VERSION 5.8 ;
BUSBITCHARS "[]" ;
DIVIDERCHAR "/" ;
UNITS
    DATABASE MICRONS 1000 ;
END UNITS

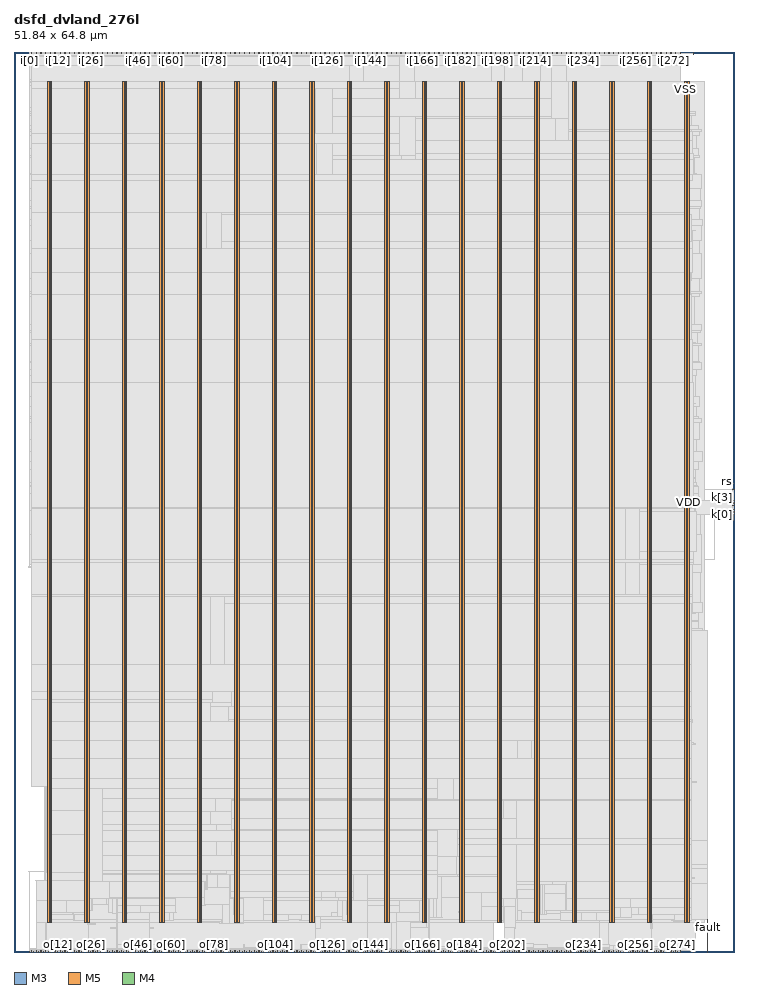
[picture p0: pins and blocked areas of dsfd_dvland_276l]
MACRO dsfd_dvland_276l
  FOREIGN dsfd_dvland_276l 0 0 ;
  CLASS BLOCK ;
  SIZE 51.84 BY 64.8 ;
  PIN ck
    DIRECTION INPUT ;
    USE SIGNAL ;
    PORT
      LAYER M3 ;
        RECT  48.924 0 48.942 0.038 ;
    END
    PORT
      LAYER M3 ;
        RECT  48.924 0.012 48.942 0.091 ;
    END
  END ck
  PIN ck_f
    DIRECTION INPUT ;
    USE SIGNAL ;
    PORT
      LAYER M3 ;
        RECT  48.924 64.762 48.942 64.8 ;
    END
    PORT
      LAYER M3 ;
        RECT  48.924 64.651 48.942 64.781 ;
    END
  END ck_f
  PIN fault
    DIRECTION OUTPUT ;
    USE SIGNAL ;
    PORT
      LAYER M3 ;
        RECT  49.932 0 49.95 0.038 ;
    END
    PORT
      LAYER M3 ;
        RECT  49.932 0.012 49.95 2.371 ;
    END
  END fault
  PIN i[0]
    DIRECTION INPUT ;
    USE SIGNAL ;
    PORT
      LAYER M3 ;
        RECT  1.08 64.762 1.098 64.8 ;
    END
  END i[0]
  PIN i[100]
    DIRECTION INPUT ;
    USE SIGNAL ;
    PORT
      LAYER M3 ;
        RECT  18.108 64.762 18.126 64.8 ;
    END
  END i[100]
  PIN i[101]
    DIRECTION INPUT ;
    USE SIGNAL ;
    PORT
      LAYER M5 ;
        RECT  18.288 64.716 18.312 64.8 ;
    END
  END i[101]
  PIN i[102]
    DIRECTION INPUT ;
    USE SIGNAL ;
    PORT
      LAYER M3 ;
        RECT  18.468 64.762 18.486 64.8 ;
    END
  END i[102]
  PIN i[103]
    DIRECTION INPUT ;
    USE SIGNAL ;
    PORT
      LAYER M5 ;
        RECT  18.624 64.716 18.648 64.8 ;
    END
  END i[103]
  PIN i[104]
    DIRECTION INPUT ;
    USE SIGNAL ;
    PORT
      LAYER M3 ;
        RECT  18.792 64.762 18.81 64.8 ;
    END
  END i[104]
  PIN i[105]
    DIRECTION INPUT ;
    USE SIGNAL ;
    PORT
      LAYER M5 ;
        RECT  18.96 64.716 18.984 64.8 ;
    END
  END i[105]
  PIN i[106]
    DIRECTION INPUT ;
    USE SIGNAL ;
    PORT
      LAYER M3 ;
        RECT  19.152 64.762 19.17 64.8 ;
    END
  END i[106]
  PIN i[107]
    DIRECTION INPUT ;
    USE SIGNAL ;
    PORT
      LAYER M5 ;
        RECT  19.296 64.716 19.32 64.8 ;
    END
  END i[107]
  PIN i[108]
    DIRECTION INPUT ;
    USE SIGNAL ;
    PORT
      LAYER M3 ;
        RECT  19.476 64.762 19.494 64.8 ;
    END
  END i[108]
  PIN i[109]
    DIRECTION INPUT ;
    USE SIGNAL ;
    PORT
      LAYER M5 ;
        RECT  19.632 64.716 19.656 64.8 ;
    END
  END i[109]
  PIN i[10]
    DIRECTION INPUT ;
    USE SIGNAL ;
    PORT
      LAYER M3 ;
        RECT  2.772 64.762 2.79 64.8 ;
    END
  END i[10]
  PIN i[110]
    DIRECTION INPUT ;
    USE SIGNAL ;
    PORT
      LAYER M3 ;
        RECT  19.836 64.762 19.854 64.8 ;
    END
  END i[110]
  PIN i[111]
    DIRECTION INPUT ;
    USE SIGNAL ;
    PORT
      LAYER M5 ;
        RECT  19.968 64.716 19.992 64.8 ;
    END
  END i[111]
  PIN i[112]
    DIRECTION INPUT ;
    USE SIGNAL ;
    PORT
      LAYER M3 ;
        RECT  20.16 64.762 20.178 64.8 ;
    END
  END i[112]
  PIN i[113]
    DIRECTION INPUT ;
    USE SIGNAL ;
    PORT
      LAYER M5 ;
        RECT  20.352 64.716 20.376 64.8 ;
    END
  END i[113]
  PIN i[114]
    DIRECTION INPUT ;
    USE SIGNAL ;
    PORT
      LAYER M3 ;
        RECT  20.52 64.762 20.538 64.8 ;
    END
  END i[114]
  PIN i[115]
    DIRECTION INPUT ;
    USE SIGNAL ;
    PORT
      LAYER M5 ;
        RECT  20.688 64.716 20.712 64.8 ;
    END
  END i[115]
  PIN i[116]
    DIRECTION INPUT ;
    USE SIGNAL ;
    PORT
      LAYER M3 ;
        RECT  20.844 64.762 20.862 64.8 ;
    END
  END i[116]
  PIN i[117]
    DIRECTION INPUT ;
    USE SIGNAL ;
    PORT
      LAYER M5 ;
        RECT  21.024 64.716 21.048 64.8 ;
    END
  END i[117]
  PIN i[118]
    DIRECTION INPUT ;
    USE SIGNAL ;
    PORT
      LAYER M3 ;
        RECT  21.204 64.762 21.222 64.8 ;
    END
  END i[118]
  PIN i[119]
    DIRECTION INPUT ;
    USE SIGNAL ;
    PORT
      LAYER M5 ;
        RECT  21.36 64.716 21.384 64.8 ;
    END
  END i[119]
  PIN i[11]
    DIRECTION INPUT ;
    USE SIGNAL ;
    PORT
      LAYER M5 ;
        RECT  2.928 64.716 2.952 64.8 ;
    END
  END i[11]
  PIN i[120]
    DIRECTION INPUT ;
    USE SIGNAL ;
    PORT
      LAYER M3 ;
        RECT  21.528 64.762 21.546 64.8 ;
    END
  END i[120]
  PIN i[121]
    DIRECTION INPUT ;
    USE SIGNAL ;
    PORT
      LAYER M5 ;
        RECT  21.696 64.716 21.72 64.8 ;
    END
  END i[121]
  PIN i[122]
    DIRECTION INPUT ;
    USE SIGNAL ;
    PORT
      LAYER M3 ;
        RECT  21.852 64.762 21.87 64.8 ;
    END
  END i[122]
  PIN i[123]
    DIRECTION INPUT ;
    USE SIGNAL ;
    PORT
      LAYER M5 ;
        RECT  22.032 64.716 22.056 64.8 ;
    END
  END i[123]
  PIN i[124]
    DIRECTION INPUT ;
    USE SIGNAL ;
    PORT
      LAYER M3 ;
        RECT  22.212 64.762 22.23 64.8 ;
    END
  END i[124]
  PIN i[125]
    DIRECTION INPUT ;
    USE SIGNAL ;
    PORT
      LAYER M5 ;
        RECT  22.368 64.716 22.392 64.8 ;
    END
  END i[125]
  PIN i[126]
    DIRECTION INPUT ;
    USE SIGNAL ;
    PORT
      LAYER M3 ;
        RECT  22.536 64.762 22.554 64.8 ;
    END
  END i[126]
  PIN i[127]
    DIRECTION INPUT ;
    USE SIGNAL ;
    PORT
      LAYER M5 ;
        RECT  22.704 64.716 22.728 64.8 ;
    END
  END i[127]
  PIN i[128]
    DIRECTION INPUT ;
    USE SIGNAL ;
    PORT
      LAYER M3 ;
        RECT  22.896 64.762 22.914 64.8 ;
    END
  END i[128]
  PIN i[129]
    DIRECTION INPUT ;
    USE SIGNAL ;
    PORT
      LAYER M5 ;
        RECT  23.04 64.716 23.064 64.8 ;
    END
  END i[129]
  PIN i[12]
    DIRECTION INPUT ;
    USE SIGNAL ;
    PORT
      LAYER M3 ;
        RECT  3.132 64.762 3.15 64.8 ;
    END
  END i[12]
  PIN i[130]
    DIRECTION INPUT ;
    USE SIGNAL ;
    PORT
      LAYER M3 ;
        RECT  23.22 64.762 23.238 64.8 ;
    END
  END i[130]
  PIN i[131]
    DIRECTION INPUT ;
    USE SIGNAL ;
    PORT
      LAYER M5 ;
        RECT  23.424 64.716 23.448 64.8 ;
    END
  END i[131]
  PIN i[132]
    DIRECTION INPUT ;
    USE SIGNAL ;
    PORT
      LAYER M3 ;
        RECT  23.58 64.762 23.598 64.8 ;
    END
  END i[132]
  PIN i[133]
    DIRECTION INPUT ;
    USE SIGNAL ;
    PORT
      LAYER M5 ;
        RECT  23.76 64.716 23.784 64.8 ;
    END
  END i[133]
  PIN i[134]
    DIRECTION INPUT ;
    USE SIGNAL ;
    PORT
      LAYER M3 ;
        RECT  23.904 64.762 23.922 64.8 ;
    END
  END i[134]
  PIN i[135]
    DIRECTION INPUT ;
    USE SIGNAL ;
    PORT
      LAYER M5 ;
        RECT  24.096 64.716 24.12 64.8 ;
    END
  END i[135]
  PIN i[136]
    DIRECTION INPUT ;
    USE SIGNAL ;
    PORT
      LAYER M3 ;
        RECT  24.264 64.762 24.282 64.8 ;
    END
  END i[136]
  PIN i[137]
    DIRECTION INPUT ;
    USE SIGNAL ;
    PORT
      LAYER M5 ;
        RECT  24.432 64.716 24.456 64.8 ;
    END
  END i[137]
  PIN i[138]
    DIRECTION INPUT ;
    USE SIGNAL ;
    PORT
      LAYER M3 ;
        RECT  24.588 64.762 24.606 64.8 ;
    END
  END i[138]
  PIN i[139]
    DIRECTION INPUT ;
    USE SIGNAL ;
    PORT
      LAYER M5 ;
        RECT  24.768 64.716 24.792 64.8 ;
    END
  END i[139]
  PIN i[13]
    DIRECTION INPUT ;
    USE SIGNAL ;
    PORT
      LAYER M5 ;
        RECT  3.312 64.716 3.336 64.8 ;
    END
  END i[13]
  PIN i[140]
    DIRECTION INPUT ;
    USE SIGNAL ;
    PORT
      LAYER M3 ;
        RECT  24.948 64.762 24.966 64.8 ;
    END
  END i[140]
  PIN i[141]
    DIRECTION INPUT ;
    USE SIGNAL ;
    PORT
      LAYER M5 ;
        RECT  25.104 64.716 25.128 64.8 ;
    END
  END i[141]
  PIN i[142]
    DIRECTION INPUT ;
    USE SIGNAL ;
    PORT
      LAYER M3 ;
        RECT  25.272 64.762 25.29 64.8 ;
    END
  END i[142]
  PIN i[143]
    DIRECTION INPUT ;
    USE SIGNAL ;
    PORT
      LAYER M5 ;
        RECT  25.44 64.716 25.464 64.8 ;
    END
  END i[143]
  PIN i[144]
    DIRECTION INPUT ;
    USE SIGNAL ;
    PORT
      LAYER M3 ;
        RECT  25.632 64.762 25.65 64.8 ;
    END
  END i[144]
  PIN i[145]
    DIRECTION INPUT ;
    USE SIGNAL ;
    PORT
      LAYER M5 ;
        RECT  25.776 64.716 25.8 64.8 ;
    END
  END i[145]
  PIN i[146]
    DIRECTION INPUT ;
    USE SIGNAL ;
    PORT
      LAYER M3 ;
        RECT  25.956 64.762 25.974 64.8 ;
    END
  END i[146]
  PIN i[147]
    DIRECTION INPUT ;
    USE SIGNAL ;
    PORT
      LAYER M5 ;
        RECT  26.112 64.716 26.136 64.8 ;
    END
  END i[147]
  PIN i[148]
    DIRECTION INPUT ;
    USE SIGNAL ;
    PORT
      LAYER M3 ;
        RECT  26.316 64.762 26.334 64.8 ;
    END
  END i[148]
  PIN i[149]
    DIRECTION INPUT ;
    USE SIGNAL ;
    PORT
      LAYER M5 ;
        RECT  26.448 64.716 26.472 64.8 ;
    END
  END i[149]
  PIN i[14]
    DIRECTION INPUT ;
    USE SIGNAL ;
    PORT
      LAYER M3 ;
        RECT  3.456 64.762 3.474 64.8 ;
    END
  END i[14]
  PIN i[150]
    DIRECTION INPUT ;
    USE SIGNAL ;
    PORT
      LAYER M3 ;
        RECT  26.64 64.762 26.658 64.8 ;
    END
  END i[150]
  PIN i[151]
    DIRECTION INPUT ;
    USE SIGNAL ;
    PORT
      LAYER M5 ;
        RECT  26.832 64.716 26.856 64.8 ;
    END
  END i[151]
  PIN i[152]
    DIRECTION INPUT ;
    USE SIGNAL ;
    PORT
      LAYER M3 ;
        RECT  27 64.762 27.018 64.8 ;
    END
  END i[152]
  PIN i[153]
    DIRECTION INPUT ;
    USE SIGNAL ;
    PORT
      LAYER M5 ;
        RECT  27.168 64.716 27.192 64.8 ;
    END
  END i[153]
  PIN i[154]
    DIRECTION INPUT ;
    USE SIGNAL ;
    PORT
      LAYER M3 ;
        RECT  27.324 64.762 27.342 64.8 ;
    END
  END i[154]
  PIN i[155]
    DIRECTION INPUT ;
    USE SIGNAL ;
    PORT
      LAYER M5 ;
        RECT  27.504 64.716 27.528 64.8 ;
    END
  END i[155]
  PIN i[156]
    DIRECTION INPUT ;
    USE SIGNAL ;
    PORT
      LAYER M3 ;
        RECT  27.648 64.762 27.666 64.8 ;
    END
  END i[156]
  PIN i[157]
    DIRECTION INPUT ;
    USE SIGNAL ;
    PORT
      LAYER M5 ;
        RECT  27.84 64.716 27.864 64.8 ;
    END
  END i[157]
  PIN i[158]
    DIRECTION INPUT ;
    USE SIGNAL ;
    PORT
      LAYER M3 ;
        RECT  28.008 64.762 28.026 64.8 ;
    END
  END i[158]
  PIN i[159]
    DIRECTION INPUT ;
    USE SIGNAL ;
    PORT
      LAYER M5 ;
        RECT  28.176 64.716 28.2 64.8 ;
    END
  END i[159]
  PIN i[15]
    DIRECTION INPUT ;
    USE SIGNAL ;
    PORT
      LAYER M5 ;
        RECT  3.648 64.716 3.672 64.8 ;
    END
  END i[15]
  PIN i[160]
    DIRECTION INPUT ;
    USE SIGNAL ;
    PORT
      LAYER M3 ;
        RECT  28.332 64.762 28.35 64.8 ;
    END
  END i[160]
  PIN i[161]
    DIRECTION INPUT ;
    USE SIGNAL ;
    PORT
      LAYER M5 ;
        RECT  28.512 64.716 28.536 64.8 ;
    END
  END i[161]
  PIN i[162]
    DIRECTION INPUT ;
    USE SIGNAL ;
    PORT
      LAYER M3 ;
        RECT  28.692 64.762 28.71 64.8 ;
    END
  END i[162]
  PIN i[163]
    DIRECTION INPUT ;
    USE SIGNAL ;
    PORT
      LAYER M5 ;
        RECT  28.848 64.716 28.872 64.8 ;
    END
  END i[163]
  PIN i[164]
    DIRECTION INPUT ;
    USE SIGNAL ;
    PORT
      LAYER M3 ;
        RECT  29.016 64.762 29.034 64.8 ;
    END
  END i[164]
  PIN i[165]
    DIRECTION INPUT ;
    USE SIGNAL ;
    PORT
      LAYER M5 ;
        RECT  29.184 64.716 29.208 64.8 ;
    END
  END i[165]
  PIN i[166]
    DIRECTION INPUT ;
    USE SIGNAL ;
    PORT
      LAYER M3 ;
        RECT  29.376 64.762 29.394 64.8 ;
    END
  END i[166]
  PIN i[167]
    DIRECTION INPUT ;
    USE SIGNAL ;
    PORT
      LAYER M5 ;
        RECT  29.52 64.716 29.544 64.8 ;
    END
  END i[167]
  PIN i[168]
    DIRECTION INPUT ;
    USE SIGNAL ;
    PORT
      LAYER M3 ;
        RECT  29.7 64.762 29.718 64.8 ;
    END
  END i[168]
  PIN i[169]
    DIRECTION INPUT ;
    USE SIGNAL ;
    PORT
      LAYER M5 ;
        RECT  29.856 64.716 29.88 64.8 ;
    END
  END i[169]
  PIN i[16]
    DIRECTION INPUT ;
    USE SIGNAL ;
    PORT
      LAYER M3 ;
        RECT  3.816 64.762 3.834 64.8 ;
    END
  END i[16]
  PIN i[170]
    DIRECTION INPUT ;
    USE SIGNAL ;
    PORT
      LAYER M3 ;
        RECT  30.06 64.762 30.078 64.8 ;
    END
  END i[170]
  PIN i[171]
    DIRECTION INPUT ;
    USE SIGNAL ;
    PORT
      LAYER M5 ;
        RECT  30.24 64.716 30.264 64.8 ;
    END
  END i[171]
  PIN i[172]
    DIRECTION INPUT ;
    USE SIGNAL ;
    PORT
      LAYER M3 ;
        RECT  30.384 64.762 30.402 64.8 ;
    END
  END i[172]
  PIN i[173]
    DIRECTION INPUT ;
    USE SIGNAL ;
    PORT
      LAYER M5 ;
        RECT  30.576 64.716 30.6 64.8 ;
    END
  END i[173]
  PIN i[174]
    DIRECTION INPUT ;
    USE SIGNAL ;
    PORT
      LAYER M3 ;
        RECT  30.744 64.762 30.762 64.8 ;
    END
  END i[174]
  PIN i[175]
    DIRECTION INPUT ;
    USE SIGNAL ;
    PORT
      LAYER M5 ;
        RECT  30.912 64.716 30.936 64.8 ;
    END
  END i[175]
  PIN i[176]
    DIRECTION INPUT ;
    USE SIGNAL ;
    PORT
      LAYER M3 ;
        RECT  31.068 64.762 31.086 64.8 ;
    END
  END i[176]
  PIN i[177]
    DIRECTION INPUT ;
    USE SIGNAL ;
    PORT
      LAYER M5 ;
        RECT  31.248 64.716 31.272 64.8 ;
    END
  END i[177]
  PIN i[178]
    DIRECTION INPUT ;
    USE SIGNAL ;
    PORT
      LAYER M3 ;
        RECT  31.428 64.762 31.446 64.8 ;
    END
  END i[178]
  PIN i[179]
    DIRECTION INPUT ;
    USE SIGNAL ;
    PORT
      LAYER M5 ;
        RECT  31.584 64.716 31.608 64.8 ;
    END
  END i[179]
  PIN i[17]
    DIRECTION INPUT ;
    USE SIGNAL ;
    PORT
      LAYER M5 ;
        RECT  3.984 64.716 4.008 64.8 ;
    END
  END i[17]
  PIN i[180]
    DIRECTION INPUT ;
    USE SIGNAL ;
    PORT
      LAYER M3 ;
        RECT  31.752 64.762 31.77 64.8 ;
    END
  END i[180]
  PIN i[181]
    DIRECTION INPUT ;
    USE SIGNAL ;
    PORT
      LAYER M5 ;
        RECT  31.92 64.716 31.944 64.8 ;
    END
  END i[181]
  PIN i[182]
    DIRECTION INPUT ;
    USE SIGNAL ;
    PORT
      LAYER M3 ;
        RECT  32.112 64.762 32.13 64.8 ;
    END
  END i[182]
  PIN i[183]
    DIRECTION INPUT ;
    USE SIGNAL ;
    PORT
      LAYER M5 ;
        RECT  32.256 64.716 32.28 64.8 ;
    END
  END i[183]
  PIN i[184]
    DIRECTION INPUT ;
    USE SIGNAL ;
    PORT
      LAYER M3 ;
        RECT  32.436 64.762 32.454 64.8 ;
    END
  END i[184]
  PIN i[185]
    DIRECTION INPUT ;
    USE SIGNAL ;
    PORT
      LAYER M5 ;
        RECT  32.592 64.716 32.616 64.8 ;
    END
  END i[185]
  PIN i[186]
    DIRECTION INPUT ;
    USE SIGNAL ;
    PORT
      LAYER M3 ;
        RECT  32.76 64.762 32.778 64.8 ;
    END
  END i[186]
  PIN i[187]
    DIRECTION INPUT ;
    USE SIGNAL ;
    PORT
      LAYER M5 ;
        RECT  32.928 64.716 32.952 64.8 ;
    END
  END i[187]
  PIN i[188]
    DIRECTION INPUT ;
    USE SIGNAL ;
    PORT
      LAYER M3 ;
        RECT  33.12 64.762 33.138 64.8 ;
    END
  END i[188]
  PIN i[189]
    DIRECTION INPUT ;
    USE SIGNAL ;
    PORT
      LAYER M5 ;
        RECT  33.264 64.716 33.288 64.8 ;
    END
  END i[189]
  PIN i[18]
    DIRECTION INPUT ;
    USE SIGNAL ;
    PORT
      LAYER M3 ;
        RECT  4.14 64.762 4.158 64.8 ;
    END
  END i[18]
  PIN i[190]
    DIRECTION INPUT ;
    USE SIGNAL ;
    PORT
      LAYER M3 ;
        RECT  33.444 64.762 33.462 64.8 ;
    END
  END i[190]
  PIN i[191]
    DIRECTION INPUT ;
    USE SIGNAL ;
    PORT
      LAYER M5 ;
        RECT  33.648 64.716 33.672 64.8 ;
    END
  END i[191]
  PIN i[192]
    DIRECTION INPUT ;
    USE SIGNAL ;
    PORT
      LAYER M3 ;
        RECT  33.804 64.762 33.822 64.8 ;
    END
  END i[192]
  PIN i[193]
    DIRECTION INPUT ;
    USE SIGNAL ;
    PORT
      LAYER M5 ;
        RECT  33.984 64.716 34.008 64.8 ;
    END
  END i[193]
  PIN i[194]
    DIRECTION INPUT ;
    USE SIGNAL ;
    PORT
      LAYER M3 ;
        RECT  34.128 64.762 34.146 64.8 ;
    END
  END i[194]
  PIN i[195]
    DIRECTION INPUT ;
    USE SIGNAL ;
    PORT
      LAYER M5 ;
        RECT  34.32 64.716 34.344 64.8 ;
    END
  END i[195]
  PIN i[196]
    DIRECTION INPUT ;
    USE SIGNAL ;
    PORT
      LAYER M3 ;
        RECT  34.488 64.762 34.506 64.8 ;
    END
  END i[196]
  PIN i[197]
    DIRECTION INPUT ;
    USE SIGNAL ;
    PORT
      LAYER M5 ;
        RECT  34.656 64.716 34.68 64.8 ;
    END
  END i[197]
  PIN i[198]
    DIRECTION INPUT ;
    USE SIGNAL ;
    PORT
      LAYER M3 ;
        RECT  34.812 64.762 34.83 64.8 ;
    END
  END i[198]
  PIN i[199]
    DIRECTION INPUT ;
    USE SIGNAL ;
    PORT
      LAYER M5 ;
        RECT  34.992 64.716 35.016 64.8 ;
    END
  END i[199]
  PIN i[19]
    DIRECTION INPUT ;
    USE SIGNAL ;
    PORT
      LAYER M5 ;
        RECT  4.32 64.716 4.344 64.8 ;
    END
  END i[19]
  PIN i[1]
    DIRECTION INPUT ;
    USE SIGNAL ;
    PORT
      LAYER M5 ;
        RECT  1.248 64.716 1.272 64.8 ;
    END
  END i[1]
  PIN i[200]
    DIRECTION INPUT ;
    USE SIGNAL ;
    PORT
      LAYER M3 ;
        RECT  35.172 64.762 35.19 64.8 ;
    END
  END i[200]
  PIN i[201]
    DIRECTION INPUT ;
    USE SIGNAL ;
    PORT
      LAYER M5 ;
        RECT  35.328 64.716 35.352 64.8 ;
    END
  END i[201]
  PIN i[202]
    DIRECTION INPUT ;
    USE SIGNAL ;
    PORT
      LAYER M3 ;
        RECT  35.496 64.762 35.514 64.8 ;
    END
  END i[202]
  PIN i[203]
    DIRECTION INPUT ;
    USE SIGNAL ;
    PORT
      LAYER M5 ;
        RECT  35.664 64.716 35.688 64.8 ;
    END
  END i[203]
  PIN i[204]
    DIRECTION INPUT ;
    USE SIGNAL ;
    PORT
      LAYER M3 ;
        RECT  35.856 64.762 35.874 64.8 ;
    END
  END i[204]
  PIN i[205]
    DIRECTION INPUT ;
    USE SIGNAL ;
    PORT
      LAYER M5 ;
        RECT  36 64.716 36.024 64.8 ;
    END
  END i[205]
  PIN i[206]
    DIRECTION INPUT ;
    USE SIGNAL ;
    PORT
      LAYER M3 ;
        RECT  36.18 64.762 36.198 64.8 ;
    END
  END i[206]
  PIN i[207]
    DIRECTION INPUT ;
    USE SIGNAL ;
    PORT
      LAYER M5 ;
        RECT  36.336 64.716 36.36 64.8 ;
    END
  END i[207]
  PIN i[208]
    DIRECTION INPUT ;
    USE SIGNAL ;
    PORT
      LAYER M3 ;
        RECT  36.54 64.762 36.558 64.8 ;
    END
  END i[208]
  PIN i[209]
    DIRECTION INPUT ;
    USE SIGNAL ;
    PORT
      LAYER M5 ;
        RECT  36.672 64.716 36.696 64.8 ;
    END
  END i[209]
  PIN i[20]
    DIRECTION INPUT ;
    USE SIGNAL ;
    PORT
      LAYER M3 ;
        RECT  4.5 64.762 4.518 64.8 ;
    END
  END i[20]
  PIN i[210]
    DIRECTION INPUT ;
    USE SIGNAL ;
    PORT
      LAYER M3 ;
        RECT  36.864 64.762 36.882 64.8 ;
    END
  END i[210]
  PIN i[211]
    DIRECTION INPUT ;
    USE SIGNAL ;
    PORT
      LAYER M5 ;
        RECT  37.056 64.716 37.08 64.8 ;
    END
  END i[211]
  PIN i[212]
    DIRECTION INPUT ;
    USE SIGNAL ;
    PORT
      LAYER M3 ;
        RECT  37.224 64.762 37.242 64.8 ;
    END
  END i[212]
  PIN i[213]
    DIRECTION INPUT ;
    USE SIGNAL ;
    PORT
      LAYER M5 ;
        RECT  37.392 64.716 37.416 64.8 ;
    END
  END i[213]
  PIN i[214]
    DIRECTION INPUT ;
    USE SIGNAL ;
    PORT
      LAYER M3 ;
        RECT  37.548 64.762 37.566 64.8 ;
    END
  END i[214]
  PIN i[215]
    DIRECTION INPUT ;
    USE SIGNAL ;
    PORT
      LAYER M5 ;
        RECT  37.728 64.716 37.752 64.8 ;
    END
  END i[215]
  PIN i[216]
    DIRECTION INPUT ;
    USE SIGNAL ;
    PORT
      LAYER M3 ;
        RECT  37.908 64.762 37.926 64.8 ;
    END
  END i[216]
  PIN i[217]
    DIRECTION INPUT ;
    USE SIGNAL ;
    PORT
      LAYER M5 ;
        RECT  38.064 64.716 38.088 64.8 ;
    END
  END i[217]
  PIN i[218]
    DIRECTION INPUT ;
    USE SIGNAL ;
    PORT
      LAYER M3 ;
        RECT  38.232 64.762 38.25 64.8 ;
    END
  END i[218]
  PIN i[219]
    DIRECTION INPUT ;
    USE SIGNAL ;
    PORT
      LAYER M5 ;
        RECT  38.4 64.716 38.424 64.8 ;
    END
  END i[219]
  PIN i[21]
    DIRECTION INPUT ;
    USE SIGNAL ;
    PORT
      LAYER M5 ;
        RECT  4.656 64.716 4.68 64.8 ;
    END
  END i[21]
  PIN i[220]
    DIRECTION INPUT ;
    USE SIGNAL ;
    PORT
      LAYER M3 ;
        RECT  38.556 64.762 38.574 64.8 ;
    END
  END i[220]
  PIN i[221]
    DIRECTION INPUT ;
    USE SIGNAL ;
    PORT
      LAYER M5 ;
        RECT  38.736 64.716 38.76 64.8 ;
    END
  END i[221]
  PIN i[222]
    DIRECTION INPUT ;
    USE SIGNAL ;
    PORT
      LAYER M3 ;
        RECT  38.916 64.762 38.934 64.8 ;
    END
  END i[222]
  PIN i[223]
    DIRECTION INPUT ;
    USE SIGNAL ;
    PORT
      LAYER M5 ;
        RECT  39.072 64.716 39.096 64.8 ;
    END
  END i[223]
  PIN i[224]
    DIRECTION INPUT ;
    USE SIGNAL ;
    PORT
      LAYER M3 ;
        RECT  39.24 64.762 39.258 64.8 ;
    END
  END i[224]
  PIN i[225]
    DIRECTION INPUT ;
    USE SIGNAL ;
    PORT
      LAYER M5 ;
        RECT  39.408 64.716 39.432 64.8 ;
    END
  END i[225]
  PIN i[226]
    DIRECTION INPUT ;
    USE SIGNAL ;
    PORT
      LAYER M3 ;
        RECT  39.6 64.762 39.618 64.8 ;
    END
  END i[226]
  PIN i[227]
    DIRECTION INPUT ;
    USE SIGNAL ;
    PORT
      LAYER M5 ;
        RECT  39.744 64.716 39.768 64.8 ;
    END
  END i[227]
  PIN i[228]
    DIRECTION INPUT ;
    USE SIGNAL ;
    PORT
      LAYER M3 ;
        RECT  39.924 64.762 39.942 64.8 ;
    END
  END i[228]
  PIN i[229]
    DIRECTION INPUT ;
    USE SIGNAL ;
    PORT
      LAYER M5 ;
        RECT  40.08 64.716 40.104 64.8 ;
    END
  END i[229]
  PIN i[22]
    DIRECTION INPUT ;
    USE SIGNAL ;
    PORT
      LAYER M3 ;
        RECT  4.824 64.762 4.842 64.8 ;
    END
  END i[22]
  PIN i[230]
    DIRECTION INPUT ;
    USE SIGNAL ;
    PORT
      LAYER M3 ;
        RECT  40.284 64.762 40.302 64.8 ;
    END
  END i[230]
  PIN i[231]
    DIRECTION INPUT ;
    USE SIGNAL ;
    PORT
      LAYER M5 ;
        RECT  40.464 64.716 40.488 64.8 ;
    END
  END i[231]
  PIN i[232]
    DIRECTION INPUT ;
    USE SIGNAL ;
    PORT
      LAYER M3 ;
        RECT  40.608 64.762 40.626 64.8 ;
    END
  END i[232]
  PIN i[233]
    DIRECTION INPUT ;
    USE SIGNAL ;
    PORT
      LAYER M5 ;
        RECT  40.8 64.716 40.824 64.8 ;
    END
  END i[233]
  PIN i[234]
    DIRECTION INPUT ;
    USE SIGNAL ;
    PORT
      LAYER M3 ;
        RECT  40.968 64.762 40.986 64.8 ;
    END
  END i[234]
  PIN i[235]
    DIRECTION INPUT ;
    USE SIGNAL ;
    PORT
      LAYER M5 ;
        RECT  41.136 64.716 41.16 64.8 ;
    END
  END i[235]
  PIN i[236]
    DIRECTION INPUT ;
    USE SIGNAL ;
    PORT
      LAYER M3 ;
        RECT  41.292 64.762 41.31 64.8 ;
    END
  END i[236]
  PIN i[237]
    DIRECTION INPUT ;
    USE SIGNAL ;
    PORT
      LAYER M5 ;
        RECT  41.472 64.716 41.496 64.8 ;
    END
  END i[237]
  PIN i[238]
    DIRECTION INPUT ;
    USE SIGNAL ;
    PORT
      LAYER M3 ;
        RECT  41.652 64.762 41.67 64.8 ;
    END
  END i[238]
  PIN i[239]
    DIRECTION INPUT ;
    USE SIGNAL ;
    PORT
      LAYER M5 ;
        RECT  41.808 64.716 41.832 64.8 ;
    END
  END i[239]
  PIN i[23]
    DIRECTION INPUT ;
    USE SIGNAL ;
    PORT
      LAYER M5 ;
        RECT  4.992 64.716 5.016 64.8 ;
    END
  END i[23]
  PIN i[240]
    DIRECTION INPUT ;
    USE SIGNAL ;
    PORT
      LAYER M3 ;
        RECT  41.976 64.762 41.994 64.8 ;
    END
  END i[240]
  PIN i[241]
    DIRECTION INPUT ;
    USE SIGNAL ;
    PORT
      LAYER M5 ;
        RECT  42.144 64.716 42.168 64.8 ;
    END
  END i[241]
  PIN i[242]
    DIRECTION INPUT ;
    USE SIGNAL ;
    PORT
      LAYER M3 ;
        RECT  42.336 64.762 42.354 64.8 ;
    END
  END i[242]
  PIN i[243]
    DIRECTION INPUT ;
    USE SIGNAL ;
    PORT
      LAYER M5 ;
        RECT  42.48 64.716 42.504 64.8 ;
    END
  END i[243]
  PIN i[244]
    DIRECTION INPUT ;
    USE SIGNAL ;
    PORT
      LAYER M3 ;
        RECT  42.66 64.762 42.678 64.8 ;
    END
  END i[244]
  PIN i[245]
    DIRECTION INPUT ;
    USE SIGNAL ;
    PORT
      LAYER M5 ;
        RECT  42.816 64.716 42.84 64.8 ;
    END
  END i[245]
  PIN i[246]
    DIRECTION INPUT ;
    USE SIGNAL ;
    PORT
      LAYER M3 ;
        RECT  43.02 64.762 43.038 64.8 ;
    END
  END i[246]
  PIN i[247]
    DIRECTION INPUT ;
    USE SIGNAL ;
    PORT
      LAYER M5 ;
        RECT  43.152 64.716 43.176 64.8 ;
    END
  END i[247]
  PIN i[248]
    DIRECTION INPUT ;
    USE SIGNAL ;
    PORT
      LAYER M3 ;
        RECT  43.344 64.762 43.362 64.8 ;
    END
  END i[248]
  PIN i[249]
    DIRECTION INPUT ;
    USE SIGNAL ;
    PORT
      LAYER M5 ;
        RECT  43.488 64.716 43.512 64.8 ;
    END
  END i[249]
  PIN i[24]
    DIRECTION INPUT ;
    USE SIGNAL ;
    PORT
      LAYER M3 ;
        RECT  5.184 64.762 5.202 64.8 ;
    END
  END i[24]
  PIN i[250]
    DIRECTION INPUT ;
    USE SIGNAL ;
    PORT
      LAYER M3 ;
        RECT  43.668 64.762 43.686 64.8 ;
    END
  END i[250]
  PIN i[251]
    DIRECTION INPUT ;
    USE SIGNAL ;
    PORT
      LAYER M5 ;
        RECT  43.872 64.716 43.896 64.8 ;
    END
  END i[251]
  PIN i[252]
    DIRECTION INPUT ;
    USE SIGNAL ;
    PORT
      LAYER M3 ;
        RECT  44.028 64.762 44.046 64.8 ;
    END
  END i[252]
  PIN i[253]
    DIRECTION INPUT ;
    USE SIGNAL ;
    PORT
      LAYER M5 ;
        RECT  44.208 64.716 44.232 64.8 ;
    END
  END i[253]
  PIN i[254]
    DIRECTION INPUT ;
    USE SIGNAL ;
    PORT
      LAYER M3 ;
        RECT  44.352 64.762 44.37 64.8 ;
    END
  END i[254]
  PIN i[255]
    DIRECTION INPUT ;
    USE SIGNAL ;
    PORT
      LAYER M5 ;
        RECT  44.544 64.716 44.568 64.8 ;
    END
  END i[255]
  PIN i[256]
    DIRECTION INPUT ;
    USE SIGNAL ;
    PORT
      LAYER M3 ;
        RECT  44.712 64.762 44.73 64.8 ;
    END
  END i[256]
  PIN i[257]
    DIRECTION INPUT ;
    USE SIGNAL ;
    PORT
      LAYER M5 ;
        RECT  44.88 64.716 44.904 64.8 ;
    END
  END i[257]
  PIN i[258]
    DIRECTION INPUT ;
    USE SIGNAL ;
    PORT
      LAYER M3 ;
        RECT  45.036 64.762 45.054 64.8 ;
    END
  END i[258]
  PIN i[259]
    DIRECTION INPUT ;
    USE SIGNAL ;
    PORT
      LAYER M5 ;
        RECT  45.216 64.716 45.24 64.8 ;
    END
  END i[259]
  PIN i[25]
    DIRECTION INPUT ;
    USE SIGNAL ;
    PORT
      LAYER M5 ;
        RECT  5.328 64.716 5.352 64.8 ;
    END
  END i[25]
  PIN i[260]
    DIRECTION INPUT ;
    USE SIGNAL ;
    PORT
      LAYER M3 ;
        RECT  45.396 64.762 45.414 64.8 ;
    END
  END i[260]
  PIN i[261]
    DIRECTION INPUT ;
    USE SIGNAL ;
    PORT
      LAYER M5 ;
        RECT  45.552 64.716 45.576 64.8 ;
    END
  END i[261]
  PIN i[262]
    DIRECTION INPUT ;
    USE SIGNAL ;
    PORT
      LAYER M3 ;
        RECT  45.72 64.762 45.738 64.8 ;
    END
  END i[262]
  PIN i[263]
    DIRECTION INPUT ;
    USE SIGNAL ;
    PORT
      LAYER M5 ;
        RECT  45.888 64.716 45.912 64.8 ;
    END
  END i[263]
  PIN i[264]
    DIRECTION INPUT ;
    USE SIGNAL ;
    PORT
      LAYER M3 ;
        RECT  46.08 64.762 46.098 64.8 ;
    END
  END i[264]
  PIN i[265]
    DIRECTION INPUT ;
    USE SIGNAL ;
    PORT
      LAYER M5 ;
        RECT  46.224 64.716 46.248 64.8 ;
    END
  END i[265]
  PIN i[266]
    DIRECTION INPUT ;
    USE SIGNAL ;
    PORT
      LAYER M3 ;
        RECT  46.404 64.762 46.422 64.8 ;
    END
  END i[266]
  PIN i[267]
    DIRECTION INPUT ;
    USE SIGNAL ;
    PORT
      LAYER M5 ;
        RECT  46.56 64.716 46.584 64.8 ;
    END
  END i[267]
  PIN i[268]
    DIRECTION INPUT ;
    USE SIGNAL ;
    PORT
      LAYER M3 ;
        RECT  46.764 64.762 46.782 64.8 ;
    END
  END i[268]
  PIN i[269]
    DIRECTION INPUT ;
    USE SIGNAL ;
    PORT
      LAYER M5 ;
        RECT  46.944 64.716 46.968 64.8 ;
    END
  END i[269]
  PIN i[26]
    DIRECTION INPUT ;
    USE SIGNAL ;
    PORT
      LAYER M3 ;
        RECT  5.508 64.762 5.526 64.8 ;
    END
  END i[26]
  PIN i[270]
    DIRECTION INPUT ;
    USE SIGNAL ;
    PORT
      LAYER M3 ;
        RECT  47.088 64.762 47.106 64.8 ;
    END
  END i[270]
  PIN i[271]
    DIRECTION INPUT ;
    USE SIGNAL ;
    PORT
      LAYER M5 ;
        RECT  47.28 64.716 47.304 64.8 ;
    END
  END i[271]
  PIN i[272]
    DIRECTION INPUT ;
    USE SIGNAL ;
    PORT
      LAYER M3 ;
        RECT  47.448 64.762 47.466 64.8 ;
    END
  END i[272]
  PIN i[273]
    DIRECTION INPUT ;
    USE SIGNAL ;
    PORT
      LAYER M5 ;
        RECT  47.616 64.716 47.64 64.8 ;
    END
  END i[273]
  PIN i[274]
    DIRECTION INPUT ;
    USE SIGNAL ;
    PORT
      LAYER M3 ;
        RECT  47.772 64.762 47.79 64.8 ;
    END
  END i[274]
  PIN i[275]
    DIRECTION INPUT ;
    USE SIGNAL ;
    PORT
      LAYER M5 ;
        RECT  47.952 64.716 47.976 64.8 ;
    END
  END i[275]
  PIN i[27]
    DIRECTION INPUT ;
    USE SIGNAL ;
    PORT
      LAYER M5 ;
        RECT  5.664 64.716 5.688 64.8 ;
    END
  END i[27]
  PIN i[28]
    DIRECTION INPUT ;
    USE SIGNAL ;
    PORT
      LAYER M3 ;
        RECT  5.832 64.762 5.85 64.8 ;
    END
  END i[28]
  PIN i[29]
    DIRECTION INPUT ;
    USE SIGNAL ;
    PORT
      LAYER M5 ;
        RECT  6 64.716 6.024 64.8 ;
    END
  END i[29]
  PIN i[2]
    DIRECTION INPUT ;
    USE SIGNAL ;
    PORT
      LAYER M3 ;
        RECT  1.404 64.762 1.422 64.8 ;
    END
  END i[2]
  PIN i[30]
    DIRECTION INPUT ;
    USE SIGNAL ;
    PORT
      LAYER M3 ;
        RECT  6.192 64.762 6.21 64.8 ;
    END
  END i[30]
  PIN i[31]
    DIRECTION INPUT ;
    USE SIGNAL ;
    PORT
      LAYER M5 ;
        RECT  6.336 64.716 6.36 64.8 ;
    END
  END i[31]
  PIN i[32]
    DIRECTION INPUT ;
    USE SIGNAL ;
    PORT
      LAYER M3 ;
        RECT  6.516 64.762 6.534 64.8 ;
    END
  END i[32]
  PIN i[33]
    DIRECTION INPUT ;
    USE SIGNAL ;
    PORT
      LAYER M5 ;
        RECT  6.72 64.716 6.744 64.8 ;
    END
  END i[33]
  PIN i[34]
    DIRECTION INPUT ;
    USE SIGNAL ;
    PORT
      LAYER M3 ;
        RECT  6.876 64.762 6.894 64.8 ;
    END
  END i[34]
  PIN i[35]
    DIRECTION INPUT ;
    USE SIGNAL ;
    PORT
      LAYER M5 ;
        RECT  7.056 64.716 7.08 64.8 ;
    END
  END i[35]
  PIN i[36]
    DIRECTION INPUT ;
    USE SIGNAL ;
    PORT
      LAYER M3 ;
        RECT  7.2 64.762 7.218 64.8 ;
    END
  END i[36]
  PIN i[37]
    DIRECTION INPUT ;
    USE SIGNAL ;
    PORT
      LAYER M5 ;
        RECT  7.392 64.716 7.416 64.8 ;
    END
  END i[37]
  PIN i[38]
    DIRECTION INPUT ;
    USE SIGNAL ;
    PORT
      LAYER M3 ;
        RECT  7.56 64.762 7.578 64.8 ;
    END
  END i[38]
  PIN i[39]
    DIRECTION INPUT ;
    USE SIGNAL ;
    PORT
      LAYER M5 ;
        RECT  7.728 64.716 7.752 64.8 ;
    END
  END i[39]
  PIN i[3]
    DIRECTION INPUT ;
    USE SIGNAL ;
    PORT
      LAYER M5 ;
        RECT  1.584 64.716 1.608 64.8 ;
    END
  END i[3]
  PIN i[40]
    DIRECTION INPUT ;
    USE SIGNAL ;
    PORT
      LAYER M3 ;
        RECT  7.884 64.762 7.902 64.8 ;
    END
  END i[40]
  PIN i[41]
    DIRECTION INPUT ;
    USE SIGNAL ;
    PORT
      LAYER M5 ;
        RECT  8.064 64.716 8.088 64.8 ;
    END
  END i[41]
  PIN i[42]
    DIRECTION INPUT ;
    USE SIGNAL ;
    PORT
      LAYER M3 ;
        RECT  8.244 64.762 8.262 64.8 ;
    END
  END i[42]
  PIN i[43]
    DIRECTION INPUT ;
    USE SIGNAL ;
    PORT
      LAYER M5 ;
        RECT  8.4 64.716 8.424 64.8 ;
    END
  END i[43]
  PIN i[44]
    DIRECTION INPUT ;
    USE SIGNAL ;
    PORT
      LAYER M3 ;
        RECT  8.568 64.762 8.586 64.8 ;
    END
  END i[44]
  PIN i[45]
    DIRECTION INPUT ;
    USE SIGNAL ;
    PORT
      LAYER M5 ;
        RECT  8.736 64.716 8.76 64.8 ;
    END
  END i[45]
  PIN i[46]
    DIRECTION INPUT ;
    USE SIGNAL ;
    PORT
      LAYER M3 ;
        RECT  8.928 64.762 8.946 64.8 ;
    END
  END i[46]
  PIN i[47]
    DIRECTION INPUT ;
    USE SIGNAL ;
    PORT
      LAYER M5 ;
        RECT  9.072 64.716 9.096 64.8 ;
    END
  END i[47]
  PIN i[48]
    DIRECTION INPUT ;
    USE SIGNAL ;
    PORT
      LAYER M3 ;
        RECT  9.252 64.762 9.27 64.8 ;
    END
  END i[48]
  PIN i[49]
    DIRECTION INPUT ;
    USE SIGNAL ;
    PORT
      LAYER M5 ;
        RECT  9.408 64.716 9.432 64.8 ;
    END
  END i[49]
  PIN i[4]
    DIRECTION INPUT ;
    USE SIGNAL ;
    PORT
      LAYER M3 ;
        RECT  1.764 64.762 1.782 64.8 ;
    END
  END i[4]
  PIN i[50]
    DIRECTION INPUT ;
    USE SIGNAL ;
    PORT
      LAYER M3 ;
        RECT  9.612 64.762 9.63 64.8 ;
    END
  END i[50]
  PIN i[51]
    DIRECTION INPUT ;
    USE SIGNAL ;
    PORT
      LAYER M5 ;
        RECT  9.744 64.716 9.768 64.8 ;
    END
  END i[51]
  PIN i[52]
    DIRECTION INPUT ;
    USE SIGNAL ;
    PORT
      LAYER M3 ;
        RECT  9.936 64.762 9.954 64.8 ;
    END
  END i[52]
  PIN i[53]
    DIRECTION INPUT ;
    USE SIGNAL ;
    PORT
      LAYER M5 ;
        RECT  10.128 64.716 10.152 64.8 ;
    END
  END i[53]
  PIN i[54]
    DIRECTION INPUT ;
    USE SIGNAL ;
    PORT
      LAYER M3 ;
        RECT  10.296 64.762 10.314 64.8 ;
    END
  END i[54]
  PIN i[55]
    DIRECTION INPUT ;
    USE SIGNAL ;
    PORT
      LAYER M5 ;
        RECT  10.464 64.716 10.488 64.8 ;
    END
  END i[55]
  PIN i[56]
    DIRECTION INPUT ;
    USE SIGNAL ;
    PORT
      LAYER M3 ;
        RECT  10.62 64.762 10.638 64.8 ;
    END
  END i[56]
  PIN i[57]
    DIRECTION INPUT ;
    USE SIGNAL ;
    PORT
      LAYER M5 ;
        RECT  10.8 64.716 10.824 64.8 ;
    END
  END i[57]
  PIN i[58]
    DIRECTION INPUT ;
    USE SIGNAL ;
    PORT
      LAYER M3 ;
        RECT  10.944 64.762 10.962 64.8 ;
    END
  END i[58]
  PIN i[59]
    DIRECTION INPUT ;
    USE SIGNAL ;
    PORT
      LAYER M5 ;
        RECT  11.136 64.716 11.16 64.8 ;
    END
  END i[59]
  PIN i[5]
    DIRECTION INPUT ;
    USE SIGNAL ;
    PORT
      LAYER M5 ;
        RECT  1.92 64.716 1.944 64.8 ;
    END
  END i[5]
  PIN i[60]
    DIRECTION INPUT ;
    USE SIGNAL ;
    PORT
      LAYER M3 ;
        RECT  11.304 64.762 11.322 64.8 ;
    END
  END i[60]
  PIN i[61]
    DIRECTION INPUT ;
    USE SIGNAL ;
    PORT
      LAYER M5 ;
        RECT  11.472 64.716 11.496 64.8 ;
    END
  END i[61]
  PIN i[62]
    DIRECTION INPUT ;
    USE SIGNAL ;
    PORT
      LAYER M3 ;
        RECT  11.628 64.762 11.646 64.8 ;
    END
  END i[62]
  PIN i[63]
    DIRECTION INPUT ;
    USE SIGNAL ;
    PORT
      LAYER M5 ;
        RECT  11.808 64.716 11.832 64.8 ;
    END
  END i[63]
  PIN i[64]
    DIRECTION INPUT ;
    USE SIGNAL ;
    PORT
      LAYER M3 ;
        RECT  11.988 64.762 12.006 64.8 ;
    END
  END i[64]
  PIN i[65]
    DIRECTION INPUT ;
    USE SIGNAL ;
    PORT
      LAYER M5 ;
        RECT  12.144 64.716 12.168 64.8 ;
    END
  END i[65]
  PIN i[66]
    DIRECTION INPUT ;
    USE SIGNAL ;
    PORT
      LAYER M3 ;
        RECT  12.312 64.762 12.33 64.8 ;
    END
  END i[66]
  PIN i[67]
    DIRECTION INPUT ;
    USE SIGNAL ;
    PORT
      LAYER M5 ;
        RECT  12.48 64.716 12.504 64.8 ;
    END
  END i[67]
  PIN i[68]
    DIRECTION INPUT ;
    USE SIGNAL ;
    PORT
      LAYER M3 ;
        RECT  12.672 64.762 12.69 64.8 ;
    END
  END i[68]
  PIN i[69]
    DIRECTION INPUT ;
    USE SIGNAL ;
    PORT
      LAYER M5 ;
        RECT  12.816 64.716 12.84 64.8 ;
    END
  END i[69]
  PIN i[6]
    DIRECTION INPUT ;
    USE SIGNAL ;
    PORT
      LAYER M3 ;
        RECT  2.088 64.762 2.106 64.8 ;
    END
  END i[6]
  PIN i[70]
    DIRECTION INPUT ;
    USE SIGNAL ;
    PORT
      LAYER M3 ;
        RECT  12.996 64.762 13.014 64.8 ;
    END
  END i[70]
  PIN i[71]
    DIRECTION INPUT ;
    USE SIGNAL ;
    PORT
      LAYER M5 ;
        RECT  13.152 64.716 13.176 64.8 ;
    END
  END i[71]
  PIN i[72]
    DIRECTION INPUT ;
    USE SIGNAL ;
    PORT
      LAYER M3 ;
        RECT  13.356 64.762 13.374 64.8 ;
    END
  END i[72]
  PIN i[73]
    DIRECTION INPUT ;
    USE SIGNAL ;
    PORT
      LAYER M5 ;
        RECT  13.536 64.716 13.56 64.8 ;
    END
  END i[73]
  PIN i[74]
    DIRECTION INPUT ;
    USE SIGNAL ;
    PORT
      LAYER M3 ;
        RECT  13.68 64.762 13.698 64.8 ;
    END
  END i[74]
  PIN i[75]
    DIRECTION INPUT ;
    USE SIGNAL ;
    PORT
      LAYER M5 ;
        RECT  13.872 64.716 13.896 64.8 ;
    END
  END i[75]
  PIN i[76]
    DIRECTION INPUT ;
    USE SIGNAL ;
    PORT
      LAYER M3 ;
        RECT  14.04 64.762 14.058 64.8 ;
    END
  END i[76]
  PIN i[77]
    DIRECTION INPUT ;
    USE SIGNAL ;
    PORT
      LAYER M5 ;
        RECT  14.208 64.716 14.232 64.8 ;
    END
  END i[77]
  PIN i[78]
    DIRECTION INPUT ;
    USE SIGNAL ;
    PORT
      LAYER M3 ;
        RECT  14.364 64.762 14.382 64.8 ;
    END
  END i[78]
  PIN i[79]
    DIRECTION INPUT ;
    USE SIGNAL ;
    PORT
      LAYER M5 ;
        RECT  14.544 64.716 14.568 64.8 ;
    END
  END i[79]
  PIN i[7]
    DIRECTION INPUT ;
    USE SIGNAL ;
    PORT
      LAYER M5 ;
        RECT  2.256 64.716 2.28 64.8 ;
    END
  END i[7]
  PIN i[80]
    DIRECTION INPUT ;
    USE SIGNAL ;
    PORT
      LAYER M3 ;
        RECT  14.724 64.762 14.742 64.8 ;
    END
  END i[80]
  PIN i[81]
    DIRECTION INPUT ;
    USE SIGNAL ;
    PORT
      LAYER M5 ;
        RECT  14.88 64.716 14.904 64.8 ;
    END
  END i[81]
  PIN i[82]
    DIRECTION INPUT ;
    USE SIGNAL ;
    PORT
      LAYER M3 ;
        RECT  15.048 64.762 15.066 64.8 ;
    END
  END i[82]
  PIN i[83]
    DIRECTION INPUT ;
    USE SIGNAL ;
    PORT
      LAYER M5 ;
        RECT  15.216 64.716 15.24 64.8 ;
    END
  END i[83]
  PIN i[84]
    DIRECTION INPUT ;
    USE SIGNAL ;
    PORT
      LAYER M3 ;
        RECT  15.408 64.762 15.426 64.8 ;
    END
  END i[84]
  PIN i[85]
    DIRECTION INPUT ;
    USE SIGNAL ;
    PORT
      LAYER M5 ;
        RECT  15.552 64.716 15.576 64.8 ;
    END
  END i[85]
  PIN i[86]
    DIRECTION INPUT ;
    USE SIGNAL ;
    PORT
      LAYER M3 ;
        RECT  15.732 64.762 15.75 64.8 ;
    END
  END i[86]
  PIN i[87]
    DIRECTION INPUT ;
    USE SIGNAL ;
    PORT
      LAYER M5 ;
        RECT  15.888 64.716 15.912 64.8 ;
    END
  END i[87]
  PIN i[88]
    DIRECTION INPUT ;
    USE SIGNAL ;
    PORT
      LAYER M3 ;
        RECT  16.092 64.762 16.11 64.8 ;
    END
  END i[88]
  PIN i[89]
    DIRECTION INPUT ;
    USE SIGNAL ;
    PORT
      LAYER M5 ;
        RECT  16.224 64.716 16.248 64.8 ;
    END
  END i[89]
  PIN i[8]
    DIRECTION INPUT ;
    USE SIGNAL ;
    PORT
      LAYER M3 ;
        RECT  2.448 64.762 2.466 64.8 ;
    END
  END i[8]
  PIN i[90]
    DIRECTION INPUT ;
    USE SIGNAL ;
    PORT
      LAYER M3 ;
        RECT  16.416 64.762 16.434 64.8 ;
    END
  END i[90]
  PIN i[91]
    DIRECTION INPUT ;
    USE SIGNAL ;
    PORT
      LAYER M5 ;
        RECT  16.56 64.716 16.584 64.8 ;
    END
  END i[91]
  PIN i[92]
    DIRECTION INPUT ;
    USE SIGNAL ;
    PORT
      LAYER M3 ;
        RECT  16.74 64.762 16.758 64.8 ;
    END
  END i[92]
  PIN i[93]
    DIRECTION INPUT ;
    USE SIGNAL ;
    PORT
      LAYER M5 ;
        RECT  16.944 64.716 16.968 64.8 ;
    END
  END i[93]
  PIN i[94]
    DIRECTION INPUT ;
    USE SIGNAL ;
    PORT
      LAYER M3 ;
        RECT  17.1 64.762 17.118 64.8 ;
    END
  END i[94]
  PIN i[95]
    DIRECTION INPUT ;
    USE SIGNAL ;
    PORT
      LAYER M5 ;
        RECT  17.28 64.716 17.304 64.8 ;
    END
  END i[95]
  PIN i[96]
    DIRECTION INPUT ;
    USE SIGNAL ;
    PORT
      LAYER M3 ;
        RECT  17.424 64.762 17.442 64.8 ;
    END
  END i[96]
  PIN i[97]
    DIRECTION INPUT ;
    USE SIGNAL ;
    PORT
      LAYER M5 ;
        RECT  17.616 64.716 17.64 64.8 ;
    END
  END i[97]
  PIN i[98]
    DIRECTION INPUT ;
    USE SIGNAL ;
    PORT
      LAYER M3 ;
        RECT  17.784 64.762 17.802 64.8 ;
    END
  END i[98]
  PIN i[99]
    DIRECTION INPUT ;
    USE SIGNAL ;
    PORT
      LAYER M5 ;
        RECT  17.952 64.716 17.976 64.8 ;
    END
  END i[99]
  PIN i[9]
    DIRECTION INPUT ;
    USE SIGNAL ;
    PORT
      LAYER M5 ;
        RECT  2.592 64.716 2.616 64.8 ;
    END
  END i[9]
  PIN k[0]
    DIRECTION INPUT ;
    USE SIGNAL ;
    PORT
      LAYER M4 ;
        RECT  51.756 31.488 51.84 31.512 ;
    END
  END k[0]
  PIN k[1]
    DIRECTION INPUT ;
    USE SIGNAL ;
    PORT
      LAYER M4 ;
        RECT  51.756 31.68 51.84 31.704 ;
    END
  END k[1]
  PIN k[2]
    DIRECTION INPUT ;
    USE SIGNAL ;
    PORT
      LAYER M4 ;
        RECT  51.756 31.872 51.84 31.896 ;
    END
  END k[2]
  PIN k[3]
    DIRECTION INPUT ;
    USE SIGNAL ;
    PORT
      LAYER M4 ;
        RECT  51.756 32.112 51.84 32.136 ;
    END
  END k[3]
  PIN k[4]
    DIRECTION INPUT ;
    USE SIGNAL ;
    PORT
      LAYER M4 ;
        RECT  51.756 32.304 51.84 32.328 ;
    END
  END k[4]
  PIN k[5]
    DIRECTION INPUT ;
    USE SIGNAL ;
    PORT
      LAYER M4 ;
        RECT  51.756 32.496 51.84 32.52 ;
    END
  END k[5]
  PIN o[0]
    DIRECTION OUTPUT ;
    USE SIGNAL ;
    PORT
      LAYER M3 ;
        RECT  1.08 0 1.098 0.038 ;
    END
  END o[0]
  PIN o[100]
    DIRECTION OUTPUT ;
    USE SIGNAL ;
    PORT
      LAYER M3 ;
        RECT  18.108 0 18.126 0.038 ;
    END
  END o[100]
  PIN o[101]
    DIRECTION OUTPUT ;
    USE SIGNAL ;
    PORT
      LAYER M5 ;
        RECT  18.288 0 18.312 0.084 ;
    END
  END o[101]
  PIN o[102]
    DIRECTION OUTPUT ;
    USE SIGNAL ;
    PORT
      LAYER M3 ;
        RECT  18.468 0 18.486 0.038 ;
    END
  END o[102]
  PIN o[103]
    DIRECTION OUTPUT ;
    USE SIGNAL ;
    PORT
      LAYER M5 ;
        RECT  18.624 0 18.648 0.084 ;
    END
  END o[103]
  PIN o[104]
    DIRECTION OUTPUT ;
    USE SIGNAL ;
    PORT
      LAYER M3 ;
        RECT  18.792 0 18.81 0.038 ;
    END
  END o[104]
  PIN o[105]
    DIRECTION OUTPUT ;
    USE SIGNAL ;
    PORT
      LAYER M5 ;
        RECT  18.96 0 18.984 0.084 ;
    END
  END o[105]
  PIN o[106]
    DIRECTION OUTPUT ;
    USE SIGNAL ;
    PORT
      LAYER M3 ;
        RECT  19.152 0 19.17 0.038 ;
    END
  END o[106]
  PIN o[107]
    DIRECTION OUTPUT ;
    USE SIGNAL ;
    PORT
      LAYER M5 ;
        RECT  19.296 0 19.32 0.084 ;
    END
  END o[107]
  PIN o[108]
    DIRECTION OUTPUT ;
    USE SIGNAL ;
    PORT
      LAYER M3 ;
        RECT  19.476 0 19.494 0.038 ;
    END
  END o[108]
  PIN o[109]
    DIRECTION OUTPUT ;
    USE SIGNAL ;
    PORT
      LAYER M5 ;
        RECT  19.632 0 19.656 0.084 ;
    END
  END o[109]
  PIN o[10]
    DIRECTION OUTPUT ;
    USE SIGNAL ;
    PORT
      LAYER M3 ;
        RECT  2.772 0 2.79 0.038 ;
    END
  END o[10]
  PIN o[110]
    DIRECTION OUTPUT ;
    USE SIGNAL ;
    PORT
      LAYER M3 ;
        RECT  19.836 0 19.854 0.038 ;
    END
  END o[110]
  PIN o[111]
    DIRECTION OUTPUT ;
    USE SIGNAL ;
    PORT
      LAYER M5 ;
        RECT  19.968 0 19.992 0.084 ;
    END
  END o[111]
  PIN o[112]
    DIRECTION OUTPUT ;
    USE SIGNAL ;
    PORT
      LAYER M3 ;
        RECT  20.16 0 20.178 0.038 ;
    END
  END o[112]
  PIN o[113]
    DIRECTION OUTPUT ;
    USE SIGNAL ;
    PORT
      LAYER M5 ;
        RECT  20.352 0 20.376 0.084 ;
    END
  END o[113]
  PIN o[114]
    DIRECTION OUTPUT ;
    USE SIGNAL ;
    PORT
      LAYER M3 ;
        RECT  20.52 0 20.538 0.038 ;
    END
  END o[114]
  PIN o[115]
    DIRECTION OUTPUT ;
    USE SIGNAL ;
    PORT
      LAYER M5 ;
        RECT  20.688 0 20.712 0.084 ;
    END
  END o[115]
  PIN o[116]
    DIRECTION OUTPUT ;
    USE SIGNAL ;
    PORT
      LAYER M3 ;
        RECT  20.844 0 20.862 0.038 ;
    END
  END o[116]
  PIN o[117]
    DIRECTION OUTPUT ;
    USE SIGNAL ;
    PORT
      LAYER M5 ;
        RECT  21.024 0 21.048 0.084 ;
    END
  END o[117]
  PIN o[118]
    DIRECTION OUTPUT ;
    USE SIGNAL ;
    PORT
      LAYER M3 ;
        RECT  21.204 0 21.222 0.038 ;
    END
  END o[118]
  PIN o[119]
    DIRECTION OUTPUT ;
    USE SIGNAL ;
    PORT
      LAYER M5 ;
        RECT  21.36 0 21.384 0.084 ;
    END
  END o[119]
  PIN o[11]
    DIRECTION OUTPUT ;
    USE SIGNAL ;
    PORT
      LAYER M5 ;
        RECT  2.928 0 2.952 0.084 ;
    END
  END o[11]
  PIN o[120]
    DIRECTION OUTPUT ;
    USE SIGNAL ;
    PORT
      LAYER M3 ;
        RECT  21.528 0 21.546 0.038 ;
    END
  END o[120]
  PIN o[121]
    DIRECTION OUTPUT ;
    USE SIGNAL ;
    PORT
      LAYER M5 ;
        RECT  21.696 0 21.72 0.084 ;
    END
  END o[121]
  PIN o[122]
    DIRECTION OUTPUT ;
    USE SIGNAL ;
    PORT
      LAYER M3 ;
        RECT  21.852 0 21.87 0.038 ;
    END
  END o[122]
  PIN o[123]
    DIRECTION OUTPUT ;
    USE SIGNAL ;
    PORT
      LAYER M5 ;
        RECT  22.032 0 22.056 0.084 ;
    END
  END o[123]
  PIN o[124]
    DIRECTION OUTPUT ;
    USE SIGNAL ;
    PORT
      LAYER M3 ;
        RECT  22.212 0 22.23 0.038 ;
    END
  END o[124]
  PIN o[125]
    DIRECTION OUTPUT ;
    USE SIGNAL ;
    PORT
      LAYER M5 ;
        RECT  22.368 0 22.392 0.084 ;
    END
  END o[125]
  PIN o[126]
    DIRECTION OUTPUT ;
    USE SIGNAL ;
    PORT
      LAYER M3 ;
        RECT  22.536 0 22.554 0.038 ;
    END
  END o[126]
  PIN o[127]
    DIRECTION OUTPUT ;
    USE SIGNAL ;
    PORT
      LAYER M5 ;
        RECT  22.704 0 22.728 0.084 ;
    END
  END o[127]
  PIN o[128]
    DIRECTION OUTPUT ;
    USE SIGNAL ;
    PORT
      LAYER M3 ;
        RECT  22.896 0 22.914 0.038 ;
    END
  END o[128]
  PIN o[129]
    DIRECTION OUTPUT ;
    USE SIGNAL ;
    PORT
      LAYER M5 ;
        RECT  23.04 0 23.064 0.084 ;
    END
  END o[129]
  PIN o[12]
    DIRECTION OUTPUT ;
    USE SIGNAL ;
    PORT
      LAYER M3 ;
        RECT  3.132 0 3.15 0.038 ;
    END
  END o[12]
  PIN o[130]
    DIRECTION OUTPUT ;
    USE SIGNAL ;
    PORT
      LAYER M3 ;
        RECT  23.22 0 23.238 0.038 ;
    END
  END o[130]
  PIN o[131]
    DIRECTION OUTPUT ;
    USE SIGNAL ;
    PORT
      LAYER M5 ;
        RECT  23.424 0 23.448 0.084 ;
    END
  END o[131]
  PIN o[132]
    DIRECTION OUTPUT ;
    USE SIGNAL ;
    PORT
      LAYER M3 ;
        RECT  23.58 0 23.598 0.038 ;
    END
  END o[132]
  PIN o[133]
    DIRECTION OUTPUT ;
    USE SIGNAL ;
    PORT
      LAYER M5 ;
        RECT  23.76 0 23.784 0.084 ;
    END
  END o[133]
  PIN o[134]
    DIRECTION OUTPUT ;
    USE SIGNAL ;
    PORT
      LAYER M3 ;
        RECT  23.904 0 23.922 0.038 ;
    END
  END o[134]
  PIN o[135]
    DIRECTION OUTPUT ;
    USE SIGNAL ;
    PORT
      LAYER M5 ;
        RECT  24.096 0 24.12 0.084 ;
    END
  END o[135]
  PIN o[136]
    DIRECTION OUTPUT ;
    USE SIGNAL ;
    PORT
      LAYER M3 ;
        RECT  24.264 0 24.282 0.038 ;
    END
  END o[136]
  PIN o[137]
    DIRECTION OUTPUT ;
    USE SIGNAL ;
    PORT
      LAYER M5 ;
        RECT  24.432 0 24.456 0.084 ;
    END
  END o[137]
  PIN o[138]
    DIRECTION OUTPUT ;
    USE SIGNAL ;
    PORT
      LAYER M3 ;
        RECT  24.588 0 24.606 0.038 ;
    END
  END o[138]
  PIN o[139]
    DIRECTION OUTPUT ;
    USE SIGNAL ;
    PORT
      LAYER M5 ;
        RECT  24.768 0 24.792 0.084 ;
    END
  END o[139]
  PIN o[13]
    DIRECTION OUTPUT ;
    USE SIGNAL ;
    PORT
      LAYER M5 ;
        RECT  3.312 0 3.336 0.084 ;
    END
  END o[13]
  PIN o[140]
    DIRECTION OUTPUT ;
    USE SIGNAL ;
    PORT
      LAYER M3 ;
        RECT  24.948 0 24.966 0.038 ;
    END
  END o[140]
  PIN o[141]
    DIRECTION OUTPUT ;
    USE SIGNAL ;
    PORT
      LAYER M5 ;
        RECT  25.104 0 25.128 0.084 ;
    END
  END o[141]
  PIN o[142]
    DIRECTION OUTPUT ;
    USE SIGNAL ;
    PORT
      LAYER M3 ;
        RECT  25.272 0 25.29 0.038 ;
    END
  END o[142]
  PIN o[143]
    DIRECTION OUTPUT ;
    USE SIGNAL ;
    PORT
      LAYER M5 ;
        RECT  25.44 0 25.464 0.084 ;
    END
  END o[143]
  PIN o[144]
    DIRECTION OUTPUT ;
    USE SIGNAL ;
    PORT
      LAYER M3 ;
        RECT  25.632 0 25.65 0.038 ;
    END
  END o[144]
  PIN o[145]
    DIRECTION OUTPUT ;
    USE SIGNAL ;
    PORT
      LAYER M5 ;
        RECT  25.776 0 25.8 0.084 ;
    END
  END o[145]
  PIN o[146]
    DIRECTION OUTPUT ;
    USE SIGNAL ;
    PORT
      LAYER M3 ;
        RECT  25.956 0 25.974 0.038 ;
    END
  END o[146]
  PIN o[147]
    DIRECTION OUTPUT ;
    USE SIGNAL ;
    PORT
      LAYER M5 ;
        RECT  26.112 0 26.136 0.084 ;
    END
  END o[147]
  PIN o[148]
    DIRECTION OUTPUT ;
    USE SIGNAL ;
    PORT
      LAYER M3 ;
        RECT  26.316 0 26.334 0.038 ;
    END
  END o[148]
  PIN o[149]
    DIRECTION OUTPUT ;
    USE SIGNAL ;
    PORT
      LAYER M5 ;
        RECT  26.448 0 26.472 0.084 ;
    END
  END o[149]
  PIN o[14]
    DIRECTION OUTPUT ;
    USE SIGNAL ;
    PORT
      LAYER M3 ;
        RECT  3.456 0 3.474 0.038 ;
    END
  END o[14]
  PIN o[150]
    DIRECTION OUTPUT ;
    USE SIGNAL ;
    PORT
      LAYER M3 ;
        RECT  26.64 0 26.658 0.038 ;
    END
  END o[150]
  PIN o[151]
    DIRECTION OUTPUT ;
    USE SIGNAL ;
    PORT
      LAYER M5 ;
        RECT  26.832 0 26.856 0.084 ;
    END
  END o[151]
  PIN o[152]
    DIRECTION OUTPUT ;
    USE SIGNAL ;
    PORT
      LAYER M3 ;
        RECT  27 0 27.018 0.038 ;
    END
  END o[152]
  PIN o[153]
    DIRECTION OUTPUT ;
    USE SIGNAL ;
    PORT
      LAYER M5 ;
        RECT  27.168 0 27.192 0.084 ;
    END
  END o[153]
  PIN o[154]
    DIRECTION OUTPUT ;
    USE SIGNAL ;
    PORT
      LAYER M3 ;
        RECT  27.324 0 27.342 0.038 ;
    END
  END o[154]
  PIN o[155]
    DIRECTION OUTPUT ;
    USE SIGNAL ;
    PORT
      LAYER M5 ;
        RECT  27.504 0 27.528 0.084 ;
    END
  END o[155]
  PIN o[156]
    DIRECTION OUTPUT ;
    USE SIGNAL ;
    PORT
      LAYER M3 ;
        RECT  27.648 0 27.666 0.038 ;
    END
  END o[156]
  PIN o[157]
    DIRECTION OUTPUT ;
    USE SIGNAL ;
    PORT
      LAYER M5 ;
        RECT  27.84 0 27.864 0.084 ;
    END
  END o[157]
  PIN o[158]
    DIRECTION OUTPUT ;
    USE SIGNAL ;
    PORT
      LAYER M3 ;
        RECT  28.008 0 28.026 0.038 ;
    END
  END o[158]
  PIN o[159]
    DIRECTION OUTPUT ;
    USE SIGNAL ;
    PORT
      LAYER M5 ;
        RECT  28.176 0 28.2 0.084 ;
    END
  END o[159]
  PIN o[15]
    DIRECTION OUTPUT ;
    USE SIGNAL ;
    PORT
      LAYER M5 ;
        RECT  3.648 0 3.672 0.084 ;
    END
  END o[15]
  PIN o[160]
    DIRECTION OUTPUT ;
    USE SIGNAL ;
    PORT
      LAYER M3 ;
        RECT  28.332 0 28.35 0.038 ;
    END
  END o[160]
  PIN o[161]
    DIRECTION OUTPUT ;
    USE SIGNAL ;
    PORT
      LAYER M5 ;
        RECT  28.512 0 28.536 0.084 ;
    END
  END o[161]
  PIN o[162]
    DIRECTION OUTPUT ;
    USE SIGNAL ;
    PORT
      LAYER M3 ;
        RECT  28.692 0 28.71 0.038 ;
    END
  END o[162]
  PIN o[163]
    DIRECTION OUTPUT ;
    USE SIGNAL ;
    PORT
      LAYER M5 ;
        RECT  28.848 0 28.872 0.084 ;
    END
  END o[163]
  PIN o[164]
    DIRECTION OUTPUT ;
    USE SIGNAL ;
    PORT
      LAYER M3 ;
        RECT  29.016 0 29.034 0.038 ;
    END
  END o[164]
  PIN o[165]
    DIRECTION OUTPUT ;
    USE SIGNAL ;
    PORT
      LAYER M5 ;
        RECT  29.184 0 29.208 0.084 ;
    END
  END o[165]
  PIN o[166]
    DIRECTION OUTPUT ;
    USE SIGNAL ;
    PORT
      LAYER M3 ;
        RECT  29.376 0 29.394 0.038 ;
    END
  END o[166]
  PIN o[167]
    DIRECTION OUTPUT ;
    USE SIGNAL ;
    PORT
      LAYER M5 ;
        RECT  29.52 0 29.544 0.084 ;
    END
  END o[167]
  PIN o[168]
    DIRECTION OUTPUT ;
    USE SIGNAL ;
    PORT
      LAYER M3 ;
        RECT  29.7 0 29.718 0.038 ;
    END
  END o[168]
  PIN o[169]
    DIRECTION OUTPUT ;
    USE SIGNAL ;
    PORT
      LAYER M5 ;
        RECT  29.856 0 29.88 0.084 ;
    END
  END o[169]
  PIN o[16]
    DIRECTION OUTPUT ;
    USE SIGNAL ;
    PORT
      LAYER M3 ;
        RECT  3.816 0 3.834 0.038 ;
    END
  END o[16]
  PIN o[170]
    DIRECTION OUTPUT ;
    USE SIGNAL ;
    PORT
      LAYER M3 ;
        RECT  30.06 0 30.078 0.038 ;
    END
  END o[170]
  PIN o[171]
    DIRECTION OUTPUT ;
    USE SIGNAL ;
    PORT
      LAYER M5 ;
        RECT  30.24 0 30.264 0.084 ;
    END
  END o[171]
  PIN o[172]
    DIRECTION OUTPUT ;
    USE SIGNAL ;
    PORT
      LAYER M3 ;
        RECT  30.384 0 30.402 0.038 ;
    END
  END o[172]
  PIN o[173]
    DIRECTION OUTPUT ;
    USE SIGNAL ;
    PORT
      LAYER M5 ;
        RECT  30.576 0 30.6 0.084 ;
    END
  END o[173]
  PIN o[174]
    DIRECTION OUTPUT ;
    USE SIGNAL ;
    PORT
      LAYER M3 ;
        RECT  30.744 0 30.762 0.038 ;
    END
  END o[174]
  PIN o[175]
    DIRECTION OUTPUT ;
    USE SIGNAL ;
    PORT
      LAYER M5 ;
        RECT  30.912 0 30.936 0.084 ;
    END
  END o[175]
  PIN o[176]
    DIRECTION OUTPUT ;
    USE SIGNAL ;
    PORT
      LAYER M3 ;
        RECT  31.068 0 31.086 0.038 ;
    END
  END o[176]
  PIN o[177]
    DIRECTION OUTPUT ;
    USE SIGNAL ;
    PORT
      LAYER M5 ;
        RECT  31.248 0 31.272 0.084 ;
    END
  END o[177]
  PIN o[178]
    DIRECTION OUTPUT ;
    USE SIGNAL ;
    PORT
      LAYER M3 ;
        RECT  31.428 0 31.446 0.038 ;
    END
  END o[178]
  PIN o[179]
    DIRECTION OUTPUT ;
    USE SIGNAL ;
    PORT
      LAYER M5 ;
        RECT  31.584 0 31.608 0.084 ;
    END
  END o[179]
  PIN o[17]
    DIRECTION OUTPUT ;
    USE SIGNAL ;
    PORT
      LAYER M5 ;
        RECT  3.984 0 4.008 0.084 ;
    END
  END o[17]
  PIN o[180]
    DIRECTION OUTPUT ;
    USE SIGNAL ;
    PORT
      LAYER M3 ;
        RECT  31.752 0 31.77 0.038 ;
    END
  END o[180]
  PIN o[181]
    DIRECTION OUTPUT ;
    USE SIGNAL ;
    PORT
      LAYER M5 ;
        RECT  31.92 0 31.944 0.084 ;
    END
  END o[181]
  PIN o[182]
    DIRECTION OUTPUT ;
    USE SIGNAL ;
    PORT
      LAYER M3 ;
        RECT  32.112 0 32.13 0.038 ;
    END
  END o[182]
  PIN o[183]
    DIRECTION OUTPUT ;
    USE SIGNAL ;
    PORT
      LAYER M5 ;
        RECT  32.256 0 32.28 0.084 ;
    END
  END o[183]
  PIN o[184]
    DIRECTION OUTPUT ;
    USE SIGNAL ;
    PORT
      LAYER M3 ;
        RECT  32.436 0 32.454 0.038 ;
    END
  END o[184]
  PIN o[185]
    DIRECTION OUTPUT ;
    USE SIGNAL ;
    PORT
      LAYER M5 ;
        RECT  32.592 0 32.616 0.084 ;
    END
  END o[185]
  PIN o[186]
    DIRECTION OUTPUT ;
    USE SIGNAL ;
    PORT
      LAYER M3 ;
        RECT  32.76 0 32.778 0.038 ;
    END
  END o[186]
  PIN o[187]
    DIRECTION OUTPUT ;
    USE SIGNAL ;
    PORT
      LAYER M5 ;
        RECT  32.928 0 32.952 0.084 ;
    END
  END o[187]
  PIN o[188]
    DIRECTION OUTPUT ;
    USE SIGNAL ;
    PORT
      LAYER M3 ;
        RECT  33.12 0 33.138 0.038 ;
    END
  END o[188]
  PIN o[189]
    DIRECTION OUTPUT ;
    USE SIGNAL ;
    PORT
      LAYER M5 ;
        RECT  33.264 0 33.288 0.084 ;
    END
  END o[189]
  PIN o[18]
    DIRECTION OUTPUT ;
    USE SIGNAL ;
    PORT
      LAYER M3 ;
        RECT  4.14 0 4.158 0.038 ;
    END
  END o[18]
  PIN o[190]
    DIRECTION OUTPUT ;
    USE SIGNAL ;
    PORT
      LAYER M3 ;
        RECT  33.444 0 33.462 0.038 ;
    END
  END o[190]
  PIN o[191]
    DIRECTION OUTPUT ;
    USE SIGNAL ;
    PORT
      LAYER M5 ;
        RECT  33.648 0 33.672 0.084 ;
    END
  END o[191]
  PIN o[192]
    DIRECTION OUTPUT ;
    USE SIGNAL ;
    PORT
      LAYER M3 ;
        RECT  33.804 0 33.822 0.038 ;
    END
  END o[192]
  PIN o[193]
    DIRECTION OUTPUT ;
    USE SIGNAL ;
    PORT
      LAYER M5 ;
        RECT  33.984 0 34.008 0.084 ;
    END
  END o[193]
  PIN o[194]
    DIRECTION OUTPUT ;
    USE SIGNAL ;
    PORT
      LAYER M3 ;
        RECT  34.128 0 34.146 0.038 ;
    END
  END o[194]
  PIN o[195]
    DIRECTION OUTPUT ;
    USE SIGNAL ;
    PORT
      LAYER M5 ;
        RECT  34.32 0 34.344 0.084 ;
    END
  END o[195]
  PIN o[196]
    DIRECTION OUTPUT ;
    USE SIGNAL ;
    PORT
      LAYER M3 ;
        RECT  34.488 0 34.506 0.038 ;
    END
  END o[196]
  PIN o[197]
    DIRECTION OUTPUT ;
    USE SIGNAL ;
    PORT
      LAYER M5 ;
        RECT  34.656 0 34.68 0.084 ;
    END
  END o[197]
  PIN o[198]
    DIRECTION OUTPUT ;
    USE SIGNAL ;
    PORT
      LAYER M3 ;
        RECT  34.812 0 34.83 0.038 ;
    END
  END o[198]
  PIN o[199]
    DIRECTION OUTPUT ;
    USE SIGNAL ;
    PORT
      LAYER M5 ;
        RECT  34.992 0 35.016 0.084 ;
    END
  END o[199]
  PIN o[19]
    DIRECTION OUTPUT ;
    USE SIGNAL ;
    PORT
      LAYER M5 ;
        RECT  4.32 0 4.344 0.084 ;
    END
  END o[19]
  PIN o[1]
    DIRECTION OUTPUT ;
    USE SIGNAL ;
    PORT
      LAYER M5 ;
        RECT  1.248 0 1.272 0.084 ;
    END
  END o[1]
  PIN o[200]
    DIRECTION OUTPUT ;
    USE SIGNAL ;
    PORT
      LAYER M3 ;
        RECT  35.172 0 35.19 0.038 ;
    END
  END o[200]
  PIN o[201]
    DIRECTION OUTPUT ;
    USE SIGNAL ;
    PORT
      LAYER M5 ;
        RECT  35.328 0 35.352 0.084 ;
    END
  END o[201]
  PIN o[202]
    DIRECTION OUTPUT ;
    USE SIGNAL ;
    PORT
      LAYER M3 ;
        RECT  35.496 0 35.514 0.038 ;
    END
  END o[202]
  PIN o[203]
    DIRECTION OUTPUT ;
    USE SIGNAL ;
    PORT
      LAYER M5 ;
        RECT  35.664 0 35.688 0.084 ;
    END
  END o[203]
  PIN o[204]
    DIRECTION OUTPUT ;
    USE SIGNAL ;
    PORT
      LAYER M3 ;
        RECT  35.856 0 35.874 0.038 ;
    END
  END o[204]
  PIN o[205]
    DIRECTION OUTPUT ;
    USE SIGNAL ;
    PORT
      LAYER M5 ;
        RECT  36 0 36.024 0.084 ;
    END
  END o[205]
  PIN o[206]
    DIRECTION OUTPUT ;
    USE SIGNAL ;
    PORT
      LAYER M3 ;
        RECT  36.18 0 36.198 0.038 ;
    END
  END o[206]
  PIN o[207]
    DIRECTION OUTPUT ;
    USE SIGNAL ;
    PORT
      LAYER M5 ;
        RECT  36.336 0 36.36 0.084 ;
    END
  END o[207]
  PIN o[208]
    DIRECTION OUTPUT ;
    USE SIGNAL ;
    PORT
      LAYER M3 ;
        RECT  36.54 0 36.558 0.038 ;
    END
  END o[208]
  PIN o[209]
    DIRECTION OUTPUT ;
    USE SIGNAL ;
    PORT
      LAYER M5 ;
        RECT  36.672 0 36.696 0.084 ;
    END
  END o[209]
  PIN o[20]
    DIRECTION OUTPUT ;
    USE SIGNAL ;
    PORT
      LAYER M3 ;
        RECT  4.5 0 4.518 0.038 ;
    END
  END o[20]
  PIN o[210]
    DIRECTION OUTPUT ;
    USE SIGNAL ;
    PORT
      LAYER M3 ;
        RECT  36.864 0 36.882 0.038 ;
    END
  END o[210]
  PIN o[211]
    DIRECTION OUTPUT ;
    USE SIGNAL ;
    PORT
      LAYER M5 ;
        RECT  37.056 0 37.08 0.084 ;
    END
  END o[211]
  PIN o[212]
    DIRECTION OUTPUT ;
    USE SIGNAL ;
    PORT
      LAYER M3 ;
        RECT  37.224 0 37.242 0.038 ;
    END
  END o[212]
  PIN o[213]
    DIRECTION OUTPUT ;
    USE SIGNAL ;
    PORT
      LAYER M5 ;
        RECT  37.392 0 37.416 0.084 ;
    END
  END o[213]
  PIN o[214]
    DIRECTION OUTPUT ;
    USE SIGNAL ;
    PORT
      LAYER M3 ;
        RECT  37.548 0 37.566 0.038 ;
    END
  END o[214]
  PIN o[215]
    DIRECTION OUTPUT ;
    USE SIGNAL ;
    PORT
      LAYER M5 ;
        RECT  37.728 0 37.752 0.084 ;
    END
  END o[215]
  PIN o[216]
    DIRECTION OUTPUT ;
    USE SIGNAL ;
    PORT
      LAYER M3 ;
        RECT  37.908 0 37.926 0.038 ;
    END
  END o[216]
  PIN o[217]
    DIRECTION OUTPUT ;
    USE SIGNAL ;
    PORT
      LAYER M5 ;
        RECT  38.064 0 38.088 0.084 ;
    END
  END o[217]
  PIN o[218]
    DIRECTION OUTPUT ;
    USE SIGNAL ;
    PORT
      LAYER M3 ;
        RECT  38.232 0 38.25 0.038 ;
    END
  END o[218]
  PIN o[219]
    DIRECTION OUTPUT ;
    USE SIGNAL ;
    PORT
      LAYER M5 ;
        RECT  38.4 0 38.424 0.084 ;
    END
  END o[219]
  PIN o[21]
    DIRECTION OUTPUT ;
    USE SIGNAL ;
    PORT
      LAYER M5 ;
        RECT  4.656 0 4.68 0.084 ;
    END
  END o[21]
  PIN o[220]
    DIRECTION OUTPUT ;
    USE SIGNAL ;
    PORT
      LAYER M3 ;
        RECT  38.556 0 38.574 0.038 ;
    END
  END o[220]
  PIN o[221]
    DIRECTION OUTPUT ;
    USE SIGNAL ;
    PORT
      LAYER M5 ;
        RECT  38.736 0 38.76 0.084 ;
    END
  END o[221]
  PIN o[222]
    DIRECTION OUTPUT ;
    USE SIGNAL ;
    PORT
      LAYER M3 ;
        RECT  38.916 0 38.934 0.038 ;
    END
  END o[222]
  PIN o[223]
    DIRECTION OUTPUT ;
    USE SIGNAL ;
    PORT
      LAYER M5 ;
        RECT  39.072 0 39.096 0.084 ;
    END
  END o[223]
  PIN o[224]
    DIRECTION OUTPUT ;
    USE SIGNAL ;
    PORT
      LAYER M3 ;
        RECT  39.24 0 39.258 0.038 ;
    END
  END o[224]
  PIN o[225]
    DIRECTION OUTPUT ;
    USE SIGNAL ;
    PORT
      LAYER M5 ;
        RECT  39.408 0 39.432 0.084 ;
    END
  END o[225]
  PIN o[226]
    DIRECTION OUTPUT ;
    USE SIGNAL ;
    PORT
      LAYER M3 ;
        RECT  39.6 0 39.618 0.038 ;
    END
  END o[226]
  PIN o[227]
    DIRECTION OUTPUT ;
    USE SIGNAL ;
    PORT
      LAYER M5 ;
        RECT  39.744 0 39.768 0.084 ;
    END
  END o[227]
  PIN o[228]
    DIRECTION OUTPUT ;
    USE SIGNAL ;
    PORT
      LAYER M3 ;
        RECT  39.924 0 39.942 0.038 ;
    END
  END o[228]
  PIN o[229]
    DIRECTION OUTPUT ;
    USE SIGNAL ;
    PORT
      LAYER M5 ;
        RECT  40.08 0 40.104 0.084 ;
    END
  END o[229]
  PIN o[22]
    DIRECTION OUTPUT ;
    USE SIGNAL ;
    PORT
      LAYER M3 ;
        RECT  4.824 0 4.842 0.038 ;
    END
  END o[22]
  PIN o[230]
    DIRECTION OUTPUT ;
    USE SIGNAL ;
    PORT
      LAYER M3 ;
        RECT  40.284 0 40.302 0.038 ;
    END
  END o[230]
  PIN o[231]
    DIRECTION OUTPUT ;
    USE SIGNAL ;
    PORT
      LAYER M5 ;
        RECT  40.464 0 40.488 0.084 ;
    END
  END o[231]
  PIN o[232]
    DIRECTION OUTPUT ;
    USE SIGNAL ;
    PORT
      LAYER M3 ;
        RECT  40.608 0 40.626 0.038 ;
    END
  END o[232]
  PIN o[233]
    DIRECTION OUTPUT ;
    USE SIGNAL ;
    PORT
      LAYER M5 ;
        RECT  40.8 0 40.824 0.084 ;
    END
  END o[233]
  PIN o[234]
    DIRECTION OUTPUT ;
    USE SIGNAL ;
    PORT
      LAYER M3 ;
        RECT  40.968 0 40.986 0.038 ;
    END
  END o[234]
  PIN o[235]
    DIRECTION OUTPUT ;
    USE SIGNAL ;
    PORT
      LAYER M5 ;
        RECT  41.136 0 41.16 0.084 ;
    END
  END o[235]
  PIN o[236]
    DIRECTION OUTPUT ;
    USE SIGNAL ;
    PORT
      LAYER M3 ;
        RECT  41.292 0 41.31 0.038 ;
    END
  END o[236]
  PIN o[237]
    DIRECTION OUTPUT ;
    USE SIGNAL ;
    PORT
      LAYER M5 ;
        RECT  41.472 0 41.496 0.084 ;
    END
  END o[237]
  PIN o[238]
    DIRECTION OUTPUT ;
    USE SIGNAL ;
    PORT
      LAYER M3 ;
        RECT  41.652 0 41.67 0.038 ;
    END
  END o[238]
  PIN o[239]
    DIRECTION OUTPUT ;
    USE SIGNAL ;
    PORT
      LAYER M5 ;
        RECT  41.808 0 41.832 0.084 ;
    END
  END o[239]
  PIN o[23]
    DIRECTION OUTPUT ;
    USE SIGNAL ;
    PORT
      LAYER M5 ;
        RECT  4.992 0 5.016 0.084 ;
    END
  END o[23]
  PIN o[240]
    DIRECTION OUTPUT ;
    USE SIGNAL ;
    PORT
      LAYER M3 ;
        RECT  41.976 0 41.994 0.038 ;
    END
  END o[240]
  PIN o[241]
    DIRECTION OUTPUT ;
    USE SIGNAL ;
    PORT
      LAYER M5 ;
        RECT  42.144 0 42.168 0.084 ;
    END
  END o[241]
  PIN o[242]
    DIRECTION OUTPUT ;
    USE SIGNAL ;
    PORT
      LAYER M3 ;
        RECT  42.336 0 42.354 0.038 ;
    END
  END o[242]
  PIN o[243]
    DIRECTION OUTPUT ;
    USE SIGNAL ;
    PORT
      LAYER M5 ;
        RECT  42.48 0 42.504 0.084 ;
    END
  END o[243]
  PIN o[244]
    DIRECTION OUTPUT ;
    USE SIGNAL ;
    PORT
      LAYER M3 ;
        RECT  42.66 0 42.678 0.038 ;
    END
  END o[244]
  PIN o[245]
    DIRECTION OUTPUT ;
    USE SIGNAL ;
    PORT
      LAYER M5 ;
        RECT  42.816 0 42.84 0.084 ;
    END
  END o[245]
  PIN o[246]
    DIRECTION OUTPUT ;
    USE SIGNAL ;
    PORT
      LAYER M3 ;
        RECT  43.02 0 43.038 0.038 ;
    END
  END o[246]
  PIN o[247]
    DIRECTION OUTPUT ;
    USE SIGNAL ;
    PORT
      LAYER M5 ;
        RECT  43.152 0 43.176 0.084 ;
    END
  END o[247]
  PIN o[248]
    DIRECTION OUTPUT ;
    USE SIGNAL ;
    PORT
      LAYER M3 ;
        RECT  43.344 0 43.362 0.038 ;
    END
  END o[248]
  PIN o[249]
    DIRECTION OUTPUT ;
    USE SIGNAL ;
    PORT
      LAYER M5 ;
        RECT  43.488 0 43.512 0.084 ;
    END
  END o[249]
  PIN o[24]
    DIRECTION OUTPUT ;
    USE SIGNAL ;
    PORT
      LAYER M3 ;
        RECT  5.184 0 5.202 0.038 ;
    END
  END o[24]
  PIN o[250]
    DIRECTION OUTPUT ;
    USE SIGNAL ;
    PORT
      LAYER M3 ;
        RECT  43.668 0 43.686 0.038 ;
    END
  END o[250]
  PIN o[251]
    DIRECTION OUTPUT ;
    USE SIGNAL ;
    PORT
      LAYER M5 ;
        RECT  43.872 0 43.896 0.084 ;
    END
  END o[251]
  PIN o[252]
    DIRECTION OUTPUT ;
    USE SIGNAL ;
    PORT
      LAYER M3 ;
        RECT  44.028 0 44.046 0.038 ;
    END
  END o[252]
  PIN o[253]
    DIRECTION OUTPUT ;
    USE SIGNAL ;
    PORT
      LAYER M5 ;
        RECT  44.208 0 44.232 0.084 ;
    END
  END o[253]
  PIN o[254]
    DIRECTION OUTPUT ;
    USE SIGNAL ;
    PORT
      LAYER M3 ;
        RECT  44.352 0 44.37 0.038 ;
    END
  END o[254]
  PIN o[255]
    DIRECTION OUTPUT ;
    USE SIGNAL ;
    PORT
      LAYER M5 ;
        RECT  44.544 0 44.568 0.084 ;
    END
  END o[255]
  PIN o[256]
    DIRECTION OUTPUT ;
    USE SIGNAL ;
    PORT
      LAYER M3 ;
        RECT  44.712 0 44.73 0.038 ;
    END
  END o[256]
  PIN o[257]
    DIRECTION OUTPUT ;
    USE SIGNAL ;
    PORT
      LAYER M5 ;
        RECT  44.88 0 44.904 0.084 ;
    END
  END o[257]
  PIN o[258]
    DIRECTION OUTPUT ;
    USE SIGNAL ;
    PORT
      LAYER M3 ;
        RECT  45.036 0 45.054 0.038 ;
    END
  END o[258]
  PIN o[259]
    DIRECTION OUTPUT ;
    USE SIGNAL ;
    PORT
      LAYER M5 ;
        RECT  45.216 0 45.24 0.084 ;
    END
  END o[259]
  PIN o[25]
    DIRECTION OUTPUT ;
    USE SIGNAL ;
    PORT
      LAYER M5 ;
        RECT  5.328 0 5.352 0.084 ;
    END
  END o[25]
  PIN o[260]
    DIRECTION OUTPUT ;
    USE SIGNAL ;
    PORT
      LAYER M3 ;
        RECT  45.396 0 45.414 0.038 ;
    END
  END o[260]
  PIN o[261]
    DIRECTION OUTPUT ;
    USE SIGNAL ;
    PORT
      LAYER M5 ;
        RECT  45.552 0 45.576 0.084 ;
    END
  END o[261]
  PIN o[262]
    DIRECTION OUTPUT ;
    USE SIGNAL ;
    PORT
      LAYER M3 ;
        RECT  45.72 0 45.738 0.038 ;
    END
  END o[262]
  PIN o[263]
    DIRECTION OUTPUT ;
    USE SIGNAL ;
    PORT
      LAYER M5 ;
        RECT  45.888 0 45.912 0.084 ;
    END
  END o[263]
  PIN o[264]
    DIRECTION OUTPUT ;
    USE SIGNAL ;
    PORT
      LAYER M3 ;
        RECT  46.08 0 46.098 0.038 ;
    END
  END o[264]
  PIN o[265]
    DIRECTION OUTPUT ;
    USE SIGNAL ;
    PORT
      LAYER M5 ;
        RECT  46.224 0 46.248 0.084 ;
    END
  END o[265]
  PIN o[266]
    DIRECTION OUTPUT ;
    USE SIGNAL ;
    PORT
      LAYER M3 ;
        RECT  46.404 0 46.422 0.038 ;
    END
  END o[266]
  PIN o[267]
    DIRECTION OUTPUT ;
    USE SIGNAL ;
    PORT
      LAYER M5 ;
        RECT  46.56 0 46.584 0.084 ;
    END
  END o[267]
  PIN o[268]
    DIRECTION OUTPUT ;
    USE SIGNAL ;
    PORT
      LAYER M3 ;
        RECT  46.764 0 46.782 0.038 ;
    END
  END o[268]
  PIN o[269]
    DIRECTION OUTPUT ;
    USE SIGNAL ;
    PORT
      LAYER M5 ;
        RECT  46.944 0 46.968 0.084 ;
    END
  END o[269]
  PIN o[26]
    DIRECTION OUTPUT ;
    USE SIGNAL ;
    PORT
      LAYER M3 ;
        RECT  5.508 0 5.526 0.038 ;
    END
  END o[26]
  PIN o[270]
    DIRECTION OUTPUT ;
    USE SIGNAL ;
    PORT
      LAYER M3 ;
        RECT  47.088 0 47.106 0.038 ;
    END
  END o[270]
  PIN o[271]
    DIRECTION OUTPUT ;
    USE SIGNAL ;
    PORT
      LAYER M5 ;
        RECT  47.28 0 47.304 0.084 ;
    END
  END o[271]
  PIN o[272]
    DIRECTION OUTPUT ;
    USE SIGNAL ;
    PORT
      LAYER M3 ;
        RECT  47.448 0 47.466 0.038 ;
    END
  END o[272]
  PIN o[273]
    DIRECTION OUTPUT ;
    USE SIGNAL ;
    PORT
      LAYER M5 ;
        RECT  47.616 0 47.64 0.084 ;
    END
  END o[273]
  PIN o[274]
    DIRECTION OUTPUT ;
    USE SIGNAL ;
    PORT
      LAYER M3 ;
        RECT  47.772 0 47.79 0.038 ;
    END
  END o[274]
  PIN o[275]
    DIRECTION OUTPUT ;
    USE SIGNAL ;
    PORT
      LAYER M5 ;
        RECT  47.952 0 47.976 0.084 ;
    END
  END o[275]
  PIN o[27]
    DIRECTION OUTPUT ;
    USE SIGNAL ;
    PORT
      LAYER M5 ;
        RECT  5.664 0 5.688 0.084 ;
    END
  END o[27]
  PIN o[28]
    DIRECTION OUTPUT ;
    USE SIGNAL ;
    PORT
      LAYER M3 ;
        RECT  5.832 0 5.85 0.038 ;
    END
  END o[28]
  PIN o[29]
    DIRECTION OUTPUT ;
    USE SIGNAL ;
    PORT
      LAYER M5 ;
        RECT  6 0 6.024 0.084 ;
    END
  END o[29]
  PIN o[2]
    DIRECTION OUTPUT ;
    USE SIGNAL ;
    PORT
      LAYER M3 ;
        RECT  1.404 0 1.422 0.038 ;
    END
  END o[2]
  PIN o[30]
    DIRECTION OUTPUT ;
    USE SIGNAL ;
    PORT
      LAYER M3 ;
        RECT  6.192 0 6.21 0.038 ;
    END
  END o[30]
  PIN o[31]
    DIRECTION OUTPUT ;
    USE SIGNAL ;
    PORT
      LAYER M5 ;
        RECT  6.336 0 6.36 0.084 ;
    END
  END o[31]
  PIN o[32]
    DIRECTION OUTPUT ;
    USE SIGNAL ;
    PORT
      LAYER M3 ;
        RECT  6.516 0 6.534 0.038 ;
    END
  END o[32]
  PIN o[33]
    DIRECTION OUTPUT ;
    USE SIGNAL ;
    PORT
      LAYER M5 ;
        RECT  6.72 0 6.744 0.084 ;
    END
  END o[33]
  PIN o[34]
    DIRECTION OUTPUT ;
    USE SIGNAL ;
    PORT
      LAYER M3 ;
        RECT  6.876 0 6.894 0.038 ;
    END
  END o[34]
  PIN o[35]
    DIRECTION OUTPUT ;
    USE SIGNAL ;
    PORT
      LAYER M5 ;
        RECT  7.056 0 7.08 0.084 ;
    END
  END o[35]
  PIN o[36]
    DIRECTION OUTPUT ;
    USE SIGNAL ;
    PORT
      LAYER M3 ;
        RECT  7.2 0 7.218 0.038 ;
    END
  END o[36]
  PIN o[37]
    DIRECTION OUTPUT ;
    USE SIGNAL ;
    PORT
      LAYER M5 ;
        RECT  7.392 0 7.416 0.084 ;
    END
  END o[37]
  PIN o[38]
    DIRECTION OUTPUT ;
    USE SIGNAL ;
    PORT
      LAYER M3 ;
        RECT  7.56 0 7.578 0.038 ;
    END
  END o[38]
  PIN o[39]
    DIRECTION OUTPUT ;
    USE SIGNAL ;
    PORT
      LAYER M5 ;
        RECT  7.728 0 7.752 0.084 ;
    END
  END o[39]
  PIN o[3]
    DIRECTION OUTPUT ;
    USE SIGNAL ;
    PORT
      LAYER M5 ;
        RECT  1.584 0 1.608 0.084 ;
    END
  END o[3]
  PIN o[40]
    DIRECTION OUTPUT ;
    USE SIGNAL ;
    PORT
      LAYER M3 ;
        RECT  7.884 0 7.902 0.038 ;
    END
  END o[40]
  PIN o[41]
    DIRECTION OUTPUT ;
    USE SIGNAL ;
    PORT
      LAYER M5 ;
        RECT  8.064 0 8.088 0.084 ;
    END
  END o[41]
  PIN o[42]
    DIRECTION OUTPUT ;
    USE SIGNAL ;
    PORT
      LAYER M3 ;
        RECT  8.244 0 8.262 0.038 ;
    END
  END o[42]
  PIN o[43]
    DIRECTION OUTPUT ;
    USE SIGNAL ;
    PORT
      LAYER M5 ;
        RECT  8.4 0 8.424 0.084 ;
    END
  END o[43]
  PIN o[44]
    DIRECTION OUTPUT ;
    USE SIGNAL ;
    PORT
      LAYER M3 ;
        RECT  8.568 0 8.586 0.038 ;
    END
  END o[44]
  PIN o[45]
    DIRECTION OUTPUT ;
    USE SIGNAL ;
    PORT
      LAYER M5 ;
        RECT  8.736 0 8.76 0.084 ;
    END
  END o[45]
  PIN o[46]
    DIRECTION OUTPUT ;
    USE SIGNAL ;
    PORT
      LAYER M3 ;
        RECT  8.928 0 8.946 0.038 ;
    END
  END o[46]
  PIN o[47]
    DIRECTION OUTPUT ;
    USE SIGNAL ;
    PORT
      LAYER M5 ;
        RECT  9.072 0 9.096 0.084 ;
    END
  END o[47]
  PIN o[48]
    DIRECTION OUTPUT ;
    USE SIGNAL ;
    PORT
      LAYER M3 ;
        RECT  9.252 0 9.27 0.038 ;
    END
  END o[48]
  PIN o[49]
    DIRECTION OUTPUT ;
    USE SIGNAL ;
    PORT
      LAYER M5 ;
        RECT  9.408 0 9.432 0.084 ;
    END
  END o[49]
  PIN o[4]
    DIRECTION OUTPUT ;
    USE SIGNAL ;
    PORT
      LAYER M3 ;
        RECT  1.764 0 1.782 0.038 ;
    END
  END o[4]
  PIN o[50]
    DIRECTION OUTPUT ;
    USE SIGNAL ;
    PORT
      LAYER M3 ;
        RECT  9.612 0 9.63 0.038 ;
    END
  END o[50]
  PIN o[51]
    DIRECTION OUTPUT ;
    USE SIGNAL ;
    PORT
      LAYER M5 ;
        RECT  9.744 0 9.768 0.084 ;
    END
  END o[51]
  PIN o[52]
    DIRECTION OUTPUT ;
    USE SIGNAL ;
    PORT
      LAYER M3 ;
        RECT  9.936 0 9.954 0.038 ;
    END
  END o[52]
  PIN o[53]
    DIRECTION OUTPUT ;
    USE SIGNAL ;
    PORT
      LAYER M5 ;
        RECT  10.128 0 10.152 0.084 ;
    END
  END o[53]
  PIN o[54]
    DIRECTION OUTPUT ;
    USE SIGNAL ;
    PORT
      LAYER M3 ;
        RECT  10.296 0 10.314 0.038 ;
    END
  END o[54]
  PIN o[55]
    DIRECTION OUTPUT ;
    USE SIGNAL ;
    PORT
      LAYER M5 ;
        RECT  10.464 0 10.488 0.084 ;
    END
  END o[55]
  PIN o[56]
    DIRECTION OUTPUT ;
    USE SIGNAL ;
    PORT
      LAYER M3 ;
        RECT  10.62 0 10.638 0.038 ;
    END
  END o[56]
  PIN o[57]
    DIRECTION OUTPUT ;
    USE SIGNAL ;
    PORT
      LAYER M5 ;
        RECT  10.8 0 10.824 0.084 ;
    END
  END o[57]
  PIN o[58]
    DIRECTION OUTPUT ;
    USE SIGNAL ;
    PORT
      LAYER M3 ;
        RECT  10.944 0 10.962 0.038 ;
    END
  END o[58]
  PIN o[59]
    DIRECTION OUTPUT ;
    USE SIGNAL ;
    PORT
      LAYER M5 ;
        RECT  11.136 0 11.16 0.084 ;
    END
  END o[59]
  PIN o[5]
    DIRECTION OUTPUT ;
    USE SIGNAL ;
    PORT
      LAYER M5 ;
        RECT  1.92 0 1.944 0.084 ;
    END
  END o[5]
  PIN o[60]
    DIRECTION OUTPUT ;
    USE SIGNAL ;
    PORT
      LAYER M3 ;
        RECT  11.304 0 11.322 0.038 ;
    END
  END o[60]
  PIN o[61]
    DIRECTION OUTPUT ;
    USE SIGNAL ;
    PORT
      LAYER M5 ;
        RECT  11.472 0 11.496 0.084 ;
    END
  END o[61]
  PIN o[62]
    DIRECTION OUTPUT ;
    USE SIGNAL ;
    PORT
      LAYER M3 ;
        RECT  11.628 0 11.646 0.038 ;
    END
  END o[62]
  PIN o[63]
    DIRECTION OUTPUT ;
    USE SIGNAL ;
    PORT
      LAYER M5 ;
        RECT  11.808 0 11.832 0.084 ;
    END
  END o[63]
  PIN o[64]
    DIRECTION OUTPUT ;
    USE SIGNAL ;
    PORT
      LAYER M3 ;
        RECT  11.988 0 12.006 0.038 ;
    END
  END o[64]
  PIN o[65]
    DIRECTION OUTPUT ;
    USE SIGNAL ;
    PORT
      LAYER M5 ;
        RECT  12.144 0 12.168 0.084 ;
    END
  END o[65]
  PIN o[66]
    DIRECTION OUTPUT ;
    USE SIGNAL ;
    PORT
      LAYER M3 ;
        RECT  12.312 0 12.33 0.038 ;
    END
  END o[66]
  PIN o[67]
    DIRECTION OUTPUT ;
    USE SIGNAL ;
    PORT
      LAYER M5 ;
        RECT  12.48 0 12.504 0.084 ;
    END
  END o[67]
  PIN o[68]
    DIRECTION OUTPUT ;
    USE SIGNAL ;
    PORT
      LAYER M3 ;
        RECT  12.672 0 12.69 0.038 ;
    END
  END o[68]
  PIN o[69]
    DIRECTION OUTPUT ;
    USE SIGNAL ;
    PORT
      LAYER M5 ;
        RECT  12.816 0 12.84 0.084 ;
    END
  END o[69]
  PIN o[6]
    DIRECTION OUTPUT ;
    USE SIGNAL ;
    PORT
      LAYER M3 ;
        RECT  2.088 0 2.106 0.038 ;
    END
  END o[6]
  PIN o[70]
    DIRECTION OUTPUT ;
    USE SIGNAL ;
    PORT
      LAYER M3 ;
        RECT  12.996 0 13.014 0.038 ;
    END
  END o[70]
  PIN o[71]
    DIRECTION OUTPUT ;
    USE SIGNAL ;
    PORT
      LAYER M5 ;
        RECT  13.152 0 13.176 0.084 ;
    END
  END o[71]
  PIN o[72]
    DIRECTION OUTPUT ;
    USE SIGNAL ;
    PORT
      LAYER M3 ;
        RECT  13.356 0 13.374 0.038 ;
    END
  END o[72]
  PIN o[73]
    DIRECTION OUTPUT ;
    USE SIGNAL ;
    PORT
      LAYER M5 ;
        RECT  13.536 0 13.56 0.084 ;
    END
  END o[73]
  PIN o[74]
    DIRECTION OUTPUT ;
    USE SIGNAL ;
    PORT
      LAYER M3 ;
        RECT  13.68 0 13.698 0.038 ;
    END
  END o[74]
  PIN o[75]
    DIRECTION OUTPUT ;
    USE SIGNAL ;
    PORT
      LAYER M5 ;
        RECT  13.872 0 13.896 0.084 ;
    END
  END o[75]
  PIN o[76]
    DIRECTION OUTPUT ;
    USE SIGNAL ;
    PORT
      LAYER M3 ;
        RECT  14.04 0 14.058 0.038 ;
    END
  END o[76]
  PIN o[77]
    DIRECTION OUTPUT ;
    USE SIGNAL ;
    PORT
      LAYER M5 ;
        RECT  14.208 0 14.232 0.084 ;
    END
  END o[77]
  PIN o[78]
    DIRECTION OUTPUT ;
    USE SIGNAL ;
    PORT
      LAYER M3 ;
        RECT  14.364 0 14.382 0.038 ;
    END
  END o[78]
  PIN o[79]
    DIRECTION OUTPUT ;
    USE SIGNAL ;
    PORT
      LAYER M5 ;
        RECT  14.544 0 14.568 0.084 ;
    END
  END o[79]
  PIN o[7]
    DIRECTION OUTPUT ;
    USE SIGNAL ;
    PORT
      LAYER M5 ;
        RECT  2.256 0 2.28 0.084 ;
    END
  END o[7]
  PIN o[80]
    DIRECTION OUTPUT ;
    USE SIGNAL ;
    PORT
      LAYER M3 ;
        RECT  14.724 0 14.742 0.038 ;
    END
  END o[80]
  PIN o[81]
    DIRECTION OUTPUT ;
    USE SIGNAL ;
    PORT
      LAYER M5 ;
        RECT  14.88 0 14.904 0.084 ;
    END
  END o[81]
  PIN o[82]
    DIRECTION OUTPUT ;
    USE SIGNAL ;
    PORT
      LAYER M3 ;
        RECT  15.048 0 15.066 0.038 ;
    END
  END o[82]
  PIN o[83]
    DIRECTION OUTPUT ;
    USE SIGNAL ;
    PORT
      LAYER M5 ;
        RECT  15.216 0 15.24 0.084 ;
    END
  END o[83]
  PIN o[84]
    DIRECTION OUTPUT ;
    USE SIGNAL ;
    PORT
      LAYER M3 ;
        RECT  15.408 0 15.426 0.038 ;
    END
  END o[84]
  PIN o[85]
    DIRECTION OUTPUT ;
    USE SIGNAL ;
    PORT
      LAYER M5 ;
        RECT  15.552 0 15.576 0.084 ;
    END
  END o[85]
  PIN o[86]
    DIRECTION OUTPUT ;
    USE SIGNAL ;
    PORT
      LAYER M3 ;
        RECT  15.732 0 15.75 0.038 ;
    END
  END o[86]
  PIN o[87]
    DIRECTION OUTPUT ;
    USE SIGNAL ;
    PORT
      LAYER M5 ;
        RECT  15.888 0 15.912 0.084 ;
    END
  END o[87]
  PIN o[88]
    DIRECTION OUTPUT ;
    USE SIGNAL ;
    PORT
      LAYER M3 ;
        RECT  16.092 0 16.11 0.038 ;
    END
  END o[88]
  PIN o[89]
    DIRECTION OUTPUT ;
    USE SIGNAL ;
    PORT
      LAYER M5 ;
        RECT  16.224 0 16.248 0.084 ;
    END
  END o[89]
  PIN o[8]
    DIRECTION OUTPUT ;
    USE SIGNAL ;
    PORT
      LAYER M3 ;
        RECT  2.448 0 2.466 0.038 ;
    END
  END o[8]
  PIN o[90]
    DIRECTION OUTPUT ;
    USE SIGNAL ;
    PORT
      LAYER M3 ;
        RECT  16.416 0 16.434 0.038 ;
    END
  END o[90]
  PIN o[91]
    DIRECTION OUTPUT ;
    USE SIGNAL ;
    PORT
      LAYER M5 ;
        RECT  16.56 0 16.584 0.084 ;
    END
  END o[91]
  PIN o[92]
    DIRECTION OUTPUT ;
    USE SIGNAL ;
    PORT
      LAYER M3 ;
        RECT  16.74 0 16.758 0.038 ;
    END
  END o[92]
  PIN o[93]
    DIRECTION OUTPUT ;
    USE SIGNAL ;
    PORT
      LAYER M5 ;
        RECT  16.944 0 16.968 0.084 ;
    END
  END o[93]
  PIN o[94]
    DIRECTION OUTPUT ;
    USE SIGNAL ;
    PORT
      LAYER M3 ;
        RECT  17.1 0 17.118 0.038 ;
    END
  END o[94]
  PIN o[95]
    DIRECTION OUTPUT ;
    USE SIGNAL ;
    PORT
      LAYER M5 ;
        RECT  17.28 0 17.304 0.084 ;
    END
  END o[95]
  PIN o[96]
    DIRECTION OUTPUT ;
    USE SIGNAL ;
    PORT
      LAYER M3 ;
        RECT  17.424 0 17.442 0.038 ;
    END
  END o[96]
  PIN o[97]
    DIRECTION OUTPUT ;
    USE SIGNAL ;
    PORT
      LAYER M5 ;
        RECT  17.616 0 17.64 0.084 ;
    END
  END o[97]
  PIN o[98]
    DIRECTION OUTPUT ;
    USE SIGNAL ;
    PORT
      LAYER M3 ;
        RECT  17.784 0 17.802 0.038 ;
    END
  END o[98]
  PIN o[99]
    DIRECTION OUTPUT ;
    USE SIGNAL ;
    PORT
      LAYER M5 ;
        RECT  17.952 0 17.976 0.084 ;
    END
  END o[99]
  PIN o[9]
    DIRECTION OUTPUT ;
    USE SIGNAL ;
    PORT
      LAYER M5 ;
        RECT  2.592 0 2.616 0.084 ;
    END
  END o[9]
  PIN rs
    DIRECTION INPUT ;
    USE SIGNAL ;
    PORT
      LAYER M4 ;
        RECT  51.756 33.312 51.84 33.336 ;
    END
  END rs
  PIN VDD
    DIRECTION INOUT ;
    USE POWER ;
    PORT
      LAYER M5 ;
        RECT  48.492 2.151 48.612 62.649 ;
        RECT  45.792 2.151 45.912 62.649 ;
        RECT  43.092 2.151 43.212 62.649 ;
        RECT  40.392 2.151 40.512 62.649 ;
        RECT  37.692 2.151 37.812 62.649 ;
        RECT  34.992 2.151 35.112 62.649 ;
        RECT  32.292 2.151 32.412 62.649 ;
        RECT  29.592 2.151 29.712 62.649 ;
        RECT  26.892 2.151 27.012 62.649 ;
        RECT  24.192 2.151 24.312 62.649 ;
        RECT  21.492 2.151 21.612 62.649 ;
        RECT  18.792 2.151 18.912 62.649 ;
        RECT  16.092 2.151 16.212 62.649 ;
        RECT  13.392 2.151 13.512 62.649 ;
        RECT  10.692 2.151 10.812 62.649 ;
        RECT  7.992 2.151 8.112 62.649 ;
        RECT  5.292 2.151 5.412 62.649 ;
        RECT  2.592 2.151 2.712 62.649 ;
    END
  END VDD
  PIN VSS
    DIRECTION INOUT ;
    USE GROUND ;
    PORT
      LAYER M5 ;
        RECT  48.3 2.137 48.42 62.663 ;
        RECT  45.6 2.137 45.72 62.663 ;
        RECT  42.9 2.137 43.02 62.663 ;
        RECT  40.2 2.137 40.32 62.663 ;
        RECT  37.5 2.137 37.62 62.663 ;
        RECT  34.8 2.137 34.92 62.663 ;
        RECT  32.1 2.137 32.22 62.663 ;
        RECT  29.4 2.137 29.52 62.663 ;
        RECT  26.7 2.137 26.82 62.663 ;
        RECT  24 2.137 24.12 62.663 ;
        RECT  21.3 2.137 21.42 62.663 ;
        RECT  18.6 2.137 18.72 62.663 ;
        RECT  15.9 2.137 16.02 62.663 ;
        RECT  13.2 2.137 13.32 62.663 ;
        RECT  10.5 2.137 10.62 62.663 ;
        RECT  7.8 2.137 7.92 62.663 ;
        RECT  5.1 2.137 5.22 62.663 ;
        RECT  2.4 2.137 2.52 62.663 ;
    END
  END VSS
  # OT_OBS_CLOSED layer=M5 d_um=1.536 added=133
  OBS
    LAYER RVTN ;
     RECT  2.16 2.16 49.68 2.295 ;
     RECT  2.16 2.565 49.68 2.835 ;
     RECT  2.16 3.105 49.68 3.375 ;
     RECT  2.16 3.645 49.68 3.915 ;
     RECT  2.16 4.185 49.68 4.455 ;
     RECT  2.16 4.725 49.68 4.995 ;
     RECT  2.16 5.265 49.68 5.535 ;
     RECT  2.16 5.805 49.68 6.075 ;
     RECT  2.16 6.345 49.68 6.615 ;
     RECT  2.16 6.885 49.68 7.155 ;
     RECT  2.16 7.425 49.68 7.695 ;
     RECT  2.16 7.965 49.68 8.235 ;
     RECT  2.16 8.505 49.68 8.775 ;
     RECT  2.16 9.045 49.68 9.315 ;
     RECT  2.16 9.585 49.68 9.855 ;
     RECT  2.16 10.125 49.68 10.395 ;
     RECT  2.16 10.665 49.68 10.935 ;
     RECT  2.16 11.205 49.68 11.475 ;
     RECT  2.16 11.745 49.68 12.015 ;
     RECT  2.16 12.285 49.68 12.555 ;
     RECT  2.16 12.825 49.68 13.095 ;
     RECT  2.16 13.365 49.68 13.635 ;
     RECT  2.16 13.905 49.68 14.175 ;
     RECT  2.16 14.445 49.68 14.715 ;
     RECT  2.16 14.985 49.68 15.255 ;
     RECT  2.16 15.525 49.68 15.795 ;
     RECT  2.16 16.065 49.68 16.335 ;
     RECT  2.16 16.605 49.68 16.875 ;
     RECT  2.16 17.145 49.68 17.415 ;
     RECT  2.16 17.685 49.68 17.955 ;
     RECT  2.16 18.225 49.68 18.495 ;
     RECT  2.16 18.765 49.68 19.035 ;
     RECT  2.16 19.305 49.68 19.575 ;
     RECT  2.16 19.845 49.68 20.115 ;
     RECT  2.16 20.385 49.68 20.655 ;
     RECT  2.16 20.925 49.68 21.195 ;
     RECT  2.16 21.465 49.68 21.735 ;
     RECT  2.16 22.005 49.68 22.275 ;
     RECT  2.16 22.545 49.68 22.815 ;
     RECT  2.16 23.085 49.68 23.355 ;
     RECT  2.16 23.625 49.68 23.895 ;
     RECT  2.16 24.165 49.68 24.435 ;
     RECT  2.16 24.705 49.68 24.975 ;
     RECT  2.16 25.245 49.68 25.515 ;
     RECT  2.16 25.785 49.68 26.055 ;
     RECT  2.16 26.325 49.68 26.595 ;
     RECT  2.16 26.865 49.68 27.135 ;
     RECT  2.16 27.405 49.68 27.675 ;
     RECT  2.16 27.945 49.68 28.215 ;
     RECT  2.16 28.485 49.68 28.755 ;
     RECT  2.16 29.025 49.68 29.295 ;
     RECT  2.16 29.565 49.68 29.835 ;
     RECT  2.16 30.105 49.68 30.375 ;
     RECT  2.16 30.645 49.68 30.915 ;
     RECT  2.16 31.185 49.68 31.455 ;
     RECT  2.16 31.725 49.68 31.995 ;
     RECT  2.16 32.265 49.68 32.535 ;
     RECT  2.16 32.805 49.68 33.075 ;
     RECT  2.16 33.345 49.68 33.615 ;
     RECT  2.16 33.885 49.68 34.155 ;
     RECT  2.16 34.425 49.68 34.695 ;
     RECT  2.16 34.965 49.68 35.235 ;
     RECT  2.16 35.505 49.68 35.775 ;
     RECT  2.16 36.045 49.68 36.315 ;
     RECT  2.16 36.585 49.68 36.855 ;
     RECT  2.16 37.125 49.68 37.395 ;
     RECT  2.16 37.665 49.68 37.935 ;
     RECT  2.16 38.205 49.68 38.475 ;
     RECT  2.16 38.745 49.68 39.015 ;
     RECT  2.16 39.285 49.68 39.555 ;
     RECT  2.16 39.825 49.68 40.095 ;
     RECT  2.16 40.365 49.68 40.635 ;
     RECT  2.16 40.905 49.68 41.175 ;
     RECT  2.16 41.445 49.68 41.715 ;
     RECT  2.16 41.985 49.68 42.255 ;
     RECT  2.16 42.525 49.68 42.795 ;
     RECT  2.16 43.065 49.68 43.335 ;
     RECT  2.16 43.605 49.68 43.875 ;
     RECT  2.16 44.145 49.68 44.415 ;
     RECT  2.16 44.685 49.68 44.955 ;
     RECT  2.16 45.225 49.68 45.495 ;
     RECT  2.16 45.765 49.68 46.035 ;
     RECT  2.16 46.305 49.68 46.575 ;
     RECT  2.16 46.845 49.68 47.115 ;
     RECT  2.16 47.385 49.68 47.655 ;
     RECT  2.16 47.925 49.68 48.195 ;
     RECT  2.16 48.465 49.68 48.735 ;
     RECT  2.16 49.005 49.68 49.275 ;
     RECT  2.16 49.545 49.68 49.815 ;
     RECT  2.16 50.085 49.68 50.355 ;
     RECT  2.16 50.625 49.68 50.895 ;
     RECT  2.16 51.165 49.68 51.435 ;
     RECT  2.16 51.705 49.68 51.975 ;
     RECT  2.16 52.245 49.68 52.515 ;
     RECT  2.16 52.785 49.68 53.055 ;
     RECT  2.16 53.325 49.68 53.595 ;
     RECT  2.16 53.865 49.68 54.135 ;
     RECT  2.16 54.405 49.68 54.675 ;
     RECT  2.16 54.945 49.68 55.215 ;
     RECT  2.16 55.485 49.68 55.755 ;
     RECT  2.16 56.025 49.68 56.295 ;
     RECT  2.16 56.565 49.68 56.835 ;
     RECT  2.16 57.105 49.68 57.375 ;
     RECT  2.16 57.645 49.68 57.915 ;
     RECT  2.16 58.185 49.68 58.455 ;
     RECT  2.16 58.725 49.68 58.995 ;
     RECT  2.16 59.265 49.68 59.535 ;
     RECT  2.16 59.805 49.68 60.075 ;
     RECT  2.16 60.345 49.68 60.615 ;
     RECT  2.16 60.885 49.68 61.155 ;
     RECT  2.16 61.425 49.68 61.695 ;
     RECT  2.16 61.965 49.68 62.235 ;
     RECT  2.16 62.505 49.68 62.64 ;
    LAYER RVTP ;
     RECT  2.16 2.295 49.68 2.565 ;
     RECT  2.16 2.835 49.68 3.105 ;
     RECT  2.16 3.375 49.68 3.645 ;
     RECT  2.16 3.915 49.68 4.185 ;
     RECT  2.16 4.455 49.68 4.725 ;
     RECT  2.16 4.995 49.68 5.265 ;
     RECT  2.16 5.535 49.68 5.805 ;
     RECT  2.16 6.075 49.68 6.345 ;
     RECT  2.16 6.615 49.68 6.885 ;
     RECT  2.16 7.155 49.68 7.425 ;
     RECT  2.16 7.695 49.68 7.965 ;
     RECT  2.16 8.235 49.68 8.505 ;
     RECT  2.16 8.775 49.68 9.045 ;
     RECT  2.16 9.315 49.68 9.585 ;
     RECT  2.16 9.855 49.68 10.125 ;
     RECT  2.16 10.395 49.68 10.665 ;
     RECT  2.16 10.935 49.68 11.205 ;
     RECT  2.16 11.475 49.68 11.745 ;
     RECT  2.16 12.015 49.68 12.285 ;
     RECT  2.16 12.555 49.68 12.825 ;
     RECT  2.16 13.095 49.68 13.365 ;
     RECT  2.16 13.635 49.68 13.905 ;
     RECT  2.16 14.175 49.68 14.445 ;
     RECT  2.16 14.715 49.68 14.985 ;
     RECT  2.16 15.255 49.68 15.525 ;
     RECT  2.16 15.795 49.68 16.065 ;
     RECT  2.16 16.335 49.68 16.605 ;
     RECT  2.16 16.875 49.68 17.145 ;
     RECT  2.16 17.415 49.68 17.685 ;
     RECT  2.16 17.955 49.68 18.225 ;
     RECT  2.16 18.495 49.68 18.765 ;
     RECT  2.16 19.035 49.68 19.305 ;
     RECT  2.16 19.575 49.68 19.845 ;
     RECT  2.16 20.115 49.68 20.385 ;
     RECT  2.16 20.655 49.68 20.925 ;
     RECT  2.16 21.195 49.68 21.465 ;
     RECT  2.16 21.735 49.68 22.005 ;
     RECT  2.16 22.275 49.68 22.545 ;
     RECT  2.16 22.815 49.68 23.085 ;
     RECT  2.16 23.355 49.68 23.625 ;
     RECT  2.16 23.895 49.68 24.165 ;
     RECT  2.16 24.435 49.68 24.705 ;
     RECT  2.16 24.975 49.68 25.245 ;
     RECT  2.16 25.515 49.68 25.785 ;
     RECT  2.16 26.055 49.68 26.325 ;
     RECT  2.16 26.595 49.68 26.865 ;
     RECT  2.16 27.135 49.68 27.405 ;
     RECT  2.16 27.675 49.68 27.945 ;
     RECT  2.16 28.215 49.68 28.485 ;
     RECT  2.16 28.755 49.68 29.025 ;
     RECT  2.16 29.295 49.68 29.565 ;
     RECT  2.16 29.835 49.68 30.105 ;
     RECT  2.16 30.375 49.68 30.645 ;
     RECT  2.16 30.915 49.68 31.185 ;
     RECT  2.16 31.455 49.68 31.725 ;
     RECT  2.16 31.995 49.68 32.265 ;
     RECT  2.16 32.535 49.68 32.805 ;
     RECT  2.16 33.075 49.68 33.345 ;
     RECT  2.16 33.615 49.68 33.885 ;
     RECT  2.16 34.155 49.68 34.425 ;
     RECT  2.16 34.695 49.68 34.965 ;
     RECT  2.16 35.235 49.68 35.505 ;
     RECT  2.16 35.775 49.68 36.045 ;
     RECT  2.16 36.315 49.68 36.585 ;
     RECT  2.16 36.855 49.68 37.125 ;
     RECT  2.16 37.395 49.68 37.665 ;
     RECT  2.16 37.935 49.68 38.205 ;
     RECT  2.16 38.475 49.68 38.745 ;
     RECT  2.16 39.015 49.68 39.285 ;
     RECT  2.16 39.555 49.68 39.825 ;
     RECT  2.16 40.095 49.68 40.365 ;
     RECT  2.16 40.635 49.68 40.905 ;
     RECT  2.16 41.175 49.68 41.445 ;
     RECT  2.16 41.715 49.68 41.985 ;
     RECT  2.16 42.255 49.68 42.525 ;
     RECT  2.16 42.795 49.68 43.065 ;
     RECT  2.16 43.335 49.68 43.605 ;
     RECT  2.16 43.875 49.68 44.145 ;
     RECT  2.16 44.415 49.68 44.685 ;
     RECT  2.16 44.955 49.68 45.225 ;
     RECT  2.16 45.495 49.68 45.765 ;
     RECT  2.16 46.035 49.68 46.305 ;
     RECT  2.16 46.575 49.68 46.845 ;
     RECT  2.16 47.115 49.68 47.385 ;
     RECT  2.16 47.655 49.68 47.925 ;
     RECT  2.16 48.195 49.68 48.465 ;
     RECT  2.16 48.735 49.68 49.005 ;
     RECT  2.16 49.275 49.68 49.545 ;
     RECT  2.16 49.815 49.68 50.085 ;
     RECT  2.16 50.355 49.68 50.625 ;
     RECT  2.16 50.895 49.68 51.165 ;
     RECT  2.16 51.435 49.68 51.705 ;
     RECT  2.16 51.975 49.68 52.245 ;
     RECT  2.16 52.515 49.68 52.785 ;
     RECT  2.16 53.055 49.68 53.325 ;
     RECT  2.16 53.595 49.68 53.865 ;
     RECT  2.16 54.135 49.68 54.405 ;
     RECT  2.16 54.675 49.68 54.945 ;
     RECT  2.16 55.215 49.68 55.485 ;
     RECT  2.16 55.755 49.68 56.025 ;
     RECT  2.16 56.295 49.68 56.565 ;
     RECT  2.16 56.835 49.68 57.105 ;
     RECT  2.16 57.375 49.68 57.645 ;
     RECT  2.16 57.915 49.68 58.185 ;
     RECT  2.16 58.455 49.68 58.725 ;
     RECT  2.16 58.995 49.68 59.265 ;
     RECT  2.16 59.535 49.68 59.805 ;
     RECT  2.16 60.075 49.68 60.345 ;
     RECT  2.16 60.615 49.68 60.885 ;
     RECT  2.16 61.155 49.68 61.425 ;
     RECT  2.16 61.695 49.68 61.965 ;
     RECT  2.16 62.235 49.68 62.505 ;
    LAYER M1 ;
     RECT  2.16 2.151 49.68 62.649 ;
    LAYER M2 ;
     RECT  1.399 0.261 1.759 0.279 ;
     RECT  1.075 27.72 1.759 27.738 ;
     RECT  1.759 0.18 2.083 0.279 ;
     RECT  1.075 5.778 2.16 5.796 ;
     RECT  1.759 27.72 2.16 27.9 ;
     RECT  1.399 33.048 2.16 33.066 ;
     RECT  2.083 45.27 2.16 45.288 ;
     RECT  2.16 2.151 2.299 62.649 ;
     RECT  2.299 2.151 2.335 62.73 ;
     RECT  2.083 0.036 2.443 0.279 ;
     RECT  2.335 2.151 2.471 62.766 ;
     RECT  2.443 0.036 3.803 0.324 ;
     RECT  3.803 0.036 4.819 0.279 ;
     RECT  2.471 2.151 5.071 62.73 ;
     RECT  4.819 0.036 5.251 0.549 ;
     RECT  5.251 0.036 5.539 1.17 ;
     RECT  5.071 2.106 5.603 62.73 ;
     RECT  5.539 0.036 5.639 1.242 ;
     RECT  5.603 2.106 5.755 62.649 ;
     RECT  5.639 0.036 5.963 0.504 ;
     RECT  5.963 0.036 6.215 0.09 ;
     RECT  6.583 1.152 6.719 1.17 ;
     RECT  5.755 2.034 7.151 62.649 ;
     RECT  6.215 0.036 7.771 0.054 ;
     RECT  8.131 1.152 8.167 1.17 ;
     RECT  7.771 0.036 8.239 0.09 ;
     RECT  8.167 1.152 8.267 1.242 ;
     RECT  8.267 1.224 8.411 1.242 ;
     RECT  7.151 2.106 8.447 62.649 ;
     RECT  8.447 2.151 9.247 62.649 ;
     RECT  9.247 1.728 9.527 62.649 ;
     RECT  8.239 0.036 9.607 0.126 ;
     RECT  9.607 0.036 9.967 0.198 ;
     RECT  9.967 0.036 10.319 0.234 ;
     RECT  10.319 0.036 10.427 0.198 ;
     RECT  10.615 63.864 11.363 63.882 ;
     RECT  9.527 2.106 11.939 62.649 ;
     RECT  10.427 0.036 11.983 0.054 ;
     RECT  11.983 0.036 12.307 0.09 ;
     RECT  12.307 0.036 12.587 0.126 ;
     RECT  12.587 0.036 13.675 0.054 ;
     RECT  13.675 0.036 13.775 0.09 ;
     RECT  13.775 0.036 13.955 0.054 ;
     RECT  11.939 2.151 14.359 62.649 ;
     RECT  14.359 1.728 14.747 62.649 ;
     RECT  14.719 0.18 15.043 0.198 ;
     RECT  14.747 2.106 15.323 62.649 ;
     RECT  15.043 0.036 15.727 0.198 ;
     RECT  15.323 2.151 15.835 62.649 ;
     RECT  15.727 0.036 16.259 0.549 ;
     RECT  16.259 0.036 16.475 0.126 ;
     RECT  15.835 2.151 17.015 62.694 ;
     RECT  16.475 0.036 17.419 0.054 ;
     RECT  17.419 0.036 17.735 0.09 ;
     RECT  17.735 0.036 18.787 0.054 ;
     RECT  17.015 2.151 18.931 62.649 ;
     RECT  18.787 0.036 19.175 0.126 ;
     RECT  18.931 2.106 20.047 62.649 ;
     RECT  19.175 0.036 20.435 0.054 ;
     RECT  20.047 2.034 20.983 62.649 ;
     RECT  20.983 2.034 21.047 62.802 ;
     RECT  21.047 2.151 21.551 62.802 ;
     RECT  21.551 2.151 21.847 62.649 ;
     RECT  21.847 2.106 22.307 62.649 ;
     RECT  21.523 0.036 23.575 0.054 ;
     RECT  23.575 0.036 24.179 0.549 ;
     RECT  22.307 2.151 24.259 62.649 ;
     RECT  24.259 2.151 24.547 62.73 ;
     RECT  24.547 2.034 24.647 62.73 ;
     RECT  24.179 0.036 25.763 0.198 ;
     RECT  24.647 2.034 26.275 62.649 ;
     RECT  25.763 0.108 26.635 0.198 ;
     RECT  26.635 0.108 27.131 0.549 ;
     RECT  27.131 0.108 27.319 0.198 ;
     RECT  27.319 0.036 27.671 0.198 ;
     RECT  26.275 1.962 28.003 62.649 ;
     RECT  28.003 1.728 28.463 62.649 ;
     RECT  28.463 2.106 28.687 62.649 ;
     RECT  28.687 2.106 28.823 62.694 ;
     RECT  27.671 0.036 29.011 0.054 ;
     RECT  29.011 0.036 29.795 0.549 ;
     RECT  29.795 0.036 30.371 0.162 ;
     RECT  28.823 2.106 30.551 62.649 ;
     RECT  30.371 0.036 31.451 0.126 ;
     RECT  30.551 2.151 31.495 62.649 ;
     RECT  31.451 0.036 31.523 0.054 ;
     RECT  31.495 2.106 31.747 62.649 ;
     RECT  31.747 2.034 32.035 62.649 ;
     RECT  32.035 2.034 32.107 62.73 ;
     RECT  32.107 1.962 32.567 62.73 ;
     RECT  32.567 2.106 32.747 62.73 ;
     RECT  32.747 2.106 33.439 62.649 ;
     RECT  32.431 0.036 34.015 0.054 ;
     RECT  34.015 0.036 34.151 0.09 ;
     RECT  33.439 2.034 34.187 62.649 ;
     RECT  33.079 1.152 34.403 1.17 ;
     RECT  34.187 2.151 34.807 62.649 ;
     RECT  34.807 2.151 34.979 62.73 ;
     RECT  34.151 0.036 35.167 0.054 ;
     RECT  35.491 1.152 35.591 1.242 ;
     RECT  34.979 2.151 35.635 62.649 ;
     RECT  35.591 1.152 36.635 1.17 ;
     RECT  35.167 0.036 36.779 0.126 ;
     RECT  35.635 2.106 36.859 62.649 ;
     RECT  36.859 2.034 37.435 62.649 ;
     RECT  36.779 0.036 37.543 0.054 ;
     RECT  37.435 2.034 37.571 62.73 ;
     RECT  37.543 0.036 37.903 0.09 ;
     RECT  37.571 2.034 38.471 62.649 ;
     RECT  37.903 0.036 38.579 0.162 ;
     RECT  38.579 0.036 38.687 0.054 ;
     RECT  38.471 2.106 39.047 62.649 ;
     RECT  39.595 0.036 39.919 0.054 ;
     RECT  39.919 0.036 40.603 0.126 ;
     RECT  41.143 1.152 41.459 1.17 ;
     RECT  42.187 1.224 42.223 1.242 ;
     RECT  42.223 1.152 42.323 1.242 ;
     RECT  40.603 0.036 42.683 0.198 ;
     RECT  39.047 2.151 42.871 62.649 ;
     RECT  42.683 0.036 42.899 0.126 ;
     RECT  42.871 2.151 43.043 62.73 ;
     RECT  43.043 2.151 43.123 62.649 ;
     RECT  42.899 0.036 43.663 0.054 ;
     RECT  43.123 2.034 44.023 62.649 ;
     RECT  44.023 1.728 44.123 62.649 ;
     RECT  43.663 0.036 44.707 0.09 ;
     RECT  44.123 2.034 44.951 62.649 ;
     RECT  44.671 1.152 45.023 1.17 ;
     RECT  44.951 2.106 45.067 62.649 ;
     RECT  45.067 2.106 45.715 62.694 ;
     RECT  45.715 2.106 45.751 62.73 ;
     RECT  44.707 0.036 46.075 0.126 ;
     RECT  46.075 0.036 46.247 0.198 ;
     RECT  46.247 0.108 46.319 0.198 ;
     RECT  45.751 2.034 46.399 62.73 ;
     RECT  46.399 1.728 46.535 62.73 ;
     RECT  46.535 2.034 46.571 62.73 ;
     RECT  46.571 2.034 46.895 62.694 ;
     RECT  46.895 2.151 46.967 62.694 ;
     RECT  46.319 0.18 47.003 0.198 ;
     RECT  47.083 0.036 47.767 0.054 ;
     RECT  47.767 0.036 48.011 0.126 ;
     RECT  48.011 0.108 48.263 0.126 ;
     RECT  46.967 2.151 49.68 62.649 ;
     RECT  49.68 23.094 49.955 23.112 ;
     RECT  49.68 28.26 50.459 28.278 ;
     RECT  49.68 33.318 51.755 33.336 ;
    LAYER M3 ;
     RECT  1.098 0.012 1.404 0.031 ;
     RECT  1.422 0.012 1.764 0.031 ;
     RECT  1.782 0.012 2.088 0.031 ;
     RECT  2.106 0.012 2.448 0.031 ;
     RECT  2.466 0.012 2.772 0.031 ;
     RECT  2.79 0.012 3.132 0.031 ;
     RECT  3.15 0.012 3.456 0.031 ;
     RECT  3.474 0.012 3.816 0.031 ;
     RECT  3.834 0.012 4.14 0.031 ;
     RECT  4.158 0.012 4.5 0.031 ;
     RECT  4.518 0.012 4.824 0.031 ;
     RECT  4.842 0.012 5.184 0.031 ;
     RECT  5.202 0.012 5.508 0.031 ;
     RECT  5.526 0.012 5.832 0.031 ;
     RECT  5.85 0.012 6.192 0.031 ;
     RECT  6.21 0.012 6.516 0.031 ;
     RECT  6.534 0.012 6.876 0.031 ;
     RECT  6.894 0.012 7.2 0.031 ;
     RECT  7.218 0.012 7.56 0.031 ;
     RECT  7.578 0.012 7.884 0.031 ;
     RECT  7.902 0.012 8.244 0.031 ;
     RECT  8.262 0.012 8.568 0.031 ;
     RECT  8.586 0.012 8.928 0.031 ;
     RECT  8.946 0.012 9.252 0.031 ;
     RECT  9.27 0.012 9.612 0.031 ;
     RECT  9.63 0.012 9.936 0.031 ;
     RECT  9.954 0.012 10.296 0.031 ;
     RECT  10.314 0.012 10.62 0.031 ;
     RECT  10.638 0.012 10.944 0.031 ;
     RECT  10.962 0.012 11.304 0.031 ;
     RECT  11.322 0.012 11.628 0.031 ;
     RECT  11.646 0.012 11.988 0.031 ;
     RECT  12.006 0.012 12.312 0.031 ;
     RECT  12.33 0.012 12.672 0.031 ;
     RECT  12.69 0.012 12.996 0.031 ;
     RECT  13.014 0.012 13.356 0.031 ;
     RECT  13.374 0.012 13.68 0.031 ;
     RECT  13.698 0.012 14.04 0.031 ;
     RECT  14.058 0.012 14.364 0.031 ;
     RECT  14.382 0.012 14.724 0.031 ;
     RECT  14.742 0.012 15.048 0.031 ;
     RECT  15.066 0.012 15.408 0.031 ;
     RECT  15.426 0.012 15.732 0.031 ;
     RECT  15.75 0.012 16.092 0.031 ;
     RECT  16.11 0.012 16.416 0.031 ;
     RECT  16.434 0.012 16.74 0.031 ;
     RECT  16.758 0.012 17.1 0.031 ;
     RECT  17.118 0.012 17.424 0.031 ;
     RECT  17.442 0.012 17.784 0.031 ;
     RECT  17.802 0.012 18.108 0.031 ;
     RECT  18.126 0.012 18.468 0.031 ;
     RECT  18.486 0.012 18.792 0.031 ;
     RECT  18.81 0.012 19.152 0.031 ;
     RECT  19.17 0.012 19.476 0.031 ;
     RECT  19.494 0.012 19.836 0.031 ;
     RECT  19.854 0.012 20.16 0.031 ;
     RECT  20.178 0.012 20.52 0.031 ;
     RECT  20.538 0.012 20.844 0.031 ;
     RECT  20.862 0.012 21.204 0.031 ;
     RECT  21.222 0.012 21.528 0.031 ;
     RECT  21.546 0.012 21.852 0.031 ;
     RECT  21.87 0.012 22.212 0.031 ;
     RECT  22.23 0.012 22.536 0.031 ;
     RECT  22.554 0.012 22.896 0.031 ;
     RECT  22.914 0.012 23.22 0.031 ;
     RECT  23.238 0.012 23.58 0.031 ;
     RECT  23.598 0.012 23.904 0.031 ;
     RECT  23.922 0.012 24.264 0.031 ;
     RECT  24.282 0.012 24.588 0.031 ;
     RECT  24.606 0.012 24.948 0.031 ;
     RECT  24.966 0.012 25.272 0.031 ;
     RECT  25.29 0.012 25.632 0.031 ;
     RECT  25.65 0.012 25.956 0.031 ;
     RECT  25.974 0.012 26.316 0.031 ;
     RECT  26.334 0.012 26.64 0.031 ;
     RECT  26.658 0.012 27 0.031 ;
     RECT  27.018 0.012 27.324 0.031 ;
     RECT  27.342 0.012 27.648 0.031 ;
     RECT  27.666 0.012 28.008 0.031 ;
     RECT  28.026 0.012 28.332 0.031 ;
     RECT  28.35 0.012 28.692 0.031 ;
     RECT  28.71 0.012 29.016 0.031 ;
     RECT  29.034 0.012 29.376 0.031 ;
     RECT  29.394 0.012 29.7 0.031 ;
     RECT  29.718 0.012 30.06 0.031 ;
     RECT  30.078 0.012 30.384 0.031 ;
     RECT  30.402 0.012 30.744 0.031 ;
     RECT  30.762 0.012 31.068 0.031 ;
     RECT  31.086 0.012 31.428 0.031 ;
     RECT  31.446 0.012 31.752 0.031 ;
     RECT  31.77 0.012 32.112 0.031 ;
     RECT  32.13 0.012 32.436 0.031 ;
     RECT  32.454 0.012 32.76 0.031 ;
     RECT  32.778 0.012 33.12 0.031 ;
     RECT  33.138 0.012 33.444 0.031 ;
     RECT  33.462 0.012 33.804 0.031 ;
     RECT  33.822 0.012 34.128 0.031 ;
     RECT  34.146 0.012 34.488 0.031 ;
     RECT  34.506 0.012 34.812 0.031 ;
     RECT  34.83 0.012 35.172 0.031 ;
     RECT  35.19 0.012 35.496 0.031 ;
     RECT  35.514 0.012 35.856 0.031 ;
     RECT  35.874 0.012 36.18 0.031 ;
     RECT  36.198 0.012 36.54 0.031 ;
     RECT  36.558 0.012 36.864 0.031 ;
     RECT  36.882 0.012 37.224 0.031 ;
     RECT  37.242 0.012 37.548 0.031 ;
     RECT  37.566 0.012 37.908 0.031 ;
     RECT  37.926 0.012 38.232 0.031 ;
     RECT  38.25 0.012 38.556 0.031 ;
     RECT  38.574 0.012 38.916 0.031 ;
     RECT  38.934 0.012 39.24 0.031 ;
     RECT  39.258 0.012 39.6 0.031 ;
     RECT  39.618 0.012 39.924 0.031 ;
     RECT  39.942 0.012 40.284 0.031 ;
     RECT  40.302 0.012 40.608 0.031 ;
     RECT  40.626 0.012 40.968 0.031 ;
     RECT  40.986 0.012 41.292 0.031 ;
     RECT  41.31 0.012 41.652 0.031 ;
     RECT  41.67 0.012 41.976 0.031 ;
     RECT  41.994 0.012 42.336 0.031 ;
     RECT  42.354 0.012 42.66 0.031 ;
     RECT  42.678 0.012 43.02 0.031 ;
     RECT  43.038 0.012 43.344 0.031 ;
     RECT  43.362 0.012 43.668 0.031 ;
     RECT  43.686 0.012 44.028 0.031 ;
     RECT  44.046 0.012 44.352 0.031 ;
     RECT  44.37 0.012 44.712 0.031 ;
     RECT  44.73 0.012 45.036 0.031 ;
     RECT  45.054 0.012 45.396 0.031 ;
     RECT  45.414 0.012 45.72 0.031 ;
     RECT  45.738 0.012 46.08 0.031 ;
     RECT  46.098 0.012 46.404 0.031 ;
     RECT  46.422 0.012 46.764 0.031 ;
     RECT  46.782 0.012 47.088 0.031 ;
     RECT  47.106 0.012 47.448 0.031 ;
     RECT  47.466 0.012 47.772 0.031 ;
     RECT  1.098 0.031 1.404 0.038 ;
     RECT  1.422 0.031 1.764 0.038 ;
     RECT  1.782 0.031 2.088 0.038 ;
     RECT  2.106 0.031 2.448 0.038 ;
     RECT  2.466 0.031 2.772 0.038 ;
     RECT  2.79 0.031 3.132 0.038 ;
     RECT  3.15 0.031 3.456 0.038 ;
     RECT  3.474 0.031 3.816 0.038 ;
     RECT  3.834 0.031 4.14 0.038 ;
     RECT  4.158 0.031 4.5 0.038 ;
     RECT  4.518 0.031 4.824 0.038 ;
     RECT  4.842 0.031 5.184 0.038 ;
     RECT  5.202 0.031 5.508 0.038 ;
     RECT  5.526 0.031 5.832 0.038 ;
     RECT  5.85 0.031 6.192 0.038 ;
     RECT  6.21 0.031 6.516 0.038 ;
     RECT  6.534 0.031 6.876 0.038 ;
     RECT  6.894 0.031 7.2 0.038 ;
     RECT  7.218 0.031 7.56 0.038 ;
     RECT  7.578 0.031 7.884 0.038 ;
     RECT  7.902 0.031 8.244 0.038 ;
     RECT  8.262 0.031 8.568 0.038 ;
     RECT  8.586 0.031 8.928 0.038 ;
     RECT  8.946 0.031 9.252 0.038 ;
     RECT  9.27 0.031 9.612 0.038 ;
     RECT  9.63 0.031 9.936 0.038 ;
     RECT  9.954 0.031 10.296 0.038 ;
     RECT  10.314 0.031 10.62 0.038 ;
     RECT  10.638 0.031 10.944 0.038 ;
     RECT  10.962 0.031 11.304 0.038 ;
     RECT  11.322 0.031 11.628 0.038 ;
     RECT  11.646 0.031 11.988 0.038 ;
     RECT  12.006 0.031 12.312 0.038 ;
     RECT  12.33 0.031 12.672 0.038 ;
     RECT  12.69 0.031 12.996 0.038 ;
     RECT  13.014 0.031 13.356 0.038 ;
     RECT  13.374 0.031 13.68 0.038 ;
     RECT  13.698 0.031 14.04 0.038 ;
     RECT  14.058 0.031 14.364 0.038 ;
     RECT  14.382 0.031 14.724 0.038 ;
     RECT  14.742 0.031 15.048 0.038 ;
     RECT  15.066 0.031 15.408 0.038 ;
     RECT  15.426 0.031 15.732 0.038 ;
     RECT  15.75 0.031 16.092 0.038 ;
     RECT  16.11 0.031 16.416 0.038 ;
     RECT  16.434 0.031 16.74 0.038 ;
     RECT  16.758 0.031 17.1 0.038 ;
     RECT  17.118 0.031 17.424 0.038 ;
     RECT  17.442 0.031 17.784 0.038 ;
     RECT  17.802 0.031 18.108 0.038 ;
     RECT  18.126 0.031 18.468 0.038 ;
     RECT  18.486 0.031 18.792 0.038 ;
     RECT  18.81 0.031 19.152 0.038 ;
     RECT  19.17 0.031 19.476 0.038 ;
     RECT  19.494 0.031 19.836 0.038 ;
     RECT  19.854 0.031 20.16 0.038 ;
     RECT  20.178 0.031 20.52 0.038 ;
     RECT  20.538 0.031 20.844 0.038 ;
     RECT  20.862 0.031 21.204 0.038 ;
     RECT  21.222 0.031 21.528 0.038 ;
     RECT  21.546 0.031 21.852 0.038 ;
     RECT  21.87 0.031 22.212 0.038 ;
     RECT  22.23 0.031 22.536 0.038 ;
     RECT  22.554 0.031 22.896 0.038 ;
     RECT  22.914 0.031 23.22 0.038 ;
     RECT  23.238 0.031 23.58 0.038 ;
     RECT  23.598 0.031 23.904 0.038 ;
     RECT  23.922 0.031 24.264 0.038 ;
     RECT  24.282 0.031 24.588 0.038 ;
     RECT  24.606 0.031 24.948 0.038 ;
     RECT  24.966 0.031 25.272 0.038 ;
     RECT  25.29 0.031 25.632 0.038 ;
     RECT  25.65 0.031 25.956 0.038 ;
     RECT  25.974 0.031 26.316 0.038 ;
     RECT  26.334 0.031 26.64 0.038 ;
     RECT  26.658 0.031 27 0.038 ;
     RECT  27.018 0.031 27.324 0.038 ;
     RECT  27.342 0.031 27.648 0.038 ;
     RECT  27.666 0.031 28.008 0.038 ;
     RECT  28.026 0.031 28.332 0.038 ;
     RECT  28.35 0.031 28.692 0.038 ;
     RECT  28.71 0.031 29.016 0.038 ;
     RECT  29.034 0.031 29.376 0.038 ;
     RECT  29.394 0.031 29.7 0.038 ;
     RECT  29.718 0.031 30.06 0.038 ;
     RECT  30.078 0.031 30.384 0.038 ;
     RECT  30.402 0.031 30.744 0.038 ;
     RECT  30.762 0.031 31.068 0.038 ;
     RECT  31.086 0.031 31.428 0.038 ;
     RECT  31.446 0.031 31.752 0.038 ;
     RECT  31.77 0.031 32.112 0.038 ;
     RECT  32.13 0.031 32.436 0.038 ;
     RECT  32.454 0.031 32.76 0.038 ;
     RECT  32.778 0.031 33.12 0.038 ;
     RECT  33.138 0.031 33.444 0.038 ;
     RECT  33.462 0.031 33.804 0.038 ;
     RECT  33.822 0.031 34.128 0.038 ;
     RECT  34.146 0.031 34.488 0.038 ;
     RECT  34.506 0.031 34.812 0.038 ;
     RECT  34.83 0.031 35.172 0.038 ;
     RECT  35.19 0.031 35.496 0.038 ;
     RECT  35.514 0.031 35.856 0.038 ;
     RECT  35.874 0.031 36.18 0.038 ;
     RECT  36.198 0.031 36.54 0.038 ;
     RECT  36.558 0.031 36.864 0.038 ;
     RECT  36.882 0.031 37.224 0.038 ;
     RECT  37.242 0.031 37.548 0.038 ;
     RECT  37.566 0.031 37.908 0.038 ;
     RECT  37.926 0.031 38.232 0.038 ;
     RECT  38.25 0.031 38.556 0.038 ;
     RECT  38.574 0.031 38.916 0.038 ;
     RECT  38.934 0.031 39.24 0.038 ;
     RECT  39.258 0.031 39.6 0.038 ;
     RECT  39.618 0.031 39.924 0.038 ;
     RECT  39.942 0.031 40.284 0.038 ;
     RECT  40.302 0.031 40.608 0.038 ;
     RECT  40.626 0.031 40.968 0.038 ;
     RECT  40.986 0.031 41.292 0.038 ;
     RECT  41.31 0.031 41.652 0.038 ;
     RECT  41.67 0.031 41.976 0.038 ;
     RECT  41.994 0.031 42.336 0.038 ;
     RECT  42.354 0.031 42.66 0.038 ;
     RECT  42.678 0.031 43.02 0.038 ;
     RECT  43.038 0.031 43.344 0.038 ;
     RECT  43.362 0.031 43.668 0.038 ;
     RECT  43.686 0.031 44.028 0.038 ;
     RECT  44.046 0.031 44.352 0.038 ;
     RECT  44.37 0.031 44.712 0.038 ;
     RECT  44.73 0.031 45.036 0.038 ;
     RECT  45.054 0.031 45.396 0.038 ;
     RECT  45.414 0.031 45.72 0.038 ;
     RECT  45.738 0.031 46.08 0.038 ;
     RECT  46.098 0.031 46.404 0.038 ;
     RECT  46.422 0.031 46.764 0.038 ;
     RECT  46.782 0.031 47.088 0.038 ;
     RECT  47.106 0.031 47.448 0.038 ;
     RECT  47.466 0.031 47.772 0.038 ;
     RECT  47.79 0.031 48.006 0.038 ;
     RECT  1.08 0.038 48.006 0.103 ;
     RECT  48.924 0.091 49.05 0.103 ;
     RECT  1.08 0.103 49.05 0.131 ;
     RECT  1.08 0.131 34.506 0.203 ;
     RECT  1.08 0.203 1.422 0.284 ;
     RECT  2.304 0.203 34.506 2.143 ;
     RECT  35.352 0.131 49.05 2.143 ;
     RECT  2.304 2.143 49.05 2.371 ;
     RECT  2.304 2.371 49.95 4.919 ;
     RECT  1.08 0.284 1.098 5.801 ;
     RECT  2.34 4.919 49.95 6.007 ;
     RECT  2.304 6.007 49.95 6.269 ;
     RECT  2.34 6.269 49.95 8.005 ;
     RECT  2.304 8.005 49.95 23.117 ;
     RECT  2.304 23.117 49.554 23.279 ;
     RECT  2.304 23.279 49.266 23.791 ;
     RECT  2.232 23.791 49.266 23.891 ;
     RECT  2.304 23.891 49.266 24.475 ;
     RECT  2.304 24.475 49.554 25.169 ;
     RECT  2.304 25.169 49.446 27.301 ;
     RECT  1.08 27.715 1.098 27.877 ;
     RECT  2.304 27.301 49.482 27.877 ;
     RECT  1.08 27.877 49.482 30.029 ;
     RECT  1.08 30.029 49.41 31.757 ;
     RECT  28.872 31.757 49.41 31.801 ;
     RECT  50.436 28.255 50.454 32.141 ;
     RECT  28.872 31.801 49.482 32.225 ;
     RECT  28.872 32.225 49.41 32.333 ;
     RECT  28.872 32.333 49.338 32.701 ;
     RECT  28.836 32.701 49.338 32.765 ;
     RECT  1.08 31.757 28.098 33.007 ;
     RECT  28.836 32.765 49.302 33.007 ;
     RECT  51.732 33.304 51.75 33.341 ;
     RECT  1.08 33.007 49.302 33.539 ;
     RECT  1.08 33.539 49.194 33.575 ;
     RECT  1.08 33.575 49.158 33.809 ;
     RECT  1.08 33.809 49.086 34.771 ;
     RECT  1.08 34.771 49.266 35.311 ;
     RECT  1.08 35.311 49.554 36.041 ;
     RECT  1.08 36.041 49.122 36.931 ;
     RECT  1.08 36.931 49.338 38.137 ;
     RECT  1.08 38.137 49.482 38.399 ;
     RECT  1.08 38.399 49.338 38.435 ;
     RECT  1.08 38.435 49.302 38.543 ;
     RECT  1.08 38.543 49.122 39.289 ;
     RECT  1.08 39.289 49.338 40.019 ;
     RECT  1.08 40.019 49.086 41.485 ;
     RECT  1.08 41.485 49.122 41.917 ;
     RECT  1.08 41.917 49.482 42.449 ;
     RECT  1.08 42.449 49.338 42.485 ;
     RECT  1.08 42.485 49.302 43.681 ;
     RECT  1.08 43.681 49.482 43.835 ;
     RECT  1.08 43.835 49.194 44.581 ;
     RECT  1.08 44.581 49.41 44.725 ;
     RECT  1.08 44.725 49.482 45.149 ;
     RECT  1.08 45.149 49.338 45.185 ;
     RECT  1.08 45.185 49.014 47.191 ;
     RECT  1.08 47.191 49.338 47.425 ;
     RECT  1.08 47.425 49.482 47.579 ;
     RECT  1.08 47.579 49.338 48.505 ;
     RECT  1.08 48.505 49.482 50.315 ;
     RECT  1.08 50.315 49.338 51.205 ;
     RECT  1.08 51.205 49.482 52.285 ;
     RECT  1.08 52.285 49.554 52.709 ;
     RECT  1.08 52.709 49.374 53.563 ;
     RECT  1.08 53.563 49.41 53.671 ;
     RECT  1.08 53.671 49.482 54.095 ;
     RECT  1.08 54.095 49.41 54.985 ;
     RECT  1.08 54.985 49.482 55.949 ;
     RECT  1.08 55.949 49.338 55.985 ;
     RECT  1.08 55.985 49.158 56.057 ;
     RECT  1.08 56.057 49.014 57.181 ;
     RECT  1.08 57.181 49.338 57.335 ;
     RECT  1.08 57.335 49.266 57.875 ;
     RECT  1.08 57.875 49.158 58.801 ;
     RECT  1.08 58.801 49.338 59.071 ;
     RECT  1.08 59.071 49.482 59.225 ;
     RECT  1.08 59.225 49.266 59.495 ;
     RECT  1.08 59.495 48.762 60.241 ;
     RECT  1.08 60.241 49.086 60.341 ;
     RECT  1.08 60.341 49.05 60.539 ;
     RECT  1.08 60.539 48.654 60.809 ;
     RECT  1.08 60.809 48.597 62.387 ;
     RECT  1.08 62.387 48.405 62.609 ;
     RECT  1.08 62.609 32.778 62.657 ;
     RECT  33.624 62.609 48.405 62.657 ;
     RECT  1.08 62.657 15.858 62.699 ;
     RECT  1.08 62.699 15.822 62.813 ;
     RECT  1.08 62.813 15.75 63.835 ;
     RECT  16.596 62.657 32.778 63.835 ;
     RECT  33.624 62.657 39.942 63.835 ;
     RECT  40.896 62.657 47.79 63.835 ;
     RECT  1.08 63.835 47.79 64.762 ;
     RECT  1.098 64.762 1.404 64.781 ;
     RECT  1.422 64.762 1.764 64.781 ;
     RECT  1.782 64.762 2.088 64.781 ;
     RECT  2.106 64.762 2.448 64.781 ;
     RECT  2.466 64.762 2.772 64.781 ;
     RECT  2.79 64.762 3.132 64.781 ;
     RECT  3.15 64.762 3.456 64.781 ;
     RECT  3.474 64.762 3.816 64.781 ;
     RECT  3.834 64.762 4.14 64.781 ;
     RECT  4.158 64.762 4.5 64.781 ;
     RECT  4.518 64.762 4.824 64.781 ;
     RECT  4.842 64.762 5.184 64.781 ;
     RECT  5.202 64.762 5.508 64.781 ;
     RECT  5.526 64.762 5.832 64.781 ;
     RECT  5.85 64.762 6.192 64.781 ;
     RECT  6.21 64.762 6.516 64.781 ;
     RECT  6.534 64.762 6.876 64.781 ;
     RECT  6.894 64.762 7.2 64.781 ;
     RECT  7.218 64.762 7.56 64.781 ;
     RECT  7.578 64.762 7.884 64.781 ;
     RECT  7.902 64.762 8.244 64.781 ;
     RECT  8.262 64.762 8.568 64.781 ;
     RECT  8.586 64.762 8.928 64.781 ;
     RECT  8.946 64.762 9.252 64.781 ;
     RECT  9.27 64.762 9.612 64.781 ;
     RECT  9.63 64.762 9.936 64.781 ;
     RECT  9.954 64.762 10.296 64.781 ;
     RECT  10.314 64.762 10.62 64.781 ;
     RECT  10.638 64.762 10.944 64.781 ;
     RECT  10.962 64.762 11.304 64.781 ;
     RECT  11.322 64.762 11.628 64.781 ;
     RECT  11.646 64.762 11.988 64.781 ;
     RECT  12.006 64.762 12.312 64.781 ;
     RECT  12.33 64.762 12.672 64.781 ;
     RECT  12.69 64.762 12.996 64.781 ;
     RECT  13.014 64.762 13.356 64.781 ;
     RECT  13.374 64.762 13.68 64.781 ;
     RECT  13.698 64.762 14.04 64.781 ;
     RECT  14.058 64.762 14.364 64.781 ;
     RECT  14.382 64.762 14.724 64.781 ;
     RECT  14.742 64.762 15.048 64.781 ;
     RECT  15.066 64.762 15.408 64.781 ;
     RECT  15.426 64.762 15.732 64.781 ;
     RECT  15.75 64.762 16.092 64.781 ;
     RECT  16.11 64.762 16.416 64.781 ;
     RECT  16.434 64.762 16.74 64.781 ;
     RECT  16.758 64.762 17.1 64.781 ;
     RECT  17.118 64.762 17.424 64.781 ;
     RECT  17.442 64.762 17.784 64.781 ;
     RECT  17.802 64.762 18.108 64.781 ;
     RECT  18.126 64.762 18.468 64.781 ;
     RECT  18.486 64.762 18.792 64.781 ;
     RECT  18.81 64.762 19.152 64.781 ;
     RECT  19.17 64.762 19.476 64.781 ;
     RECT  19.494 64.762 19.836 64.781 ;
     RECT  19.854 64.762 20.16 64.781 ;
     RECT  20.178 64.762 20.52 64.781 ;
     RECT  20.538 64.762 20.844 64.781 ;
     RECT  20.862 64.762 21.204 64.781 ;
     RECT  21.222 64.762 21.528 64.781 ;
     RECT  21.546 64.762 21.852 64.781 ;
     RECT  21.87 64.762 22.212 64.781 ;
     RECT  22.23 64.762 22.536 64.781 ;
     RECT  22.554 64.762 22.896 64.781 ;
     RECT  22.914 64.762 23.22 64.781 ;
     RECT  23.238 64.762 23.58 64.781 ;
     RECT  23.598 64.762 23.904 64.781 ;
     RECT  23.922 64.762 24.264 64.781 ;
     RECT  24.282 64.762 24.588 64.781 ;
     RECT  24.606 64.762 24.948 64.781 ;
     RECT  24.966 64.762 25.272 64.781 ;
     RECT  25.29 64.762 25.632 64.781 ;
     RECT  25.65 64.762 25.956 64.781 ;
     RECT  25.974 64.762 26.316 64.781 ;
     RECT  26.334 64.762 26.64 64.781 ;
     RECT  26.658 64.762 27 64.781 ;
     RECT  27.018 64.762 27.324 64.781 ;
     RECT  27.342 64.762 27.648 64.781 ;
     RECT  27.666 64.762 28.008 64.781 ;
     RECT  28.026 64.762 28.332 64.781 ;
     RECT  28.35 64.762 28.692 64.781 ;
     RECT  28.71 64.762 29.016 64.781 ;
     RECT  29.034 64.762 29.376 64.781 ;
     RECT  29.394 64.762 29.7 64.781 ;
     RECT  29.718 64.762 30.06 64.781 ;
     RECT  30.078 64.762 30.384 64.781 ;
     RECT  30.402 64.762 30.744 64.781 ;
     RECT  30.762 64.762 31.068 64.781 ;
     RECT  31.086 64.762 31.428 64.781 ;
     RECT  31.446 64.762 31.752 64.781 ;
     RECT  31.77 64.762 32.112 64.781 ;
     RECT  32.13 64.762 32.436 64.781 ;
     RECT  32.454 64.762 32.76 64.781 ;
     RECT  32.778 64.762 33.12 64.781 ;
     RECT  33.138 64.762 33.444 64.781 ;
     RECT  33.462 64.762 33.804 64.781 ;
     RECT  33.822 64.762 34.128 64.781 ;
     RECT  34.146 64.762 34.488 64.781 ;
     RECT  34.506 64.762 34.812 64.781 ;
     RECT  34.83 64.762 35.172 64.781 ;
     RECT  35.19 64.762 35.496 64.781 ;
     RECT  35.514 64.762 35.856 64.781 ;
     RECT  35.874 64.762 36.18 64.781 ;
     RECT  36.198 64.762 36.54 64.781 ;
     RECT  36.558 64.762 36.864 64.781 ;
     RECT  36.882 64.762 37.224 64.781 ;
     RECT  37.242 64.762 37.548 64.781 ;
     RECT  37.566 64.762 37.908 64.781 ;
     RECT  37.926 64.762 38.232 64.781 ;
     RECT  38.25 64.762 38.556 64.781 ;
     RECT  38.574 64.762 38.916 64.781 ;
     RECT  38.934 64.762 39.24 64.781 ;
     RECT  39.258 64.762 39.6 64.781 ;
     RECT  39.618 64.762 39.924 64.781 ;
     RECT  39.942 64.762 40.284 64.781 ;
     RECT  40.302 64.762 40.608 64.781 ;
     RECT  40.626 64.762 40.968 64.781 ;
     RECT  40.986 64.762 41.292 64.781 ;
     RECT  41.31 64.762 41.652 64.781 ;
     RECT  41.67 64.762 41.976 64.781 ;
     RECT  41.994 64.762 42.336 64.781 ;
     RECT  42.354 64.762 42.66 64.781 ;
     RECT  42.678 64.762 43.02 64.781 ;
     RECT  43.038 64.762 43.344 64.781 ;
     RECT  43.362 64.762 43.668 64.781 ;
     RECT  43.686 64.762 44.028 64.781 ;
     RECT  44.046 64.762 44.352 64.781 ;
     RECT  44.37 64.762 44.712 64.781 ;
     RECT  44.73 64.762 45.036 64.781 ;
     RECT  45.054 64.762 45.396 64.781 ;
     RECT  45.414 64.762 45.72 64.781 ;
     RECT  45.738 64.762 46.08 64.781 ;
     RECT  46.098 64.762 46.404 64.781 ;
     RECT  46.422 64.762 46.764 64.781 ;
     RECT  46.782 64.762 47.088 64.781 ;
     RECT  47.106 64.762 47.448 64.781 ;
     RECT  47.466 64.762 47.772 64.781 ;
    LAYER M4 ;
     RECT  1.237 0.096 1.909 0.12 ;
     RECT  1.573 5.136 2.245 5.16 ;
     RECT  2.293 10.128 2.329 10.152 ;
     RECT  1.237 11.952 2.332 11.976 ;
     RECT  2.329 6.816 2.365 6.84 ;
     RECT  2.332 11.952 2.365 12.024 ;
     RECT  2.329 10.08 2.401 10.2 ;
     RECT  1.909 18.192 2.401 18.216 ;
     RECT  2.365 2.88 2.408 2.904 ;
     RECT  2.245 5.136 2.408 5.736 ;
     RECT  2.365 6.816 2.408 7.368 ;
     RECT  2.293 8.496 2.408 8.52 ;
     RECT  2.401 9.888 2.408 10.2 ;
     RECT  2.365 11.232 2.408 12.024 ;
     RECT  2.365 13.824 2.408 13.848 ;
     RECT  2.365 16.848 2.408 16.872 ;
     RECT  2.401 18.192 2.408 18.456 ;
     RECT  2.293 24.144 2.408 24.168 ;
     RECT  2.365 28.464 2.408 28.488 ;
     RECT  2.365 31.776 2.408 31.8 ;
     RECT  2.365 36.624 2.408 36.648 ;
     RECT  2.401 37.872 2.408 37.896 ;
     RECT  2.365 40.416 2.408 40.44 ;
     RECT  1.573 43.296 2.408 43.32 ;
     RECT  2.365 52.464 2.408 52.488 ;
     RECT  2.365 57.312 2.408 57.336 ;
     RECT  2.365 58.656 2.408 58.68 ;
     RECT  2.408 2.148 2.512 62.652 ;
     RECT  2.245 64.656 2.581 64.68 ;
     RECT  2.512 2.418 2.704 62.382 ;
     RECT  2.704 22.848 2.819 27.24 ;
     RECT  2.581 64.56 2.869 64.68 ;
     RECT  2.869 64.464 2.956 64.68 ;
     RECT  2.956 64.608 2.989 64.68 ;
     RECT  2.819 25.104 3.017 27.24 ;
     RECT  1.909 0.096 3.089 0.504 ;
     RECT  2.704 36.624 3.161 43.32 ;
     RECT  2.704 16.848 3.251 18.744 ;
     RECT  2.704 34.224 3.341 35.352 ;
     RECT  2.704 56.928 3.341 60.408 ;
     RECT  2.704 30.48 3.347 30.792 ;
     RECT  2.989 64.656 3.347 64.68 ;
     RECT  3.089 0.096 3.409 0.216 ;
     RECT  3.161 37.296 3.449 43.32 ;
     RECT  2.704 19.824 3.593 21.816 ;
     RECT  3.409 0.048 3.629 0.216 ;
     RECT  3.589 62.64 3.683 62.664 ;
     RECT  3.629 0.048 3.701 0.168 ;
     RECT  3.593 20.064 3.733 21.816 ;
     RECT  2.819 22.848 3.733 23.736 ;
     RECT  3.449 38.784 3.745 43.32 ;
     RECT  2.704 28.464 3.769 29.256 ;
     RECT  3.347 30.576 3.805 30.792 ;
     RECT  2.704 31.776 3.805 32.616 ;
     RECT  2.704 50.112 3.805 54.6 ;
     RECT  3.745 38.784 3.809 39.384 ;
     RECT  3.017 25.68 3.836 27.24 ;
     RECT  2.704 44.928 3.841 45.048 ;
     RECT  3.341 56.928 3.841 57.096 ;
     RECT  3.745 40.8 3.845 43.32 ;
     RECT  3.805 50.112 3.877 54.744 ;
     RECT  3.877 50.064 3.913 54.744 ;
     RECT  3.805 64.704 3.923 64.728 ;
     RECT  2.704 46.752 3.925 48.984 ;
     RECT  3.913 50.064 3.925 54.84 ;
     RECT  3.733 20.064 4.021 23.736 ;
     RECT  3.836 25.68 4.021 27.336 ;
     RECT  3.769 28.464 4.049 29.352 ;
     RECT  4.021 25.056 4.057 27.336 ;
     RECT  4.049 28.32 4.057 29.352 ;
     RECT  3.841 44.928 4.057 45.288 ;
     RECT  3.925 46.752 4.057 54.84 ;
     RECT  3.841 56.304 4.061 57.096 ;
     RECT  4.021 20.064 4.093 23.832 ;
     RECT  4.057 46.752 4.093 55.032 ;
     RECT  3.809 38.784 4.097 38.904 ;
     RECT  3.341 58.128 4.165 60.408 ;
     RECT  2.704 2.736 4.201 15.624 ;
     RECT  3.251 16.848 4.201 17.16 ;
     RECT  3.341 34.224 4.201 34.776 ;
     RECT  4.201 2.736 4.268 17.16 ;
     RECT  3.697 35.904 4.309 36.312 ;
     RECT  3.449 37.296 4.309 37.608 ;
     RECT  4.057 25.056 4.345 29.352 ;
     RECT  3.805 30.576 4.345 32.616 ;
     RECT  4.201 34.08 4.381 34.776 ;
     RECT  4.309 35.904 4.381 37.608 ;
     RECT  4.093 20.064 4.481 23.976 ;
     RECT  4.481 20.064 4.489 24.024 ;
     RECT  4.345 25.056 4.489 33.048 ;
     RECT  4.093 62.448 4.489 62.472 ;
     RECT  4.268 2.256 4.597 17.16 ;
     RECT  3.251 18.432 4.597 18.744 ;
     RECT  3.701 0.096 4.645 0.168 ;
     RECT  4.381 34.08 4.837 37.608 ;
     RECT  4.489 20.064 4.849 33.048 ;
     RECT  3.845 40.8 4.957 42.696 ;
     RECT  4.057 43.776 4.957 45.288 ;
     RECT  4.093 46.512 5.029 55.032 ;
     RECT  4.957 40.8 5.101 45.288 ;
     RECT  4.597 2.256 5.108 18.744 ;
     RECT  4.849 19.776 5.108 33.048 ;
     RECT  4.837 34.08 5.108 38.472 ;
     RECT  5.101 39.84 5.108 45.288 ;
     RECT  5.029 46.512 5.108 55.272 ;
     RECT  4.061 56.352 5.108 57.096 ;
     RECT  4.165 58.128 5.108 60.456 ;
     RECT  4.489 62.16 5.108 62.472 ;
     RECT  5.108 2.148 5.317 62.652 ;
     RECT  5.317 2.016 5.404 63.24 ;
     RECT  5.404 27.696 5.429 38.808 ;
     RECT  5.404 62.208 5.429 63.24 ;
     RECT  5.404 3.024 5.573 25.464 ;
     RECT  5.404 41.232 5.581 57.096 ;
     RECT  5.429 27.696 5.609 35.832 ;
     RECT  5.581 41.232 5.609 45.24 ;
     RECT  5.573 3.024 5.645 15.432 ;
     RECT  4.645 0.096 5.653 0.216 ;
     RECT  5.429 62.448 5.747 63.24 ;
     RECT  5.609 27.984 5.825 35.832 ;
     RECT  5.404 2.016 5.897 2.04 ;
     RECT  5.825 27.984 5.897 29.592 ;
     RECT  5.404 39.888 5.897 40.152 ;
     RECT  5.897 27.984 5.933 29.496 ;
     RECT  5.609 42.72 5.969 45.24 ;
     RECT  5.969 43.296 5.987 45.24 ;
     RECT  5.645 4.512 6.005 15.432 ;
     RECT  5.581 46.608 6.077 57.096 ;
     RECT  5.897 39.888 6.365 39.912 ;
     RECT  6.077 56.112 6.38 57.096 ;
     RECT  5.404 58.224 6.38 61.032 ;
     RECT  6.38 56.112 6.437 61.032 ;
     RECT  5.653 0.096 6.509 0.264 ;
     RECT  6.077 46.608 6.509 54.456 ;
     RECT  5.747 62.448 6.545 62.472 ;
     RECT  5.825 30.576 6.572 35.832 ;
     RECT  5.429 37.104 6.572 38.808 ;
     RECT  5.573 16.56 6.613 25.464 ;
     RECT  5.645 3.408 6.649 3.432 ;
     RECT  6.005 4.512 6.649 14.952 ;
     RECT  6.572 30.576 6.659 38.808 ;
     RECT  5.989 64.656 6.661 64.68 ;
     RECT  5.933 27.984 6.685 29.112 ;
     RECT  6.659 37.152 6.725 38.808 ;
     RECT  6.649 3.408 6.793 14.952 ;
     RECT  6.725 37.584 6.829 38.808 ;
     RECT  6.685 27.744 7.045 29.112 ;
     RECT  6.659 30.576 7.045 35.832 ;
     RECT  6.793 2.832 7.081 14.952 ;
     RECT  6.613 16.368 7.237 25.464 ;
     RECT  5.404 26.592 7.261 26.616 ;
     RECT  7.045 27.744 7.261 35.832 ;
     RECT  5.609 41.232 7.285 41.736 ;
     RECT  7.285 41.04 7.333 41.736 ;
     RECT  5.987 43.296 7.333 45 ;
     RECT  7.081 2.784 7.369 14.952 ;
     RECT  6.973 1.728 7.388 1.752 ;
     RECT  7.369 2.784 7.388 15.048 ;
     RECT  7.388 1.728 7.427 15.048 ;
     RECT  7.427 2.148 7.441 15.048 ;
     RECT  7.237 16.128 7.441 25.464 ;
     RECT  7.333 41.04 7.477 45 ;
     RECT  6.509 47.856 7.549 54.456 ;
     RECT  7.549 47.616 7.573 54.456 ;
     RECT  7.573 47.616 7.585 54.6 ;
     RECT  7.441 2.148 7.669 25.464 ;
     RECT  7.261 26.592 7.669 35.832 ;
     RECT  6.901 62.16 7.765 62.184 ;
     RECT  7.669 2.148 7.808 35.832 ;
     RECT  6.829 37.584 7.808 39.336 ;
     RECT  7.477 40.608 7.808 45 ;
     RECT  6.509 46.608 7.808 46.632 ;
     RECT  7.585 47.616 7.808 54.744 ;
     RECT  6.437 56.112 7.808 60.888 ;
     RECT  7.765 62.16 7.808 62.52 ;
     RECT  7.808 2.148 7.912 62.652 ;
     RECT  6.661 63.84 7.913 64.68 ;
     RECT  6.509 0.096 8.053 0.168 ;
     RECT  7.912 2.418 8.104 62.52 ;
     RECT  8.104 2.784 8.165 12.456 ;
     RECT  8.104 28.8 8.165 35.832 ;
     RECT  8.104 46.608 8.273 54.744 ;
     RECT  8.104 13.584 8.291 22.92 ;
     RECT  8.104 56.64 8.332 62.52 ;
     RECT  7.913 64.56 8.435 64.68 ;
     RECT  8.165 33.072 8.453 35.832 ;
     RECT  8.104 23.904 8.489 27.72 ;
     RECT  8.453 34.416 8.525 35.832 ;
     RECT  8.053 0.096 8.684 0.216 ;
     RECT  8.291 13.584 8.741 19.896 ;
     RECT  8.489 23.904 8.741 27.672 ;
     RECT  8.332 57.024 8.741 62.52 ;
     RECT  8.684 0.096 8.771 0.552 ;
     RECT  8.273 46.608 8.777 54.696 ;
     RECT  8.165 28.8 8.849 31.992 ;
     RECT  8.741 60.96 8.849 62.52 ;
     RECT  8.165 2.832 8.993 12.456 ;
     RECT  8.525 34.752 9.097 35.832 ;
     RECT  8.104 37.056 9.097 41.496 ;
     RECT  8.104 42.528 9.101 45.432 ;
     RECT  8.849 60.96 9.101 62.184 ;
     RECT  8.291 21.024 9.107 22.92 ;
     RECT  9.101 62.16 9.107 62.184 ;
     RECT  8.993 2.832 9.109 11.496 ;
     RECT  9.107 21.12 9.109 22.92 ;
     RECT  8.741 24.24 9.137 27.672 ;
     RECT  8.777 47.616 9.137 54.696 ;
     RECT  8.849 29.616 9.164 31.992 ;
     RECT  8.453 33.072 9.164 33.192 ;
     RECT  9.097 34.752 9.241 41.496 ;
     RECT  8.741 13.584 9.245 14.952 ;
     RECT  9.164 29.616 9.251 33.192 ;
     RECT  9.109 21.168 9.425 22.92 ;
     RECT  8.741 57.024 9.457 59.88 ;
     RECT  9.101 43.344 9.497 45.432 ;
     RECT  9.137 50.016 9.529 54.696 ;
     RECT  8.741 16.032 9.637 19.896 ;
     RECT  9.529 50.016 9.637 54.792 ;
     RECT  9.541 55.872 9.637 55.896 ;
     RECT  8.435 64.656 9.74 64.68 ;
     RECT  8.777 46.608 9.745 46.632 ;
     RECT  9.137 47.616 9.745 48.984 ;
     RECT  9.74 63.84 9.785 64.68 ;
     RECT  9.785 63.84 9.827 63.864 ;
     RECT  9.425 21.408 9.853 22.92 ;
     RECT  9.137 24.24 9.853 27.576 ;
     RECT  9.251 33.072 9.889 33.192 ;
     RECT  9.251 29.616 9.961 31.8 ;
     RECT  9.733 1.728 10.073 1.752 ;
     RECT  9.745 46.608 10.177 48.984 ;
     RECT  9.637 50.016 10.177 55.896 ;
     RECT  9.101 60.96 10.177 61.08 ;
     RECT  9.637 16.032 10.213 20.136 ;
     RECT  9.889 33.072 10.213 33.384 ;
     RECT  9.961 29.232 10.309 31.8 ;
     RECT  10.213 32.832 10.309 33.384 ;
     RECT  9.109 2.88 10.357 11.496 ;
     RECT  9.169 12.528 10.357 12.552 ;
     RECT  9.245 13.584 10.357 14.76 ;
     RECT  10.213 15.984 10.357 20.136 ;
     RECT  9.497 43.632 10.393 45.432 ;
     RECT  10.357 2.88 10.429 12.552 ;
     RECT  8.771 0.096 10.453 0.168 ;
     RECT  10.429 2.148 10.508 12.552 ;
     RECT  10.357 13.584 10.508 20.136 ;
     RECT  9.853 21.408 10.508 27.576 ;
     RECT  10.309 29.232 10.508 33.384 ;
     RECT  9.241 34.752 10.508 41.544 ;
     RECT  10.393 43.632 10.508 45.528 ;
     RECT  10.177 46.608 10.508 55.896 ;
     RECT  9.457 56.88 10.508 59.88 ;
     RECT  10.177 60.96 10.508 61.464 ;
     RECT  10.421 62.784 10.508 62.808 ;
     RECT  10.508 2.148 10.612 62.808 ;
     RECT  10.612 2.256 10.789 62.808 ;
     RECT  10.789 2.256 10.804 63.24 ;
     RECT  10.804 27.888 10.865 31.8 ;
     RECT  10.453 0.096 11.009 0.552 ;
     RECT  10.804 43.728 11.045 59.832 ;
     RECT  10.804 63.216 11.153 63.24 ;
     RECT  11.045 43.728 11.405 59.784 ;
     RECT  10.804 32.832 11.441 36.072 ;
     RECT  10.804 37.056 11.441 42.216 ;
     RECT  11.461 64.656 11.473 64.68 ;
     RECT  10.804 2.256 11.477 14.664 ;
     RECT  11.477 2.832 11.555 14.664 ;
     RECT  11.555 3.936 11.657 14.664 ;
     RECT  11.555 2.832 11.665 2.856 ;
     RECT  11.441 32.832 11.693 34.104 ;
     RECT  11.657 3.936 11.729 14.52 ;
     RECT  10.804 15.936 11.729 26.904 ;
     RECT  11.729 17.616 11.797 26.904 ;
     RECT  10.865 27.888 11.797 31.512 ;
     RECT  11.441 35.088 11.836 36.072 ;
     RECT  11.405 43.728 11.837 54.984 ;
     RECT  11.473 63.84 11.843 64.68 ;
     RECT  11.797 17.616 11.845 31.512 ;
     RECT  11.441 41.472 11.869 42.216 ;
     RECT  11.845 17.616 11.884 31.8 ;
     RECT  11.441 37.056 11.945 40.056 ;
     RECT  11.884 17.616 12.017 18.264 ;
     RECT  11.884 19.632 12.125 31.8 ;
     RECT  11.009 0.096 12.133 0.216 ;
     RECT  12.125 19.632 12.161 27.384 ;
     RECT  10.804 60.816 12.193 61.752 ;
     RECT  11.836 35.328 12.205 36.072 ;
     RECT  12.133 0.096 12.341 0.312 ;
     RECT  12.341 0.096 12.413 0.168 ;
     RECT  11.843 64.656 12.515 64.68 ;
     RECT  11.729 15.936 12.697 16.584 ;
     RECT  12.017 17.616 12.697 18.216 ;
     RECT  12.62 64.704 12.707 64.728 ;
     RECT  12.697 15.936 12.805 18.216 ;
     RECT  12.205 35.52 12.805 36.072 ;
     RECT  11.945 37.056 12.805 38.184 ;
     RECT  11.729 3.936 12.913 14.136 ;
     RECT  12.805 15.216 12.913 18.216 ;
     RECT  11.405 56.064 12.949 59.784 ;
     RECT  12.913 3.936 12.985 18.216 ;
     RECT  12.193 60.816 13.057 61.944 ;
     RECT  12.161 19.776 13.093 27.384 ;
     RECT  12.125 28.416 13.093 31.8 ;
     RECT  13.057 60.816 13.187 62.808 ;
     RECT  12.985 3.936 13.208 18.792 ;
     RECT  13.093 19.776 13.208 31.8 ;
     RECT  11.693 32.928 13.208 34.104 ;
     RECT  12.805 35.52 13.208 38.184 ;
     RECT  11.945 39.216 13.208 40.056 ;
     RECT  11.869 41.472 13.208 42.744 ;
     RECT  11.837 43.824 13.208 54.984 ;
     RECT  12.949 56.064 13.208 59.832 ;
     RECT  13.187 60.816 13.208 62.652 ;
     RECT  13.208 2.148 13.312 62.652 ;
     RECT  13.312 2.208 13.504 62.382 ;
     RECT  13.504 3.36 13.619 12.888 ;
     RECT  13.504 55.824 13.619 61.944 ;
     RECT  13.504 32.976 13.667 39.624 ;
     RECT  13.504 13.968 13.673 26.664 ;
     RECT  13.619 55.824 13.673 59.784 ;
     RECT  13.619 60.816 13.673 61.944 ;
     RECT  13.667 33.024 13.709 39.624 ;
     RECT  13.619 4.512 13.781 12.888 ;
     RECT  13.673 15.168 13.781 26.664 ;
     RECT  13.504 40.944 13.781 48.84 ;
     RECT  13.673 60.816 13.781 61.752 ;
     RECT  13.619 3.36 13.817 3.432 ;
     RECT  12.413 0.096 13.82 0.12 ;
     RECT  13.781 4.512 13.889 11.448 ;
     RECT  13.82 0.096 13.907 0.552 ;
     RECT  13.889 4.512 13.925 11.208 ;
     RECT  13.781 47.568 13.925 48.84 ;
     RECT  13.673 56.064 13.961 59.784 ;
     RECT  13.709 33.6 14.099 39.624 ;
     RECT  13.781 40.944 14.236 46.536 ;
     RECT  13.504 52.416 14.249 54.792 ;
     RECT  14.249 52.512 14.285 54.792 ;
     RECT  13.925 47.904 14.357 48.84 ;
     RECT  14.285 52.512 14.357 54.696 ;
     RECT  14.099 34.752 14.387 39.624 ;
     RECT  14.236 43.728 14.435 46.536 ;
     RECT  13.781 15.216 14.537 26.664 ;
     RECT  14.435 43.872 14.537 45.144 ;
     RECT  13.781 60.816 14.579 61.56 ;
     RECT  13.925 4.656 14.645 11.208 ;
     RECT  13.961 56.496 14.78 59.784 ;
     RECT  14.579 60.816 14.78 61.032 ;
     RECT  13.504 2.208 14.821 2.232 ;
     RECT  13.504 27.744 14.821 31.896 ;
     RECT  13.673 13.968 14.861 14.136 ;
     RECT  14.236 40.944 14.861 42.552 ;
     RECT  13.504 49.824 14.861 51.288 ;
     RECT  14.78 56.496 14.867 61.032 ;
     RECT  13.907 0.096 14.869 0.168 ;
     RECT  14.357 48.192 14.869 48.84 ;
     RECT  14.861 49.824 14.869 50.856 ;
     RECT  13.525 64.656 14.876 64.68 ;
     RECT  14.537 15.984 14.897 26.664 ;
     RECT  14.861 41.472 14.897 42.552 ;
     RECT  14.821 2.064 14.929 2.232 ;
     RECT  14.645 10.608 14.929 11.208 ;
     RECT  13.781 12.672 14.929 12.888 ;
     RECT  14.435 46.32 14.929 46.536 ;
     RECT  14.897 17.664 14.965 26.664 ;
     RECT  14.821 27.744 14.965 31.944 ;
     RECT  14.929 2.064 15.001 2.328 ;
     RECT  13.817 3.408 15.001 3.432 ;
     RECT  14.897 42.48 15.325 42.552 ;
     RECT  14.357 52.56 15.349 54.696 ;
     RECT  14.099 33.6 15.433 33.624 ;
     RECT  14.897 15.984 15.505 16.584 ;
     RECT  14.929 46.32 15.505 46.776 ;
     RECT  14.869 48.192 15.505 50.856 ;
     RECT  15.001 2.064 15.548 3.432 ;
     RECT  14.645 4.656 15.548 9.528 ;
     RECT  15.433 33.12 15.589 33.624 ;
     RECT  15.505 15.408 15.613 16.584 ;
     RECT  15.349 52.56 15.613 55.272 ;
     RECT  14.387 35.52 15.649 39.624 ;
     RECT  14.537 44.064 15.685 45.144 ;
     RECT  15.505 46.32 15.685 50.856 ;
     RECT  14.861 14.112 15.781 14.136 ;
     RECT  15.613 15.216 15.781 16.584 ;
     RECT  15.548 2.064 15.908 9.528 ;
     RECT  14.929 10.608 15.908 12.888 ;
     RECT  15.781 14.112 15.908 16.584 ;
     RECT  14.965 17.664 15.908 31.944 ;
     RECT  15.589 33.024 15.908 33.624 ;
     RECT  15.649 34.896 15.908 39.624 ;
     RECT  14.897 41.472 15.908 41.496 ;
     RECT  15.325 42.48 15.908 42.6 ;
     RECT  15.685 44.064 15.908 50.856 ;
     RECT  15.613 52.56 15.908 55.464 ;
     RECT  14.867 56.496 15.908 59.784 ;
     RECT  14.867 60.816 15.908 61.032 ;
     RECT  15.793 62.784 15.908 62.808 ;
     RECT  14.876 63.84 16.081 64.68 ;
     RECT  15.908 2.064 16.204 62.808 ;
     RECT  16.081 63.84 16.213 64.728 ;
     RECT  16.204 42.48 16.265 55.464 ;
     RECT  16.213 63.216 16.355 64.728 ;
     RECT  16.204 2.064 16.444 41.496 ;
     RECT  16.444 2.064 16.451 36.504 ;
     RECT  16.265 42.768 16.451 55.464 ;
     RECT  16.451 2.064 16.499 31.944 ;
     RECT  14.869 0.096 16.508 0.216 ;
     RECT  16.499 2.832 16.517 31.944 ;
     RECT  16.517 2.832 16.547 27.96 ;
     RECT  16.508 0.096 16.595 0.552 ;
     RECT  16.451 43.104 16.697 55.464 ;
     RECT  16.204 56.688 16.697 61.608 ;
     RECT  16.547 8.352 16.805 27.96 ;
     RECT  16.805 8.352 16.883 27.912 ;
     RECT  16.355 63.216 16.913 64.68 ;
     RECT  16.883 8.352 16.931 27.72 ;
     RECT  16.697 43.104 17.065 55.272 ;
     RECT  17.065 47.712 17.345 55.272 ;
     RECT  16.444 37.536 17.377 41.496 ;
     RECT  16.697 56.688 17.377 60.408 ;
     RECT  16.547 2.832 17.521 7.224 ;
     RECT  16.517 28.944 17.521 31.944 ;
     RECT  16.451 33.024 17.521 36.504 ;
     RECT  16.595 0.096 17.605 0.216 ;
     RECT  16.697 61.392 17.629 61.608 ;
     RECT  17.377 56.4 17.66 60.408 ;
     RECT  17.629 61.392 17.66 61.896 ;
     RECT  17.521 28.944 17.665 36.504 ;
     RECT  17.377 37.536 17.665 42.024 ;
     RECT  17.521 2.304 17.701 7.224 ;
     RECT  16.931 8.352 17.701 22.056 ;
     RECT  17.701 2.304 17.845 22.056 ;
     RECT  17.66 56.4 17.909 61.896 ;
     RECT  17.605 0.096 17.941 0.264 ;
     RECT  16.931 23.328 18.169 27.72 ;
     RECT  17.665 28.944 18.169 42.024 ;
     RECT  17.909 56.4 18.565 62.712 ;
     RECT  17.845 2.256 18.608 22.056 ;
     RECT  18.169 23.328 18.608 42.024 ;
     RECT  17.065 43.104 18.608 46.728 ;
     RECT  17.345 47.712 18.608 50.952 ;
     RECT  17.345 51.936 18.608 55.272 ;
     RECT  18.565 56.4 18.608 62.808 ;
     RECT  17.941 0.096 18.613 0.312 ;
     RECT  18.608 2.148 18.712 62.808 ;
     RECT  18.712 2.304 18.904 62.808 ;
     RECT  16.913 63.84 18.949 64.68 ;
     RECT  18.904 35.088 18.965 61.464 ;
     RECT  18.904 23.328 19.181 26.04 ;
     RECT  18.613 0.096 19.217 0.552 ;
     RECT  18.904 4.416 19.217 11.256 ;
     RECT  18.904 27.264 19.253 33.96 ;
     RECT  18.965 48.192 19.253 61.464 ;
     RECT  19.217 6 19.283 11.256 ;
     RECT  18.904 12.24 19.283 22.056 ;
     RECT  19.283 6.096 19.289 11.256 ;
     RECT  19.253 48.432 19.289 61.464 ;
     RECT  19.181 23.328 19.325 25.896 ;
     RECT  18.965 35.088 19.325 47.16 ;
     RECT  18.949 63.216 19.325 64.68 ;
     RECT  19.283 12.24 19.379 15.72 ;
     RECT  19.325 35.088 19.397 41.064 ;
     RECT  19.325 42.144 19.477 47.16 ;
     RECT  19.289 48.432 19.505 61.032 ;
     RECT  19.379 12.576 19.613 15.72 ;
     RECT  18.904 2.304 19.763 3.432 ;
     RECT  19.325 63.216 19.901 63.24 ;
     RECT  19.477 42.72 19.937 47.16 ;
     RECT  19.505 48.432 19.937 55.512 ;
     RECT  19.937 48.432 19.948 55.464 ;
     RECT  19.253 31.92 19.957 33.96 ;
     RECT  19.397 35.088 19.957 38.472 ;
     RECT  19.937 42.72 20.009 44.472 ;
     RECT  19.505 57.024 20.153 61.032 ;
     RECT  20.153 57.408 20.189 61.032 ;
     RECT  19.283 16.896 20.252 22.056 ;
     RECT  19.613 15.456 20.257 15.72 ;
     RECT  20.252 16.896 20.257 22.2 ;
     RECT  19.325 64.656 20.329 64.68 ;
     RECT  19.397 39.648 20.401 41.064 ;
     RECT  19.289 6.24 20.485 11.256 ;
     RECT  19.613 12.576 20.485 14.232 ;
     RECT  19.217 4.416 20.509 4.92 ;
     RECT  20.485 6.24 20.509 14.232 ;
     RECT  19.253 27.264 20.533 30.696 ;
     RECT  19.957 31.92 20.533 38.472 ;
     RECT  19.948 48.432 20.533 50.76 ;
     RECT  20.533 27.264 20.617 38.472 ;
     RECT  20.617 27.264 20.629 38.664 ;
     RECT  20.401 39.648 20.629 41.688 ;
     RECT  19.217 0.096 20.636 0.168 ;
     RECT  20.636 0.096 20.723 0.552 ;
     RECT  20.329 64.608 20.723 64.68 ;
     RECT  20.545 2.256 20.725 2.28 ;
     RECT  19.763 3.408 20.725 3.432 ;
     RECT  20.257 15.456 20.761 22.2 ;
     RECT  20.629 27.264 20.761 41.688 ;
     RECT  20.009 42.72 20.761 44.04 ;
     RECT  20.761 15.216 20.869 22.2 ;
     RECT  20.869 15.216 20.905 22.248 ;
     RECT  19.325 23.328 20.905 25.848 ;
     RECT  20.725 2.256 20.933 3.432 ;
     RECT  20.509 4.416 20.933 14.232 ;
     RECT  20.905 15.216 21 25.848 ;
     RECT  20.761 27.264 21 44.04 ;
     RECT  20.869 62.16 21.041 62.184 ;
     RECT  21 15.216 21.048 44.04 ;
     RECT  19.937 45.456 21.048 47.16 ;
     RECT  20.723 64.656 21.059 64.68 ;
     RECT  20.533 48.24 21.109 50.76 ;
     RECT  19.948 51.936 21.109 55.464 ;
     RECT  20.933 2.256 21.116 14.232 ;
     RECT  21.048 15.216 21.116 47.16 ;
     RECT  20.189 57.408 21.157 60.456 ;
     RECT  21.041 61.584 21.157 62.184 ;
     RECT  21.109 48.24 21.193 55.464 ;
     RECT  21.157 56.496 21.193 62.184 ;
     RECT  21.193 48.24 21.265 62.184 ;
     RECT  21.116 2.256 21.308 47.16 ;
     RECT  21.265 48.24 21.308 62.808 ;
     RECT  21.308 2.148 21.395 62.808 ;
     RECT  21.395 2.148 21.412 62.652 ;
     RECT  21.412 2.148 21.604 62.382 ;
     RECT  21.604 3.744 21.665 7.464 ;
     RECT  21.604 2.148 21.685 2.568 ;
     RECT  21.665 3.744 21.701 5.832 ;
     RECT  21.604 44.88 21.773 47.16 ;
     RECT  21.604 51.936 21.779 54.744 ;
     RECT  21.701 3.744 21.809 5.784 ;
     RECT  21.604 55.776 21.881 62.232 ;
     RECT  21.604 48.144 21.923 50.184 ;
     RECT  21.685 1.728 22.061 2.568 ;
     RECT  21.604 8.448 22.097 36.984 ;
     RECT  21.809 3.744 22.241 5.112 ;
     RECT  21.881 55.92 22.393 62.232 ;
     RECT  22.097 22.752 22.529 36.984 ;
     RECT  22.097 8.448 22.565 21.576 ;
     RECT  22.529 22.752 22.601 26.664 ;
     RECT  21.665 6.816 22.633 7.464 ;
     RECT  22.565 8.448 22.633 21.432 ;
     RECT  20.723 0.096 22.661 0.168 ;
     RECT  22.393 56.88 22.661 62.232 ;
     RECT  21.773 45.024 22.669 47.16 ;
     RECT  21.604 39.792 22.693 43.656 ;
     RECT  22.693 39.792 22.741 43.8 ;
     RECT  22.669 45.024 22.741 47.208 ;
     RECT  22.661 0.096 22.745 0.264 ;
     RECT  22.601 22.752 22.745 26.568 ;
     RECT  22.661 56.88 22.745 62.712 ;
     RECT  22.529 27.888 22.813 36.984 ;
     RECT  21.604 38.448 22.813 38.76 ;
     RECT  22.745 56.88 22.817 62.04 ;
     RECT  22.061 2.544 22.849 2.568 ;
     RECT  22.633 6.816 22.853 21.432 ;
     RECT  22.741 39.792 22.853 47.208 ;
     RECT  22.237 63.84 22.885 63.864 ;
     RECT  22.853 39.792 22.925 47.16 ;
     RECT  22.885 63.84 22.979 64.728 ;
     RECT  22.853 6.816 22.997 19.32 ;
     RECT  21.923 48.192 23.065 50.184 ;
     RECT  21.779 51.936 23.065 54.696 ;
     RECT  22.241 3.936 23.173 5.112 ;
     RECT  22.849 2.544 23.276 2.856 ;
     RECT  23.173 3.936 23.276 5.304 ;
     RECT  23.065 51.888 23.281 54.696 ;
     RECT  23.276 2.544 23.317 5.304 ;
     RECT  23.065 48.192 23.533 50.232 ;
     RECT  23.281 51.216 23.533 54.696 ;
     RECT  23.317 2.544 23.641 5.352 ;
     RECT  22.997 6.816 23.641 7.992 ;
     RECT  22.813 27.888 23.653 38.76 ;
     RECT  23.641 2.544 23.677 7.992 ;
     RECT  22.853 20.352 23.677 21.432 ;
     RECT  22.745 0.096 23.708 0.168 ;
     RECT  22.817 56.88 23.785 57.096 ;
     RECT  22.817 58.128 23.785 61.368 ;
     RECT  23.708 0.096 23.795 0.552 ;
     RECT  22.997 9.072 24.001 19.32 ;
     RECT  23.677 20.352 24.001 21.816 ;
     RECT  23.677 2.304 24.008 7.992 ;
     RECT  24.001 9.072 24.008 21.816 ;
     RECT  22.745 22.848 24.008 26.568 ;
     RECT  23.653 27.648 24.008 38.76 ;
     RECT  22.925 39.792 24.008 47.064 ;
     RECT  23.533 48.192 24.008 54.696 ;
     RECT  23.785 56.88 24.008 61.368 ;
     RECT  24.008 2.148 24.085 62.652 ;
     RECT  22.979 63.84 24.085 64.68 ;
     RECT  24.085 2.148 24.112 64.68 ;
     RECT  24.112 2.304 24.304 64.68 ;
     RECT  24.304 2.304 24.365 16.776 ;
     RECT  24.304 18.192 24.419 21.816 ;
     RECT  24.304 39.792 24.419 55.08 ;
     RECT  24.419 40.656 24.429 55.08 ;
     RECT  24.365 2.304 24.509 3.864 ;
     RECT  24.365 4.848 24.509 16.776 ;
     RECT  24.429 40.656 24.515 55.032 ;
     RECT  24.304 22.848 24.545 38.184 ;
     RECT  24.509 5.28 24.797 16.776 ;
     RECT  24.304 61.584 24.869 64.68 ;
     RECT  24.515 40.656 24.941 51.768 ;
     RECT  24.941 41.04 24.977 51.768 ;
     RECT  24.419 20.352 25.013 21.816 ;
     RECT  24.545 22.848 25.013 27.912 ;
     RECT  24.509 2.304 25.049 2.328 ;
     RECT  24.797 5.28 25.121 7.656 ;
     RECT  24.977 41.04 25.157 44.472 ;
     RECT  24.797 8.64 25.187 16.776 ;
     RECT  24.977 45.696 25.229 51.768 ;
     RECT  25.013 20.352 25.276 21.576 ;
     RECT  24.545 29.088 25.409 38.184 ;
     RECT  23.795 0.096 25.429 0.168 ;
     RECT  25.409 35.856 25.441 38.184 ;
     RECT  24.304 57.024 25.481 60.216 ;
     RECT  24.869 61.584 25.489 62.712 ;
     RECT  25.409 29.088 25.553 34.728 ;
     RECT  24.509 3.84 25.621 3.864 ;
     RECT  25.187 14.784 25.621 16.776 ;
     RECT  25.553 29.088 25.657 34.344 ;
     RECT  24.515 53.328 25.657 54.888 ;
     RECT  25.229 45.984 25.661 51.768 ;
     RECT  24.419 18.192 25.669 19.32 ;
     RECT  25.276 20.352 25.669 21.384 ;
     RECT  25.657 53.088 25.685 54.888 ;
     RECT  25.489 61.584 25.697 62.328 ;
     RECT  25.441 35.856 25.715 38.712 ;
     RECT  25.621 3.84 25.729 4.536 ;
     RECT  25.661 50.304 25.729 51.768 ;
     RECT  25.715 36.288 25.765 38.712 ;
     RECT  25.621 14.784 25.801 16.872 ;
     RECT  25.669 18.192 25.801 21.384 ;
     RECT  25.013 22.848 25.801 27.192 ;
     RECT  25.481 59.76 25.801 60.216 ;
     RECT  25.121 6 25.837 7.656 ;
     RECT  25.187 8.64 25.837 13.608 ;
     RECT  25.729 50.304 25.837 51.96 ;
     RECT  25.685 53.04 25.837 54.888 ;
     RECT  25.729 3.408 25.868 4.536 ;
     RECT  25.157 41.04 25.945 41.208 ;
     RECT  25.801 22.752 26.017 27.192 ;
     RECT  25.945 40.512 26.089 41.208 ;
     RECT  25.157 42.192 26.089 44.472 ;
     RECT  25.837 50.304 26.089 54.888 ;
     RECT  26.017 22.56 26.125 27.192 ;
     RECT  25.765 36.288 26.125 39.384 ;
     RECT  26.089 40.416 26.125 41.208 ;
     RECT  26.089 42.192 26.125 44.568 ;
     RECT  25.868 3.36 26.197 4.536 ;
     RECT  25.837 6 26.197 13.608 ;
     RECT  26.125 22.56 26.197 27.912 ;
     RECT  25.657 28.896 26.197 34.344 ;
     RECT  26.125 42.192 26.485 44.904 ;
     RECT  25.661 45.984 26.485 49.224 ;
     RECT  26.197 22.464 26.557 34.344 ;
     RECT  25.801 59.76 26.665 61.464 ;
     RECT  26.197 3.36 26.708 13.608 ;
     RECT  25.801 14.784 26.708 21.384 ;
     RECT  26.557 22.464 26.708 35.016 ;
     RECT  26.125 36.288 26.708 41.208 ;
     RECT  26.485 42.192 26.708 49.224 ;
     RECT  26.089 50.304 26.708 55.464 ;
     RECT  25.481 57.024 26.708 58.728 ;
     RECT  26.665 59.76 26.708 62.04 ;
     RECT  26.708 2.148 26.812 62.652 ;
     RECT  25.429 0.096 26.813 0.408 ;
     RECT  26.812 2.148 27.004 62.382 ;
     RECT  27.004 2.148 27.101 18.504 ;
     RECT  27.004 40.608 27.101 58.536 ;
     RECT  27.101 2.148 27.157 2.904 ;
     RECT  27.004 19.536 27.196 39.336 ;
     RECT  27.157 1.728 27.281 2.904 ;
     RECT  27.101 41.712 27.34 58.536 ;
     RECT  27.101 4.128 27.461 18.504 ;
     RECT  27.004 59.808 27.497 62.04 ;
     RECT  24.869 63.84 27.533 64.68 ;
     RECT  27.196 28.752 27.569 39.336 ;
     RECT  27.281 2.16 27.605 2.904 ;
     RECT  27.34 42.192 27.641 58.536 ;
     RECT  27.605 2.16 27.779 2.856 ;
     RECT  27.461 4.128 27.821 13.32 ;
     RECT  27.533 64.464 27.875 64.68 ;
     RECT  27.821 4.128 28.001 9.672 ;
     RECT  27.569 33.312 28.021 39.336 ;
     RECT  27.101 40.608 28.021 40.632 ;
     RECT  27.196 19.536 28.037 27.432 ;
     RECT  28.021 33.312 28.067 40.632 ;
     RECT  27.461 14.448 28.073 18.504 ;
     RECT  27.497 59.808 28.141 61.464 ;
     RECT  28.067 37.872 28.309 40.632 ;
     RECT  27.641 42.192 28.309 53.592 ;
     RECT  28.037 27.072 28.321 27.432 ;
     RECT  27.821 10.656 28.453 13.32 ;
     RECT  28.073 14.448 28.453 16.92 ;
     RECT  28.001 4.128 28.501 9.624 ;
     RECT  28.073 17.952 28.645 18.504 ;
     RECT  28.037 19.536 28.645 26.04 ;
     RECT  27.641 54.864 28.645 58.008 ;
     RECT  28.141 58.992 28.645 61.464 ;
     RECT  28.501 3.84 28.652 9.624 ;
     RECT  28.501 62.448 28.753 62.472 ;
     RECT  27.569 28.752 28.897 31.8 ;
     RECT  28.309 37.872 28.933 53.592 ;
     RECT  28.645 54.864 28.933 61.464 ;
     RECT  28.933 37.872 29.005 61.464 ;
     RECT  28.753 62.448 29.005 62.712 ;
     RECT  28.652 3.744 29.029 9.624 ;
     RECT  28.453 10.656 29.029 16.92 ;
     RECT  28.897 28.752 29.077 32.04 ;
     RECT  28.067 33.312 29.077 36.504 ;
     RECT  29.005 37.872 29.077 62.712 ;
     RECT  27.875 64.56 29.113 64.68 ;
     RECT  27.779 2.16 29.173 2.52 ;
     RECT  29.077 28.752 29.173 62.712 ;
     RECT  29.113 63.84 29.173 64.68 ;
     RECT  28.645 17.952 29.257 26.04 ;
     RECT  28.321 27.072 29.269 27.624 ;
     RECT  29.173 28.752 29.269 64.68 ;
     RECT  29.173 2.16 29.408 2.712 ;
     RECT  29.029 3.744 29.408 16.92 ;
     RECT  29.257 17.952 29.408 26.088 ;
     RECT  29.269 27.072 29.408 64.68 ;
     RECT  29.408 2.148 29.555 64.68 ;
     RECT  29.555 2.148 29.704 63.24 ;
     RECT  29.704 2.148 29.825 25.752 ;
     RECT  29.825 1.728 29.909 25.752 ;
     RECT  26.813 0.096 29.945 0.264 ;
     RECT  29.555 64.464 29.987 64.68 ;
     RECT  29.704 31.68 30.035 58.68 ;
     RECT  29.909 2.496 30.179 25.752 ;
     RECT  30.035 32.016 30.227 58.68 ;
     RECT  29.945 0.144 30.229 0.264 ;
     RECT  30.179 7.344 30.233 25.752 ;
     RECT  30.227 32.016 30.305 58.152 ;
     RECT  29.704 59.712 30.305 61.032 ;
     RECT  30.305 41.04 30.323 58.152 ;
     RECT  30.179 2.496 30.449 6.168 ;
     RECT  30.323 41.04 30.467 58.104 ;
     RECT  29.704 62.256 30.593 63.24 ;
     RECT  30.593 62.256 30.697 62.28 ;
     RECT  30.467 41.04 30.701 57.816 ;
     RECT  29.704 27.168 30.707 30.6 ;
     RECT  30.697 62.112 30.737 62.28 ;
     RECT  30.449 2.496 30.773 5.784 ;
     RECT  30.305 32.016 30.809 39.912 ;
     RECT  30.701 41.184 30.809 57.816 ;
     RECT  30.707 28.416 30.851 30.6 ;
     RECT  30.773 2.496 30.881 2.52 ;
     RECT  30.229 0.144 30.901 0.36 ;
     RECT  30.851 28.464 30.953 30.6 ;
     RECT  30.233 7.968 31.061 25.752 ;
     RECT  30.809 32.016 31.309 39.24 ;
     RECT  30.809 47.664 31.429 57.816 ;
     RECT  29.987 64.512 31.525 64.68 ;
     RECT  30.305 59.856 31.633 61.032 ;
     RECT  30.737 62.112 31.633 62.136 ;
     RECT  31.633 59.856 31.705 62.136 ;
     RECT  30.809 41.184 31.772 46.584 ;
     RECT  31.309 31.872 31.813 39.24 ;
     RECT  31.772 40.56 31.813 46.584 ;
     RECT  30.901 0.144 31.909 0.408 ;
     RECT  31.705 59.856 31.955 62.712 ;
     RECT  31.813 31.776 32.029 46.584 ;
     RECT  31.429 47.664 32.029 58.392 ;
     RECT  31.909 0.144 32.069 0.552 ;
     RECT  31.993 2.88 32.108 2.904 ;
     RECT  30.773 3.936 32.108 5.784 ;
     RECT  31.821 6.816 32.108 6.84 ;
     RECT  31.061 7.968 32.108 15.624 ;
     RECT  31.061 16.8 32.108 25.752 ;
     RECT  30.707 27.168 32.108 27.384 ;
     RECT  30.953 28.752 32.108 30.6 ;
     RECT  32.029 31.776 32.108 58.392 ;
     RECT  31.955 59.856 32.108 62.652 ;
     RECT  32.108 2.148 32.212 62.652 ;
     RECT  32.212 2.304 32.404 62.382 ;
     RECT  32.404 42.72 32.537 57.672 ;
     RECT  32.404 58.656 32.572 62.184 ;
     RECT  32.572 58.656 32.573 58.728 ;
     RECT  32.404 28.704 32.579 39.912 ;
     RECT  32.537 44.88 32.609 53.832 ;
     RECT  32.579 28.704 32.645 34.728 ;
     RECT  32.573 58.704 32.645 58.728 ;
     RECT  32.572 59.808 32.717 62.184 ;
     RECT  32.537 42.72 32.825 43.896 ;
     RECT  32.645 30.384 33.005 34.728 ;
     RECT  32.069 0.144 33.113 0.36 ;
     RECT  32.404 2.304 33.181 3.192 ;
     RECT  33.005 32.208 33.293 34.728 ;
     RECT  32.404 4.272 33.395 27.192 ;
     RECT  32.609 44.88 33.401 53.784 ;
     RECT  32.404 40.944 33.452 41.592 ;
     RECT  32.825 42.72 33.452 43.656 ;
     RECT  33.401 45.216 33.473 52.2 ;
     RECT  32.537 54.816 33.541 57.672 ;
     RECT  33.473 45.216 33.587 51.384 ;
     RECT  32.579 35.712 33.589 39.912 ;
     RECT  33.452 40.944 33.589 43.656 ;
     RECT  33.589 35.712 33.635 43.656 ;
     RECT  33.635 42.816 33.653 43.656 ;
     RECT  32.717 59.808 33.653 62.04 ;
     RECT  31.525 63.84 33.683 64.68 ;
     RECT  32.645 28.704 33.721 29.352 ;
     RECT  33.401 53.28 33.721 53.784 ;
     RECT  33.541 54.816 33.721 58.68 ;
     RECT  33.653 59.808 33.797 61.944 ;
     RECT  33.721 53.28 33.829 58.68 ;
     RECT  33.181 2.256 33.833 3.192 ;
     RECT  33.653 42.96 34.009 43.656 ;
     RECT  33.005 30.384 34.081 31.224 ;
     RECT  33.293 32.208 34.081 34.632 ;
     RECT  33.721 28.512 34.117 29.352 ;
     RECT  33.113 0.144 34.309 0.264 ;
     RECT  34.117 28.512 34.333 29.4 ;
     RECT  33.829 53.28 34.364 58.728 ;
     RECT  33.797 59.808 34.364 61.032 ;
     RECT  34.081 30.384 34.405 34.632 ;
     RECT  33.635 35.712 34.405 39 ;
     RECT  33.395 4.656 34.453 27.192 ;
     RECT  34.364 53.28 34.585 61.032 ;
     RECT  34.309 0.144 34.645 0.312 ;
     RECT  34.009 42.96 34.693 44.184 ;
     RECT  33.587 45.216 34.693 46.728 ;
     RECT  33.587 47.712 34.693 51.384 ;
     RECT  33.833 2.256 34.808 2.328 ;
     RECT  33.973 3.36 34.808 3.384 ;
     RECT  34.453 4.656 34.808 27.336 ;
     RECT  34.333 28.368 34.808 29.4 ;
     RECT  34.405 30.384 34.808 39 ;
     RECT  33.635 40.08 34.808 41.784 ;
     RECT  34.693 42.96 34.808 51.384 ;
     RECT  34.585 53.088 34.808 61.032 ;
     RECT  34.765 62.16 34.808 62.184 ;
     RECT  34.808 2.148 34.912 62.652 ;
     RECT  33.683 64.416 34.981 64.68 ;
     RECT  34.912 2.148 35.104 62.382 ;
     RECT  35.104 37.056 35.129 51.432 ;
     RECT  35.104 16.752 35.219 35.736 ;
     RECT  35.104 53.088 35.219 62.184 ;
     RECT  35.219 59.184 35.273 62.184 ;
     RECT  35.104 2.148 35.317 3.288 ;
     RECT  35.219 53.088 35.363 57.864 ;
     RECT  35.219 30.384 35.489 35.736 ;
     RECT  35.129 37.104 35.489 51.432 ;
     RECT  35.219 16.752 35.561 29.352 ;
     RECT  34.645 0.144 35.597 0.504 ;
     RECT  35.597 0.144 35.849 0.36 ;
     RECT  35.363 56.496 35.891 57.864 ;
     RECT  35.561 20.64 35.993 29.352 ;
     RECT  35.849 0.144 36.065 0.312 ;
     RECT  35.489 41.184 36.065 51.432 ;
     RECT  35.317 1.728 36.073 3.288 ;
     RECT  36.073 2.304 36.133 3.288 ;
     RECT  35.104 4.656 36.133 8.232 ;
     RECT  35.993 20.736 36.173 29.352 ;
     RECT  36.065 42.768 36.181 51.432 ;
     RECT  36.181 42.768 36.209 51.768 ;
     RECT  36.133 2.304 36.227 8.232 ;
     RECT  35.363 53.088 36.227 54.984 ;
     RECT  36.065 41.184 36.253 41.64 ;
     RECT  36.173 22.176 36.284 29.352 ;
     RECT  35.489 30.384 36.284 34.968 ;
     RECT  35.273 60 36.313 62.184 ;
     RECT  35.891 56.544 36.349 57.864 ;
     RECT  36.284 22.176 36.389 34.968 ;
     RECT  36.209 48.432 36.412 51.768 ;
     RECT  36.412 50.304 36.419 51.768 ;
     RECT  36.227 4.224 36.421 8.232 ;
     RECT  35.104 9.36 36.421 15.72 ;
     RECT  35.561 16.752 36.421 19.56 ;
     RECT  35.489 37.104 36.457 40.104 ;
     RECT  36.253 41.184 36.457 41.496 ;
     RECT  36.421 4.224 36.508 19.56 ;
     RECT  36.227 2.304 36.533 3 ;
     RECT  36.389 22.176 36.533 32.424 ;
     RECT  36.412 48.432 36.533 49.272 ;
     RECT  36.227 53.088 36.601 54.12 ;
     RECT  36.389 33.552 36.997 34.968 ;
     RECT  36.065 0.144 37.033 0.264 ;
     RECT  36.997 33.552 37.033 35.016 ;
     RECT  36.241 36.096 37.033 36.12 ;
     RECT  36.508 9.36 37.069 19.56 ;
     RECT  36.173 20.736 37.069 21.192 ;
     RECT  37.069 9.36 37.189 21.192 ;
     RECT  36.533 22.176 37.189 25.56 ;
     RECT  36.313 59.856 37.249 62.184 ;
     RECT  36.508 4.224 37.357 8.28 ;
     RECT  36.349 56.544 37.393 58.104 ;
     RECT  37.249 59.184 37.393 62.184 ;
     RECT  37.033 0.144 37.427 0.6 ;
     RECT  36.209 42.768 37.465 47.304 ;
     RECT  36.533 2.304 37.508 2.856 ;
     RECT  37.357 3.84 37.508 8.28 ;
     RECT  37.189 9.36 37.508 25.56 ;
     RECT  36.533 26.64 37.508 32.424 ;
     RECT  37.033 33.552 37.508 36.12 ;
     RECT  36.457 37.104 37.508 41.496 ;
     RECT  37.465 42.768 37.508 47.88 ;
     RECT  36.533 48.912 37.508 49.272 ;
     RECT  36.419 50.304 37.508 51.432 ;
     RECT  36.601 53.04 37.508 54.12 ;
     RECT  37.393 56.544 37.508 62.184 ;
     RECT  37.508 2.148 37.612 62.652 ;
     RECT  34.981 63.84 37.763 64.68 ;
     RECT  37.612 2.418 37.804 62.652 ;
     RECT  37.804 2.736 37.865 32.232 ;
     RECT  37.865 2.736 37.901 31.992 ;
     RECT  37.804 42.768 37.901 58.536 ;
     RECT  37.901 42.768 37.973 57.144 ;
     RECT  37.901 2.736 38.081 31.416 ;
     RECT  38.081 7.392 38.153 31.416 ;
     RECT  38.081 2.736 38.189 6.408 ;
     RECT  38.153 28.704 38.297 31.416 ;
     RECT  38.189 2.736 38.333 3 ;
     RECT  37.804 59.904 38.365 62.652 ;
     RECT  38.365 59.904 38.387 62.712 ;
     RECT  37.427 0.144 38.435 0.552 ;
     RECT  38.387 62.688 38.449 62.712 ;
     RECT  38.387 59.904 38.729 61.224 ;
     RECT  37.763 64.464 38.797 64.68 ;
     RECT  38.153 7.392 38.819 27.336 ;
     RECT  38.819 17.04 38.873 21.768 ;
     RECT  37.973 56.928 38.917 57.144 ;
     RECT  37.901 58.128 38.917 58.536 ;
     RECT  38.917 56.928 39.004 58.536 ;
     RECT  38.873 21.168 39.053 21.768 ;
     RECT  39.004 56.928 39.059 57.144 ;
     RECT  38.873 17.04 39.107 19.944 ;
     RECT  38.819 22.752 39.121 27.336 ;
     RECT  38.297 28.704 39.121 30.984 ;
     RECT  37.804 33.312 39.157 41.496 ;
     RECT  37.973 42.768 39.157 55.896 ;
     RECT  39.157 33.312 39.233 55.896 ;
     RECT  38.333 2.784 39.349 3 ;
     RECT  39.059 56.928 39.445 57.048 ;
     RECT  38.189 4.224 39.685 6.408 ;
     RECT  38.819 7.392 39.685 15.624 ;
     RECT  39.349 2.256 39.74 3 ;
     RECT  39.685 4.224 39.74 15.624 ;
     RECT  39.233 33.312 39.805 55.272 ;
     RECT  39.805 32.64 39.877 55.272 ;
     RECT  39.74 2.256 39.913 15.624 ;
     RECT  39.445 62.688 39.913 62.712 ;
     RECT  38.797 63.84 39.913 64.68 ;
     RECT  38.729 60 39.949 61.224 ;
     RECT  39.913 62.688 39.949 64.68 ;
     RECT  39.445 56.256 40.057 57.048 ;
     RECT  39.949 60 40.069 64.68 ;
     RECT  39.053 21.168 40.093 21.192 ;
     RECT  39.121 22.752 40.093 30.984 ;
     RECT  39.913 2.256 40.208 16.056 ;
     RECT  39.107 17.184 40.208 19.944 ;
     RECT  40.093 21.168 40.208 30.984 ;
     RECT  39.877 32.208 40.208 55.272 ;
     RECT  40.057 56.256 40.208 57.096 ;
     RECT  39.004 58.416 40.208 58.536 ;
     RECT  40.069 59.568 40.208 64.68 ;
     RECT  40.208 2.148 40.312 64.68 ;
     RECT  40.312 2.256 40.504 64.68 ;
     RECT  40.504 2.256 40.637 15.624 ;
     RECT  40.504 26.784 40.739 34.776 ;
     RECT  40.637 2.256 40.781 7.464 ;
     RECT  38.435 0.144 40.789 0.312 ;
     RECT  40.781 2.256 40.835 6.888 ;
     RECT  40.637 8.448 40.883 15.624 ;
     RECT  40.835 2.784 40.961 6.888 ;
     RECT  40.739 26.784 41.113 29.112 ;
     RECT  40.504 48.24 41.141 61.032 ;
     RECT  40.961 2.784 41.213 6.024 ;
     RECT  40.739 30.144 41.315 34.776 ;
     RECT  40.789 0.144 41.321 0.36 ;
     RECT  40.504 35.76 41.357 38.76 ;
     RECT  41.141 48.24 41.393 51.912 ;
     RECT  41.141 52.896 41.429 61.032 ;
     RECT  40.504 21.792 41.497 25.704 ;
     RECT  40.883 8.496 41.509 15.624 ;
     RECT  40.504 16.608 41.509 20.088 ;
     RECT  41.315 32.928 41.533 34.776 ;
     RECT  41.357 35.76 41.533 38.616 ;
     RECT  40.504 39.84 41.537 46.872 ;
     RECT  41.393 50.304 41.537 51.912 ;
     RECT  41.509 8.496 41.569 20.088 ;
     RECT  41.537 42.336 41.569 46.872 ;
     RECT  41.393 48.24 41.569 49.272 ;
     RECT  41.429 53.04 41.569 61.032 ;
     RECT  40.504 62.16 41.569 64.68 ;
     RECT  41.533 32.928 41.603 38.616 ;
     RECT  41.537 39.84 41.603 41.256 ;
     RECT  41.569 53.04 41.753 64.68 ;
     RECT  41.213 2.784 41.852 5.976 ;
     RECT  41.569 8.496 41.857 20.376 ;
     RECT  41.497 21.648 41.857 25.704 ;
     RECT  41.753 56.208 41.897 64.68 ;
     RECT  41.852 2.256 41.939 5.976 ;
     RECT  41.857 8.496 41.965 25.704 ;
     RECT  41.113 26.784 41.965 29.064 ;
     RECT  41.965 8.496 41.989 29.064 ;
     RECT  41.537 50.592 42.109 51.912 ;
     RECT  41.989 7.968 42.14 29.064 ;
     RECT  41.315 30.144 42.14 31.944 ;
     RECT  41.939 2.496 42.325 5.976 ;
     RECT  42.14 7.968 42.325 31.944 ;
     RECT  41.603 32.928 42.325 38.52 ;
     RECT  42.325 2.496 42.361 6.84 ;
     RECT  42.325 7.968 42.361 38.52 ;
     RECT  42.361 2.496 42.577 38.52 ;
     RECT  42.109 50.592 42.577 51.96 ;
     RECT  42.577 2.496 42.613 38.76 ;
     RECT  41.603 39.84 42.613 41.208 ;
     RECT  42.613 2.496 42.649 41.208 ;
     RECT  41.569 42.336 42.649 49.272 ;
     RECT  41.321 0.144 42.757 0.312 ;
     RECT  42.577 50.496 42.757 51.96 ;
     RECT  41.753 53.04 42.757 54.888 ;
     RECT  42.757 0.144 42.805 0.408 ;
     RECT  41.897 58.656 42.844 64.68 ;
     RECT  42.649 2.496 42.908 49.272 ;
     RECT  42.757 50.496 42.908 54.888 ;
     RECT  41.897 56.208 42.908 57.48 ;
     RECT  42.844 58.656 42.908 62.952 ;
     RECT  42.908 2.148 43.012 62.952 ;
     RECT  42.805 0.144 43.141 0.504 ;
     RECT  43.012 2.418 43.204 62.952 ;
     RECT  43.204 48.144 43.331 49.08 ;
     RECT  43.204 20.304 43.337 28.68 ;
     RECT  43.204 29.76 43.373 46.104 ;
     RECT  43.141 0.096 43.481 0.504 ;
     RECT  43.204 56.208 43.481 62.952 ;
     RECT  43.204 50.592 43.625 54.744 ;
     RECT  43.204 2.496 43.661 19.272 ;
     RECT  43.373 40.416 43.667 46.104 ;
     RECT  43.337 20.352 43.733 28.68 ;
     RECT  43.661 12.576 43.811 19.272 ;
     RECT  43.733 22.176 43.877 28.68 ;
     RECT  43.481 62.928 43.981 62.952 ;
     RECT  42.844 64.368 43.981 64.68 ;
     RECT  43.811 12.576 44.003 18.984 ;
     RECT  43.877 27.312 44.003 28.68 ;
     RECT  43.373 29.76 44.003 39 ;
     RECT  44.003 12.576 44.021 18.696 ;
     RECT  43.481 56.208 44.021 61.224 ;
     RECT  44.003 27.312 44.093 28.488 ;
     RECT  44.021 59.952 44.099 61.224 ;
     RECT  44.093 27.504 44.165 28.488 ;
     RECT  43.877 22.176 44.237 26.28 ;
     RECT  43.981 62.928 44.243 64.68 ;
     RECT  44.021 12.96 44.332 18.312 ;
     RECT  43.625 54.048 44.341 54.744 ;
     RECT  44.021 56.208 44.345 58.68 ;
     RECT  44.345 58.56 44.387 58.68 ;
     RECT  44.003 34.752 44.413 39 ;
     RECT  43.667 40.416 44.413 46.008 ;
     RECT  44.341 54.048 44.437 55.08 ;
     RECT  44.345 56.208 44.437 57.576 ;
     RECT  43.733 20.352 44.449 21.192 ;
     RECT  44.237 22.176 44.483 23.976 ;
     RECT  43.331 48.144 44.483 48.984 ;
     RECT  43.661 2.496 44.489 11.544 ;
     RECT  44.237 25.2 44.489 26.28 ;
     RECT  44.413 34.752 44.489 46.008 ;
     RECT  43.625 50.592 44.531 52.776 ;
     RECT  44.387 58.608 44.531 58.68 ;
     RECT  44.243 62.928 44.533 62.952 ;
     RECT  44.165 27.6 44.561 28.488 ;
     RECT  44.003 29.76 44.561 33.672 ;
     RECT  44.437 54.048 44.593 57.576 ;
     RECT  43.481 0.096 44.701 0.408 ;
     RECT  44.489 35.328 44.737 46.008 ;
     RECT  44.413 47.136 44.737 47.16 ;
     RECT  44.449 20.064 44.965 21.192 ;
     RECT  44.483 22.176 44.965 23.88 ;
     RECT  44.531 50.592 44.965 52.296 ;
     RECT  44.099 60 45.025 61.224 ;
     RECT  44.533 62.688 45.025 62.952 ;
     RECT  44.332 13.104 45.061 18.312 ;
     RECT  45.025 60 45.203 62.952 ;
     RECT  44.489 25.2 45.205 25.848 ;
     RECT  44.561 27.6 45.205 28.44 ;
     RECT  44.965 50.352 45.241 52.296 ;
     RECT  44.701 0.096 45.251 0.552 ;
     RECT  44.483 48.432 45.349 48.984 ;
     RECT  44.965 20.064 45.385 23.88 ;
     RECT  44.489 2.688 45.493 11.544 ;
     RECT  44.243 64.56 45.493 64.68 ;
     RECT  45.061 13.104 45.529 18.456 ;
     RECT  45.493 2.688 45.601 11.736 ;
     RECT  45.529 13.104 45.601 18.84 ;
     RECT  45.601 2.688 45.608 18.84 ;
     RECT  45.385 19.824 45.608 23.88 ;
     RECT  45.205 25.008 45.608 25.848 ;
     RECT  45.205 26.832 45.608 28.44 ;
     RECT  44.561 30.048 45.608 33.672 ;
     RECT  44.737 35.328 45.608 47.16 ;
     RECT  45.349 48.432 45.608 49.032 ;
     RECT  45.241 50.016 45.608 52.296 ;
     RECT  44.593 53.376 45.608 57.576 ;
     RECT  44.531 58.656 45.608 58.68 ;
     RECT  45.203 60 45.608 62.652 ;
     RECT  45.608 2.148 45.712 62.652 ;
     RECT  45.712 2.148 45.853 62.382 ;
     RECT  45.853 1.728 45.904 62.382 ;
     RECT  45.904 1.728 45.937 8.52 ;
     RECT  45.937 2.688 46.019 8.52 ;
     RECT  45.904 9.792 46.019 29.784 ;
     RECT  45.904 39.84 46.037 46.968 ;
     RECT  45.904 60.912 46.037 61.656 ;
     RECT  46.019 25.008 46.067 29.784 ;
     RECT  46.037 60.912 46.109 61.56 ;
     RECT  45.904 55.872 46.156 59.544 ;
     RECT  45.904 30.864 46.181 33.624 ;
     RECT  46.037 39.984 46.217 46.968 ;
     RECT  46.109 61.536 46.217 61.56 ;
     RECT  46.019 2.688 46.253 8.232 ;
     RECT  45.904 48.096 46.253 54.744 ;
     RECT  46.156 58.656 46.325 59.544 ;
     RECT  45.493 63.84 46.433 64.68 ;
     RECT  46.181 32.88 46.469 33.624 ;
     RECT  46.181 30.864 46.613 31.8 ;
     RECT  46.253 54.624 46.721 54.744 ;
     RECT  45.904 34.752 46.739 38.712 ;
     RECT  46.739 36.672 46.835 38.712 ;
     RECT  46.067 26.304 46.901 29.784 ;
     RECT  46.156 55.872 46.901 57.576 ;
     RECT  46.253 2.688 46.937 3.432 ;
     RECT  46.901 26.304 46.937 29.64 ;
     RECT  46.835 38.688 46.937 38.712 ;
     RECT  46.019 9.792 47.009 23.928 ;
     RECT  46.433 64.56 47.075 64.68 ;
     RECT  46.721 54.72 47.113 54.744 ;
     RECT  46.217 45.552 47.18 46.968 ;
     RECT  46.901 55.872 47.189 56.376 ;
     RECT  47.18 45.552 47.219 47.016 ;
     RECT  46.469 32.976 47.257 33.624 ;
     RECT  46.739 34.752 47.257 35.352 ;
     RECT  47.219 45.6 47.257 47.016 ;
     RECT  46.253 48.096 47.257 53.544 ;
     RECT  46.901 57.408 47.257 57.576 ;
     RECT  46.325 58.656 47.257 59.16 ;
     RECT  47.257 45.6 47.267 53.544 ;
     RECT  47.257 57.408 47.293 59.16 ;
     RECT  47.009 9.792 47.317 22.824 ;
     RECT  46.217 39.984 47.317 44.424 ;
     RECT  46.937 3.408 47.365 3.432 ;
     RECT  46.253 4.512 47.365 8.232 ;
     RECT  46.613 30.912 47.437 31.8 ;
     RECT  47.257 32.976 47.437 35.352 ;
     RECT  47.329 2.256 47.468 2.28 ;
     RECT  47.009 23.904 47.509 23.928 ;
     RECT  46.067 25.008 47.509 25.224 ;
     RECT  47.317 9.6 47.617 22.824 ;
     RECT  47.365 3.408 47.689 8.232 ;
     RECT  47.617 9.264 47.689 22.824 ;
     RECT  46.835 36.672 47.869 37.704 ;
     RECT  47.293 57.408 47.893 59.64 ;
     RECT  47.689 3.408 47.989 22.824 ;
     RECT  47.509 23.904 47.989 25.224 ;
     RECT  46.937 26.976 48.013 29.64 ;
     RECT  47.437 30.912 48.037 35.352 ;
     RECT  47.869 36.336 48.037 37.704 ;
     RECT  48.013 26.976 48.085 29.88 ;
     RECT  48.037 30.912 48.085 37.704 ;
     RECT  47.468 2.208 48.133 2.28 ;
     RECT  47.989 3.408 48.133 25.224 ;
     RECT  47.267 47.328 48.301 53.544 ;
     RECT  48.133 2.208 48.308 25.224 ;
     RECT  48.085 26.976 48.308 37.704 ;
     RECT  47.317 39.216 48.308 44.424 ;
     RECT  47.267 45.6 48.308 46.296 ;
     RECT  48.301 47.328 48.308 53.64 ;
     RECT  47.113 54.72 48.308 54.888 ;
     RECT  47.189 55.872 48.308 56.232 ;
     RECT  47.893 57.408 48.308 60.456 ;
     RECT  48.308 2.148 48.412 62.652 ;
     RECT  48.412 2.256 48.604 62.382 ;
     RECT  48.604 16.56 48.629 16.824 ;
     RECT  48.604 31.2 48.629 38.184 ;
     RECT  48.604 43.104 48.629 44.088 ;
     RECT  48.604 14.112 48.665 15.48 ;
     RECT  48.604 21.408 48.665 21.432 ;
     RECT  48.604 27.312 48.665 29.88 ;
     RECT  48.629 31.2 48.665 37.656 ;
     RECT  48.604 5.28 48.701 5.88 ;
     RECT  48.604 7.392 48.701 7.416 ;
     RECT  48.665 34.128 48.737 37.656 ;
     RECT  48.604 47.328 48.737 48.984 ;
     RECT  48.604 58.992 48.737 59.208 ;
     RECT  48.604 2.256 48.755 3.24 ;
     RECT  48.665 27.312 48.755 29.832 ;
     RECT  48.737 34.128 48.755 35.352 ;
     RECT  48.737 36.336 48.755 37.656 ;
     RECT  48.737 47.328 48.755 47.352 ;
     RECT  48.737 59.04 48.765 59.208 ;
     RECT  48.755 3.216 48.803 3.24 ;
     RECT  48.604 53.04 48.803 53.064 ;
     RECT  48.737 48.384 48.809 48.984 ;
     RECT  48.755 27.312 48.817 29.208 ;
     RECT  48.629 16.56 48.845 16.728 ;
     RECT  48.604 24.384 48.851 25.128 ;
     RECT  48.755 35.328 48.851 35.352 ;
     RECT  48.629 43.296 48.851 44.088 ;
     RECT  48.809 48.96 48.851 48.984 ;
     RECT  48.604 50.352 48.851 51.96 ;
     RECT  48.604 55.536 48.851 56.04 ;
     RECT  48.604 57.408 48.851 57.48 ;
     RECT  48.765 59.04 48.851 59.112 ;
     RECT  48.604 39.456 48.873 39.624 ;
     RECT  48.845 16.56 48.881 16.584 ;
     RECT  48.873 39.456 48.881 39.576 ;
     RECT  48.817 27.888 48.899 29.208 ;
     RECT  48.604 40.992 48.899 41.016 ;
     RECT  48.665 14.976 48.917 15.096 ;
     RECT  48.851 55.968 48.947 55.992 ;
     RECT  48.851 57.456 48.947 57.48 ;
     RECT  45.251 0.096 48.953 0.408 ;
     RECT  48.665 31.2 48.953 33.144 ;
     RECT  48.851 59.088 48.953 59.112 ;
     RECT  47.075 64.656 48.953 64.68 ;
     RECT  48.701 5.28 48.989 5.4 ;
     RECT  48.899 28.848 48.989 29.208 ;
     RECT  48.989 28.848 48.995 29.112 ;
     RECT  48.953 0.096 49.061 0.12 ;
     RECT  48.917 14.976 49.061 15 ;
     RECT  48.953 31.2 49.061 32.52 ;
     RECT  48.851 43.872 49.061 43.896 ;
     RECT  48.851 51.936 49.061 51.96 ;
     RECT  48.851 24.384 49.097 24.408 ;
     RECT  48.755 34.128 49.097 34.152 ;
     RECT  48.881 39.456 49.097 39.48 ;
     RECT  48.604 12.24 49.133 12.264 ;
     RECT  48.995 28.848 49.139 28.872 ;
     RECT  49.061 31.488 51.721 32.52 ;
     RECT  51.721 31.488 51.756 31.512 ;
     RECT  51.721 31.512 51.804 31.68 ;
     RECT  51.721 31.68 51.756 31.704 ;
     RECT  51.721 31.704 51.804 31.872 ;
     RECT  51.721 31.872 51.756 31.896 ;
     RECT  51.721 31.896 51.804 32.112 ;
     RECT  51.721 32.112 51.756 32.136 ;
     RECT  51.721 32.136 51.804 32.304 ;
     RECT  51.721 32.304 51.756 32.328 ;
     RECT  51.721 32.328 51.804 32.496 ;
     RECT  51.721 32.496 51.756 32.52 ;
     RECT  51.721 32.52 51.804 33.312 ;
     RECT  51.721 33.312 51.756 33.336 ;
    LAYER M5 ;
     RECT  1.272 0.016 1.584 0.084 ;
     RECT  1.608 0.016 1.92 0.084 ;
     RECT  1.944 0.016 2.256 0.084 ;
     RECT  2.28 0.016 2.592 0.084 ;
     RECT  2.616 0.016 2.928 0.084 ;
     RECT  2.952 0.016 3.312 0.084 ;
     RECT  3.336 0.016 3.648 0.084 ;
     RECT  3.672 0.016 3.984 0.084 ;
     RECT  4.008 0.016 4.32 0.084 ;
     RECT  4.344 0.016 4.656 0.084 ;
     RECT  4.68 0.016 4.992 0.084 ;
     RECT  5.016 0.016 5.328 0.084 ;
     RECT  5.352 0.016 5.664 0.084 ;
     RECT  5.688 0.016 6 0.084 ;
     RECT  6.024 0.016 6.336 0.084 ;
     RECT  6.36 0.016 6.72 0.084 ;
     RECT  6.744 0.016 7.056 0.084 ;
     RECT  7.08 0.016 7.392 0.084 ;
     RECT  7.416 0.016 7.728 0.084 ;
     RECT  7.752 0.016 8.064 0.084 ;
     RECT  8.088 0.016 8.4 0.084 ;
     RECT  8.424 0.016 8.736 0.084 ;
     RECT  8.76 0.016 9.072 0.084 ;
     RECT  9.096 0.016 9.408 0.084 ;
     RECT  9.432 0.016 9.744 0.084 ;
     RECT  9.768 0.016 10.128 0.084 ;
     RECT  10.152 0.016 10.464 0.084 ;
     RECT  10.488 0.016 10.8 0.084 ;
     RECT  10.824 0.016 11.136 0.084 ;
     RECT  11.16 0.016 11.472 0.084 ;
     RECT  11.496 0.016 11.808 0.084 ;
     RECT  11.832 0.016 12.144 0.084 ;
     RECT  12.168 0.016 12.48 0.084 ;
     RECT  12.504 0.016 12.816 0.084 ;
     RECT  12.84 0.016 13.152 0.084 ;
     RECT  13.176 0.016 13.536 0.084 ;
     RECT  13.56 0.016 13.872 0.084 ;
     RECT  13.896 0.016 14.208 0.084 ;
     RECT  14.232 0.016 14.544 0.084 ;
     RECT  14.568 0.016 14.88 0.084 ;
     RECT  14.904 0.016 15.216 0.084 ;
     RECT  15.24 0.016 15.552 0.084 ;
     RECT  15.576 0.016 15.888 0.084 ;
     RECT  15.912 0.016 16.224 0.084 ;
     RECT  16.248 0.016 16.56 0.084 ;
     RECT  16.584 0.016 16.944 0.084 ;
     RECT  16.968 0.016 17.28 0.084 ;
     RECT  17.304 0.016 17.616 0.084 ;
     RECT  17.64 0.016 17.952 0.084 ;
     RECT  17.976 0.016 18.288 0.084 ;
     RECT  18.312 0.016 18.624 0.084 ;
     RECT  18.648 0.016 18.96 0.084 ;
     RECT  18.984 0.016 19.296 0.084 ;
     RECT  19.32 0.016 19.632 0.084 ;
     RECT  19.656 0.016 19.968 0.084 ;
     RECT  19.992 0.016 20.352 0.084 ;
     RECT  20.376 0.016 20.688 0.084 ;
     RECT  20.712 0.016 21.024 0.084 ;
     RECT  21.048 0.016 21.36 0.084 ;
     RECT  21.384 0.016 21.696 0.084 ;
     RECT  21.72 0.016 22.032 0.084 ;
     RECT  22.056 0.016 22.368 0.084 ;
     RECT  22.392 0.016 22.704 0.084 ;
     RECT  22.728 0.016 23.04 0.084 ;
     RECT  23.064 0.016 23.424 0.084 ;
     RECT  23.448 0.016 23.76 0.084 ;
     RECT  23.784 0.016 24.096 0.084 ;
     RECT  24.12 0.016 24.432 0.084 ;
     RECT  24.456 0.016 24.768 0.084 ;
     RECT  24.792 0.016 25.104 0.084 ;
     RECT  25.128 0.016 25.44 0.084 ;
     RECT  25.464 0.016 25.776 0.084 ;
     RECT  25.8 0.016 26.112 0.084 ;
     RECT  26.136 0.016 26.448 0.084 ;
     RECT  26.472 0.016 26.832 0.084 ;
     RECT  26.856 0.016 27.168 0.084 ;
     RECT  27.192 0.016 27.504 0.084 ;
     RECT  27.528 0.016 27.84 0.084 ;
     RECT  27.864 0.016 28.176 0.084 ;
     RECT  28.2 0.016 28.512 0.084 ;
     RECT  28.536 0.016 28.848 0.084 ;
     RECT  28.872 0.016 29.184 0.084 ;
     RECT  29.208 0.016 29.52 0.084 ;
     RECT  29.544 0.016 29.856 0.084 ;
     RECT  29.88 0.016 30.24 0.084 ;
     RECT  30.264 0.016 30.576 0.084 ;
     RECT  30.6 0.016 30.912 0.084 ;
     RECT  30.936 0.016 31.248 0.084 ;
     RECT  31.272 0.016 31.584 0.084 ;
     RECT  31.608 0.016 31.92 0.084 ;
     RECT  31.944 0.016 32.256 0.084 ;
     RECT  32.28 0.016 32.592 0.084 ;
     RECT  32.616 0.016 32.928 0.084 ;
     RECT  32.952 0.016 33.264 0.084 ;
     RECT  33.288 0.016 33.648 0.084 ;
     RECT  33.672 0.016 33.984 0.084 ;
     RECT  34.008 0.016 34.32 0.084 ;
     RECT  34.344 0.016 34.656 0.084 ;
     RECT  34.68 0.016 34.992 0.084 ;
     RECT  35.016 0.016 35.328 0.084 ;
     RECT  35.352 0.016 35.664 0.084 ;
     RECT  35.688 0.016 36 0.084 ;
     RECT  36.024 0.016 36.336 0.084 ;
     RECT  36.36 0.016 36.672 0.084 ;
     RECT  36.696 0.016 37.056 0.084 ;
     RECT  37.08 0.016 37.392 0.084 ;
     RECT  37.416 0.016 37.728 0.084 ;
     RECT  37.752 0.016 38.064 0.084 ;
     RECT  38.088 0.016 38.4 0.084 ;
     RECT  38.424 0.016 38.736 0.084 ;
     RECT  38.76 0.016 39.072 0.084 ;
     RECT  39.096 0.016 39.408 0.084 ;
     RECT  39.432 0.016 39.744 0.084 ;
     RECT  39.768 0.016 40.08 0.084 ;
     RECT  40.104 0.016 40.464 0.084 ;
     RECT  40.488 0.016 40.8 0.084 ;
     RECT  40.824 0.016 41.136 0.084 ;
     RECT  41.16 0.016 41.472 0.084 ;
     RECT  41.496 0.016 41.808 0.084 ;
     RECT  41.832 0.016 42.144 0.084 ;
     RECT  42.168 0.016 42.48 0.084 ;
     RECT  42.504 0.016 42.816 0.084 ;
     RECT  42.84 0.016 43.152 0.084 ;
     RECT  43.176 0.016 43.488 0.084 ;
     RECT  43.512 0.016 43.872 0.084 ;
     RECT  43.896 0.016 44.208 0.084 ;
     RECT  44.232 0.016 44.544 0.084 ;
     RECT  44.568 0.016 44.88 0.084 ;
     RECT  44.904 0.016 45.216 0.084 ;
     RECT  45.24 0.016 45.552 0.084 ;
     RECT  45.576 0.016 45.888 0.084 ;
     RECT  45.912 0.016 46.224 0.084 ;
     RECT  46.248 0.016 46.56 0.084 ;
     RECT  46.584 0.016 46.944 0.084 ;
     RECT  46.968 0.016 47.28 0.084 ;
     RECT  47.304 0.016 47.616 0.084 ;
     RECT  47.64 0.016 47.952 0.084 ;
     RECT  1.248 0.084 47.976 0.131 ;
     RECT  1.584 0.131 12.168 0.179 ;
     RECT  13.872 0.131 18.648 0.179 ;
     RECT  19.632 0.131 19.656 0.179 ;
     RECT  20.688 0.131 26.136 0.179 ;
     RECT  27.168 0.131 42.84 0.179 ;
     RECT  43.872 0.131 47.64 0.179 ;
     RECT  3.312 0.179 3.336 0.227 ;
     RECT  4.656 0.179 8.76 0.227 ;
     RECT  11.808 0.179 12.168 0.227 ;
     RECT  14.88 0.179 15.576 0.227 ;
     RECT  16.56 0.179 18.648 0.227 ;
     RECT  47.28 0.179 47.64 0.227 ;
     RECT  5.328 0.227 5.688 0.275 ;
     RECT  9.744 0.179 10.824 0.275 ;
     RECT  17.616 0.227 18.648 0.275 ;
     RECT  22.704 0.179 22.728 0.275 ;
     RECT  29.856 0.179 42.84 0.275 ;
     RECT  47.616 0.227 47.64 0.275 ;
     RECT  12.144 0.227 12.168 0.323 ;
     RECT  17.952 0.275 18.648 0.323 ;
     RECT  34.32 0.275 36.024 0.323 ;
     RECT  37.056 0.275 37.416 0.323 ;
     RECT  38.4 0.275 39.768 0.323 ;
     RECT  40.8 0.275 42.84 0.323 ;
     RECT  29.856 0.275 31.944 0.371 ;
     RECT  32.928 0.275 32.952 0.371 ;
     RECT  40.8 0.323 40.824 0.371 ;
     RECT  30.912 0.371 30.936 0.419 ;
     RECT  34.656 0.323 36.024 0.515 ;
     RECT  42.144 0.323 42.84 0.515 ;
     RECT  8.736 0.227 8.76 0.563 ;
     RECT  9.744 0.275 10.488 0.563 ;
     RECT  13.872 0.179 13.896 0.563 ;
     RECT  16.56 0.227 16.584 0.563 ;
     RECT  18.624 0.323 18.648 0.563 ;
     RECT  20.688 0.179 20.712 0.563 ;
     RECT  23.76 0.179 23.784 0.563 ;
     RECT  31.92 0.371 31.944 0.563 ;
     RECT  38.4 0.323 38.424 0.563 ;
     RECT  45.216 0.179 45.912 0.563 ;
     RECT  37.392 0.323 37.416 0.611 ;
     RECT  7.392 0.227 7.416 1.763 ;
     RECT  9.744 0.563 9.768 1.763 ;
     RECT  21.696 0.179 21.72 1.763 ;
     RECT  29.856 0.371 29.88 1.763 ;
     RECT  35.328 0.515 36.024 1.763 ;
     RECT  1.584 0.179 2.28 2.137 ;
     RECT  5.328 0.275 5.352 2.137 ;
     RECT  16.464 2.053 16.488 2.137 ;
     RECT  27.168 0.179 27.528 2.137 ;
     RECT  28.512 0.179 28.536 2.137 ;
     RECT  42.144 0.515 42.792 2.137 ;
     RECT  45.888 0.563 45.912 2.137 ;
     RECT  1.584 2.137 2.52 2.151 ;
     RECT  5.1 2.137 5.352 2.151 ;
     RECT  7.44 2.137 7.92 2.151 ;
     RECT  10.5 2.137 10.62 2.151 ;
     RECT  13.2 2.137 13.32 2.151 ;
     RECT  18.6 2.137 18.72 2.151 ;
     RECT  24 2.137 24.12 2.151 ;
     RECT  32.1 2.137 32.22 2.151 ;
     RECT  37.5 2.137 37.62 2.151 ;
     RECT  40.2 2.137 40.32 2.151 ;
     RECT  42.144 2.137 43.02 2.151 ;
     RECT  48.3 2.137 48.42 2.151 ;
     RECT  28.512 2.137 29.712 2.195 ;
     RECT  48.3 2.151 48.612 2.197 ;
     RECT  5.1 2.151 5.412 2.245 ;
     RECT  10.5 2.151 10.812 2.245 ;
     RECT  18.6 2.151 18.912 2.245 ;
     RECT  21.3 2.137 21.612 2.245 ;
     RECT  34.8 2.137 35.208 2.245 ;
     RECT  40.2 2.151 40.512 2.245 ;
     RECT  42.144 2.151 43.212 2.245 ;
     RECT  47.52 2.197 48.612 2.245 ;
     RECT  15.9 2.137 16.488 2.677 ;
     RECT  17.952 2.245 18.912 2.677 ;
     RECT  20.688 2.245 21.612 2.677 ;
     RECT  24 2.151 24.312 2.677 ;
     RECT  45.6 2.137 45.912 2.677 ;
     RECT  47.52 2.245 48.744 2.677 ;
     RECT  4.32 2.245 5.412 2.725 ;
     RECT  4.272 2.725 5.412 2.821 ;
     RECT  7.44 2.151 8.112 2.821 ;
     RECT  10.5 2.245 11.16 2.821 ;
     RECT  26.7 2.137 27.528 2.821 ;
     RECT  39.36 2.245 40.824 2.821 ;
     RECT  41.904 2.245 43.212 2.821 ;
     RECT  39.36 2.821 43.212 3.011 ;
     RECT  44.928 2.677 48.744 3.205 ;
     RECT  33.648 2.245 35.208 3.299 ;
     RECT  7.44 2.821 9.096 3.349 ;
     RECT  10.5 2.821 11.64 3.349 ;
     RECT  13.2 2.151 13.512 3.349 ;
     RECT  25.44 0.179 25.464 3.349 ;
     RECT  26.7 2.821 27.768 3.349 ;
     RECT  1.584 2.151 2.712 3.733 ;
     RECT  3.744 2.821 5.412 3.733 ;
     RECT  17.952 2.677 21.612 3.733 ;
     RECT  23.904 2.677 24.312 3.733 ;
     RECT  25.44 3.349 27.768 3.733 ;
     RECT  29.184 2.195 29.712 3.733 ;
     RECT  15.792 2.677 16.488 3.829 ;
     RECT  7.44 3.349 11.64 3.877 ;
     RECT  25.44 3.733 29.712 3.877 ;
     RECT  39.792 3.011 43.212 3.877 ;
     RECT  44.4 3.205 48.792 3.877 ;
     RECT  6.864 3.877 11.64 3.925 ;
     RECT  13.2 3.349 13.704 3.925 ;
     RECT  15.6 3.829 16.488 3.925 ;
     RECT  17.952 3.733 22.152 3.925 ;
     RECT  23.328 3.733 24.456 3.925 ;
     RECT  32.1 2.151 32.412 4.261 ;
     RECT  33.648 3.299 35.112 4.261 ;
     RECT  15.6 3.925 22.152 4.357 ;
     RECT  23.136 3.925 24.456 4.357 ;
     RECT  36.192 3.877 36.216 4.501 ;
     RECT  37.5 2.151 37.812 4.501 ;
     RECT  36.192 4.501 37.812 4.837 ;
     RECT  6.864 3.925 13.704 5.077 ;
     RECT  36.192 4.837 38.76 5.077 ;
     RECT  39.792 3.877 48.792 5.077 ;
     RECT  1.584 3.733 5.412 5.171 ;
     RECT  32.1 4.261 35.112 5.461 ;
     RECT  6.384 5.077 13.848 5.605 ;
     RECT  15.6 4.357 24.456 5.605 ;
     RECT  25.44 3.877 30.456 5.605 ;
     RECT  31.92 5.461 35.112 5.605 ;
     RECT  6.384 5.605 13.992 5.653 ;
     RECT  2.256 5.171 5.412 5.747 ;
     RECT  6.384 5.653 14.136 5.845 ;
     RECT  15.312 5.605 30.456 5.845 ;
     RECT  31.872 5.605 35.112 6.851 ;
     RECT  6.384 5.845 30.456 6.947 ;
     RECT  31.92 6.851 35.112 7.717 ;
     RECT  36.192 5.077 48.792 7.717 ;
     RECT  6.384 6.947 14.568 7.957 ;
     RECT  15.648 6.947 30.456 7.957 ;
     RECT  31.92 7.717 48.792 8.195 ;
     RECT  2.4 5.747 5.412 8.485 ;
     RECT  6.384 7.957 30.456 8.723 ;
     RECT  15.648 8.723 30.456 8.821 ;
     RECT  31.92 8.195 35.112 8.821 ;
     RECT  6.384 8.723 14.568 9.155 ;
     RECT  15.648 8.821 35.112 9.637 ;
     RECT  6.384 9.155 14.136 10.117 ;
     RECT  2.304 8.485 5.412 10.163 ;
     RECT  15.648 9.637 35.208 10.933 ;
     RECT  36.192 8.195 48.792 10.933 ;
     RECT  15.648 10.933 48.792 10.979 ;
     RECT  6.384 10.117 14.472 11.029 ;
     RECT  15.648 10.979 30.456 11.029 ;
     RECT  2.4 10.163 5.412 11.797 ;
     RECT  6.384 11.029 30.456 11.797 ;
     RECT  2.4 11.797 30.456 12.469 ;
     RECT  31.632 10.979 48.792 12.469 ;
     RECT  2.4 12.469 48.792 13.955 ;
     RECT  2.4 13.955 36.216 15.205 ;
     RECT  37.248 13.955 48.792 15.205 ;
     RECT  2.4 15.205 48.792 16.595 ;
     RECT  15.408 16.595 48.792 16.739 ;
     RECT  15.408 16.739 48.744 17.699 ;
     RECT  2.4 16.595 14.136 17.989 ;
     RECT  1.248 11.941 1.272 18.181 ;
     RECT  2.4 17.989 14.28 18.181 ;
     RECT  1.248 18.181 14.28 18.757 ;
     RECT  15.648 17.699 48.744 18.757 ;
     RECT  1.248 18.757 48.744 20.723 ;
     RECT  15.12 20.723 48.744 25.093 ;
     RECT  1.248 20.723 14.136 25.621 ;
     RECT  15.12 25.093 48.84 25.621 ;
     RECT  1.248 25.621 48.84 25.763 ;
     RECT  45.024 25.763 48.84 27.877 ;
     RECT  1.248 25.763 44.04 28.069 ;
     RECT  45.024 27.877 48.888 28.069 ;
     RECT  1.248 28.069 48.888 28.259 ;
     RECT  45.024 28.259 48.888 28.837 ;
     RECT  45.024 28.837 49.128 31.715 ;
     RECT  1.248 28.259 44.04 31.909 ;
     RECT  45.024 31.715 48.984 31.909 ;
     RECT  1.248 31.909 48.984 32.003 ;
     RECT  1.248 32.003 48.888 41.029 ;
     RECT  1.248 41.029 48.84 44.099 ;
     RECT  1.248 44.099 48.744 47.363 ;
     RECT  1.248 47.363 48.612 48.949 ;
     RECT  1.248 48.949 48.84 50.675 ;
     RECT  14.928 50.675 48.84 51.155 ;
     RECT  14.928 51.155 48.792 53.075 ;
     RECT  1.248 50.675 13.848 53.269 ;
     RECT  14.928 53.075 48.612 53.269 ;
     RECT  1.248 53.269 48.612 55.525 ;
     RECT  1.248 55.525 48.84 55.955 ;
     RECT  22.944 55.955 48.84 55.957 ;
     RECT  22.944 55.957 48.936 57.059 ;
     RECT  22.944 57.059 27.864 57.347 ;
     RECT  28.896 57.059 48.936 57.491 ;
     RECT  1.248 55.955 21.768 58.213 ;
     RECT  22.944 57.347 27.72 58.213 ;
     RECT  28.896 57.491 48.84 58.451 ;
     RECT  1.248 58.213 27.72 58.931 ;
     RECT  39.936 58.451 48.84 59.075 ;
     RECT  39.936 59.075 48.744 59.219 ;
     RECT  28.896 58.451 38.952 60.035 ;
     RECT  22.944 58.931 27.72 60.133 ;
     RECT  28.896 60.035 38.664 60.133 ;
     RECT  22.944 60.133 38.664 61.475 ;
     RECT  1.248 58.931 21.72 62.197 ;
     RECT  22.944 61.475 27.72 62.197 ;
     RECT  1.248 62.197 27.72 62.649 ;
     RECT  39.936 59.219 48.612 62.649 ;
     RECT  28.896 61.475 38.664 62.663 ;
     RECT  39.936 62.649 48.42 62.663 ;
     RECT  28.896 62.663 34.344 62.677 ;
     RECT  39.936 62.663 47.976 62.677 ;
     RECT  1.248 62.649 24.12 63.829 ;
     RECT  25.152 62.649 27.72 63.829 ;
     RECT  28.848 62.677 34.344 63.829 ;
     RECT  35.328 62.663 36.6 63.829 ;
     RECT  37.92 62.663 38.664 63.829 ;
     RECT  39.744 62.677 47.976 63.829 ;
     RECT  1.248 63.829 27.72 64.453 ;
     RECT  1.248 64.453 27.864 64.549 ;
     RECT  28.848 63.829 47.976 64.549 ;
     RECT  1.248 64.549 47.976 64.716 ;
     RECT  1.272 64.716 1.584 64.784 ;
     RECT  1.608 64.716 1.92 64.784 ;
     RECT  1.944 64.716 2.256 64.784 ;
     RECT  2.28 64.716 2.592 64.784 ;
     RECT  2.616 64.716 2.928 64.784 ;
     RECT  2.952 64.716 3.312 64.784 ;
     RECT  3.336 64.716 3.648 64.784 ;
     RECT  3.672 64.716 3.984 64.784 ;
     RECT  4.008 64.716 4.32 64.784 ;
     RECT  4.344 64.716 4.656 64.784 ;
     RECT  4.68 64.716 4.992 64.784 ;
     RECT  5.016 64.716 5.328 64.784 ;
     RECT  5.352 64.716 5.664 64.784 ;
     RECT  5.688 64.716 6 64.784 ;
     RECT  6.024 64.716 6.336 64.784 ;
     RECT  6.36 64.716 6.72 64.784 ;
     RECT  6.744 64.716 7.056 64.784 ;
     RECT  7.08 64.716 7.392 64.784 ;
     RECT  7.416 64.716 7.728 64.784 ;
     RECT  7.752 64.716 8.064 64.784 ;
     RECT  8.088 64.716 8.4 64.784 ;
     RECT  8.424 64.716 8.736 64.784 ;
     RECT  8.76 64.716 9.072 64.784 ;
     RECT  9.096 64.716 9.408 64.784 ;
     RECT  9.432 64.716 9.744 64.784 ;
     RECT  9.768 64.716 10.128 64.784 ;
     RECT  10.152 64.716 10.464 64.784 ;
     RECT  10.488 64.716 10.8 64.784 ;
     RECT  10.824 64.716 11.136 64.784 ;
     RECT  11.16 64.716 11.472 64.784 ;
     RECT  11.496 64.716 11.808 64.784 ;
     RECT  11.832 64.716 12.144 64.784 ;
     RECT  12.168 64.716 12.48 64.784 ;
     RECT  12.504 64.716 12.816 64.784 ;
     RECT  12.84 64.716 13.152 64.784 ;
     RECT  13.176 64.716 13.536 64.784 ;
     RECT  13.56 64.716 13.872 64.784 ;
     RECT  13.896 64.716 14.208 64.784 ;
     RECT  14.232 64.716 14.544 64.784 ;
     RECT  14.568 64.716 14.88 64.784 ;
     RECT  14.904 64.716 15.216 64.784 ;
     RECT  15.24 64.716 15.552 64.784 ;
     RECT  15.576 64.716 15.888 64.784 ;
     RECT  15.912 64.716 16.224 64.784 ;
     RECT  16.248 64.716 16.56 64.784 ;
     RECT  16.584 64.716 16.944 64.784 ;
     RECT  16.968 64.716 17.28 64.784 ;
     RECT  17.304 64.716 17.616 64.784 ;
     RECT  17.64 64.716 17.952 64.784 ;
     RECT  17.976 64.716 18.288 64.784 ;
     RECT  18.312 64.716 18.624 64.784 ;
     RECT  18.648 64.716 18.96 64.784 ;
     RECT  18.984 64.716 19.296 64.784 ;
     RECT  19.32 64.716 19.632 64.784 ;
     RECT  19.656 64.716 19.968 64.784 ;
     RECT  19.992 64.716 20.352 64.784 ;
     RECT  20.376 64.716 20.688 64.784 ;
     RECT  20.712 64.716 21.024 64.784 ;
     RECT  21.048 64.716 21.36 64.784 ;
     RECT  21.384 64.716 21.696 64.784 ;
     RECT  21.72 64.716 22.032 64.784 ;
     RECT  22.056 64.716 22.368 64.784 ;
     RECT  22.392 64.716 22.704 64.784 ;
     RECT  22.728 64.716 23.04 64.784 ;
     RECT  23.064 64.716 23.424 64.784 ;
     RECT  23.448 64.716 23.76 64.784 ;
     RECT  23.784 64.716 24.096 64.784 ;
     RECT  24.12 64.716 24.432 64.784 ;
     RECT  24.456 64.716 24.768 64.784 ;
     RECT  24.792 64.716 25.104 64.784 ;
     RECT  25.128 64.716 25.44 64.784 ;
     RECT  25.464 64.716 25.776 64.784 ;
     RECT  25.8 64.716 26.112 64.784 ;
     RECT  26.136 64.716 26.448 64.784 ;
     RECT  26.472 64.716 26.832 64.784 ;
     RECT  26.856 64.716 27.168 64.784 ;
     RECT  27.192 64.716 27.504 64.784 ;
     RECT  27.528 64.716 27.84 64.784 ;
     RECT  27.864 64.716 28.176 64.784 ;
     RECT  28.2 64.716 28.512 64.784 ;
     RECT  28.536 64.716 28.848 64.784 ;
     RECT  28.872 64.716 29.184 64.784 ;
     RECT  29.208 64.716 29.52 64.784 ;
     RECT  29.544 64.716 29.856 64.784 ;
     RECT  29.88 64.716 30.24 64.784 ;
     RECT  30.264 64.716 30.576 64.784 ;
     RECT  30.6 64.716 30.912 64.784 ;
     RECT  30.936 64.716 31.248 64.784 ;
     RECT  31.272 64.716 31.584 64.784 ;
     RECT  31.608 64.716 31.92 64.784 ;
     RECT  31.944 64.716 32.256 64.784 ;
     RECT  32.28 64.716 32.592 64.784 ;
     RECT  32.616 64.716 32.928 64.784 ;
     RECT  32.952 64.716 33.264 64.784 ;
     RECT  33.288 64.716 33.648 64.784 ;
     RECT  33.672 64.716 33.984 64.784 ;
     RECT  34.008 64.716 34.32 64.784 ;
     RECT  34.344 64.716 34.656 64.784 ;
     RECT  34.68 64.716 34.992 64.784 ;
     RECT  35.016 64.716 35.328 64.784 ;
     RECT  35.352 64.716 35.664 64.784 ;
     RECT  35.688 64.716 36 64.784 ;
     RECT  36.024 64.716 36.336 64.784 ;
     RECT  36.36 64.716 36.672 64.784 ;
     RECT  36.696 64.716 37.056 64.784 ;
     RECT  37.08 64.716 37.392 64.784 ;
     RECT  37.416 64.716 37.728 64.784 ;
     RECT  37.752 64.716 38.064 64.784 ;
     RECT  38.088 64.716 38.4 64.784 ;
     RECT  38.424 64.716 38.736 64.784 ;
     RECT  38.76 64.716 39.072 64.784 ;
     RECT  39.096 64.716 39.408 64.784 ;
     RECT  39.432 64.716 39.744 64.784 ;
     RECT  39.768 64.716 40.08 64.784 ;
     RECT  40.104 64.716 40.464 64.784 ;
     RECT  40.488 64.716 40.8 64.784 ;
     RECT  40.824 64.716 41.136 64.784 ;
     RECT  41.16 64.716 41.472 64.784 ;
     RECT  41.496 64.716 41.808 64.784 ;
     RECT  41.832 64.716 42.144 64.784 ;
     RECT  42.168 64.716 42.48 64.784 ;
     RECT  42.504 64.716 42.816 64.784 ;
     RECT  42.84 64.716 43.152 64.784 ;
     RECT  43.176 64.716 43.488 64.784 ;
     RECT  43.512 64.716 43.872 64.784 ;
     RECT  43.896 64.716 44.208 64.784 ;
     RECT  44.232 64.716 44.544 64.784 ;
     RECT  44.568 64.716 44.88 64.784 ;
     RECT  44.904 64.716 45.216 64.784 ;
     RECT  45.24 64.716 45.552 64.784 ;
     RECT  45.576 64.716 45.888 64.784 ;
     RECT  45.912 64.716 46.224 64.784 ;
     RECT  46.248 64.716 46.56 64.784 ;
     RECT  46.584 64.716 46.944 64.784 ;
     RECT  46.968 64.716 47.28 64.784 ;
     RECT  47.304 64.716 47.616 64.784 ;
     RECT  47.64 64.716 47.952 64.784 ;
     RECT  18.744 0.131 18.864 0.179 ;
     RECT  19.08 0.131 19.2 0.179 ;
     RECT  19.416 0.131 19.536 0.179 ;
     RECT  19.752 0.131 19.872 0.179 ;
     RECT  20.088 0.131 20.256 0.179 ;
     RECT  20.472 0.131 20.592 0.179 ;
     RECT  26.232 0.131 26.352 0.179 ;
     RECT  26.568 0.131 26.736 0.179 ;
     RECT  26.952 0.131 27.072 0.179 ;
     RECT  42.936 0.131 43.056 0.179 ;
     RECT  43.272 0.131 43.392 0.179 ;
     RECT  43.608 0.131 43.776 0.179 ;
     RECT  2.376 0.179 2.496 0.18 ;
     RECT  2.712 0.179 2.832 0.18 ;
     RECT  3.048 0.179 3.216 0.18 ;
     RECT  3.432 0.179 3.552 0.18 ;
     RECT  3.768 0.179 3.888 0.18 ;
     RECT  4.104 0.179 4.224 0.18 ;
     RECT  4.44 0.179 4.56 0.18 ;
     RECT  8.856 0.179 8.976 0.18 ;
     RECT  9.192 0.179 9.312 0.18 ;
     RECT  9.528 0.179 9.648 0.18 ;
     RECT  10.92 0.179 11.04 0.18 ;
     RECT  11.256 0.179 11.376 0.18 ;
     RECT  11.592 0.179 11.712 0.18 ;
     RECT  13.992 0.179 14.112 0.18 ;
     RECT  14.328 0.179 14.448 0.18 ;
     RECT  14.664 0.179 14.784 0.18 ;
     RECT  15.672 0.179 15.792 0.18 ;
     RECT  16.008 0.179 16.128 0.18 ;
     RECT  16.344 0.179 16.464 0.18 ;
     RECT  20.808 0.179 20.928 0.18 ;
     RECT  21.144 0.179 21.264 0.18 ;
     RECT  21.48 0.179 21.6 0.18 ;
     RECT  21.816 0.179 21.936 0.18 ;
     RECT  22.152 0.179 22.272 0.18 ;
     RECT  22.488 0.179 22.608 0.18 ;
     RECT  22.824 0.179 22.944 0.18 ;
     RECT  23.16 0.179 23.328 0.18 ;
     RECT  23.544 0.179 23.664 0.18 ;
     RECT  27.624 0.179 27.744 0.18 ;
     RECT  27.96 0.179 28.08 0.18 ;
     RECT  28.296 0.179 28.416 0.18 ;
     RECT  28.632 0.179 28.752 0.18 ;
     RECT  28.968 0.179 29.088 0.18 ;
     RECT  29.304 0.179 29.424 0.18 ;
     RECT  29.64 0.179 29.76 0.18 ;
     RECT  46.008 0.179 46.128 0.18 ;
     RECT  46.344 0.179 46.464 0.18 ;
     RECT  46.68 0.179 46.848 0.18 ;
     RECT  47.064 0.179 47.184 0.18 ;
     RECT  2.28 0.18 3.312 0.227 ;
     RECT  3.336 0.18 4.656 0.227 ;
     RECT  8.76 0.18 9.744 0.563 ;
     RECT  10.824 0.18 11.808 0.227 ;
     RECT  13.896 0.18 14.88 0.227 ;
     RECT  15.576 0.18 16.56 0.227 ;
     RECT  20.712 0.18 21.696 0.563 ;
     RECT  21.72 0.18 22.704 0.275 ;
     RECT  22.728 0.18 23.76 0.275 ;
     RECT  27.528 0.18 28.512 2.195 ;
     RECT  28.536 0.18 29.856 1.763 ;
     RECT  45.912 0.18 47.28 0.227 ;
     RECT  7.416 0.227 8.736 0.563 ;
     RECT  10.824 0.227 12.144 0.275 ;
     RECT  16.584 0.227 17.616 0.275 ;
     RECT  16.584 0.275 17.952 0.323 ;
     RECT  31.944 0.275 32.928 0.371 ;
     RECT  32.952 0.275 34.32 0.323 ;
     RECT  36.024 0.275 37.056 0.323 ;
     RECT  37.416 0.275 38.4 0.563 ;
     RECT  39.768 0.275 40.8 0.323 ;
     RECT  36.024 0.323 37.392 0.611 ;
     RECT  40.824 0.323 42.144 0.371 ;
     RECT  29.88 0.371 30.912 0.419 ;
     RECT  30.936 0.371 31.92 0.419 ;
     RECT  9.744 1.763 9.768 2.137 ;
     RECT  28.536 1.763 29.712 2.137 ;
     RECT  9.744 2.137 10.5 2.821 ;
     RECT  24.12 2.137 25.44 2.151 ;
     RECT  25.464 2.137 26.7 3.349 ;
     RECT  24.312 2.151 25.44 3.733 ;
     RECT  27.528 2.195 29.184 2.821 ;
     RECT  16.488 2.245 17.952 3.925 ;
     RECT  32.412 2.245 33.648 4.261 ;
     RECT  40.824 2.245 41.904 2.821 ;
     RECT  2.712 2.821 3.744 3.733 ;
     RECT  9.096 2.821 10.5 3.349 ;
     RECT  27.768 2.821 29.184 3.733 ;
     RECT  43.212 3.205 44.4 3.877 ;
     RECT  35.112 3.299 35.208 3.877 ;
     RECT  22.152 3.733 23.328 3.925 ;
     RECT  24.456 3.733 25.44 5.605 ;
     RECT  5.412 3.877 6.864 5.077 ;
     RECT  35.112 3.877 36.192 7.717 ;
     RECT  36.216 3.877 37.5 4.501 ;
     RECT  22.152 3.925 23.136 4.357 ;
     RECT  38.76 4.837 39.792 5.077 ;
     RECT  5.412 5.077 6.384 11.797 ;
     RECT  30.456 5.461 31.92 5.605 ;
     RECT  13.992 5.605 15.312 5.653 ;
     RECT  30.456 5.605 31.872 6.851 ;
     RECT  14.136 5.653 15.312 5.845 ;
     RECT  30.456 6.851 31.92 8.821 ;
     RECT  14.568 6.947 15.648 7.957 ;
     RECT  35.112 8.195 36.192 9.637 ;
     RECT  14.568 8.723 15.648 9.155 ;
     RECT  14.136 9.155 15.648 10.117 ;
     RECT  35.208 9.637 36.192 10.933 ;
     RECT  14.472 10.117 15.648 11.029 ;
     RECT  30.456 10.979 31.632 12.469 ;
     RECT  1.272 11.941 2.4 18.181 ;
     RECT  36.216 13.955 37.248 15.205 ;
     RECT  14.136 16.595 15.408 17.699 ;
     RECT  14.136 17.699 15.648 17.989 ;
     RECT  14.28 17.989 15.648 18.757 ;
     RECT  14.136 20.723 15.12 25.621 ;
     RECT  44.04 25.763 45.024 28.069 ;
     RECT  44.04 28.259 45.024 31.909 ;
     RECT  13.848 50.675 14.928 53.269 ;
     RECT  21.768 55.955 22.944 58.213 ;
     RECT  27.864 57.059 28.896 57.347 ;
     RECT  27.72 57.347 28.896 60.133 ;
     RECT  38.952 58.451 39.936 60.035 ;
     RECT  21.72 58.931 22.944 62.197 ;
     RECT  38.664 60.035 39.936 62.677 ;
     RECT  27.72 61.475 28.896 62.677 ;
     RECT  24.12 62.649 25.152 63.829 ;
     RECT  34.344 62.663 35.328 63.829 ;
     RECT  36.6 62.663 37.92 63.829 ;
     RECT  27.72 62.677 28.848 64.453 ;
     RECT  38.664 62.677 39.744 63.829 ;
     RECT  27.864 64.453 28.848 64.549 ;
  END
END dsfd_dvland_276l
END LIBRARY
